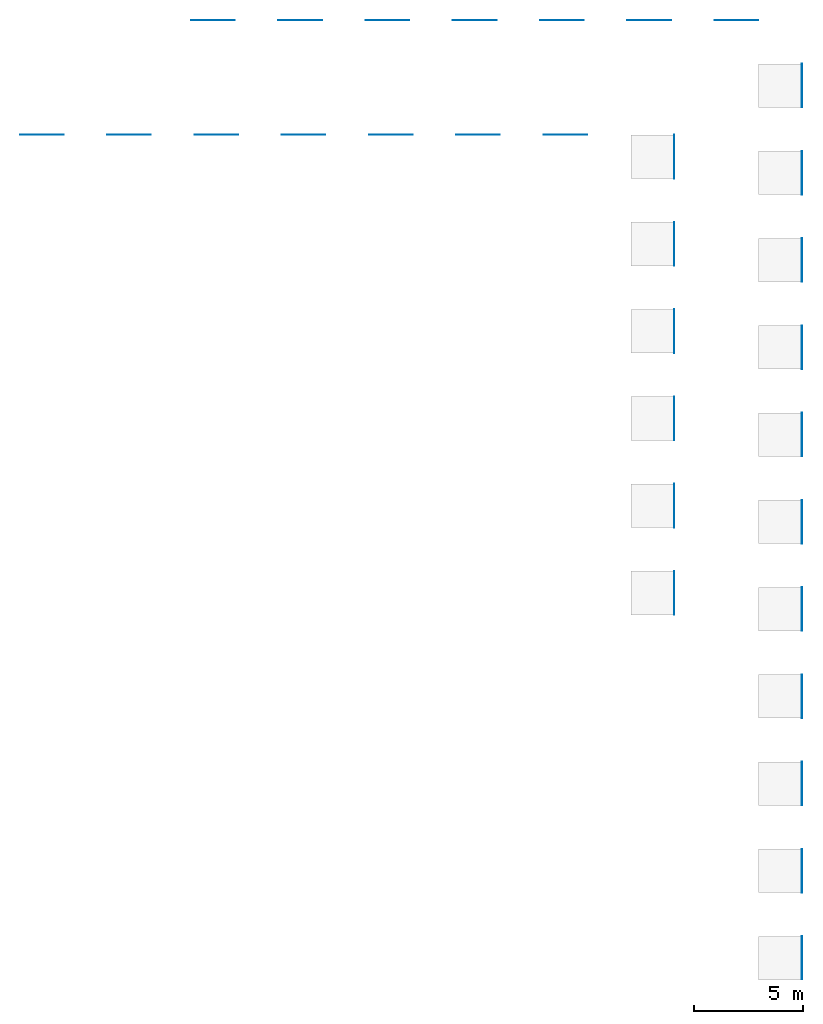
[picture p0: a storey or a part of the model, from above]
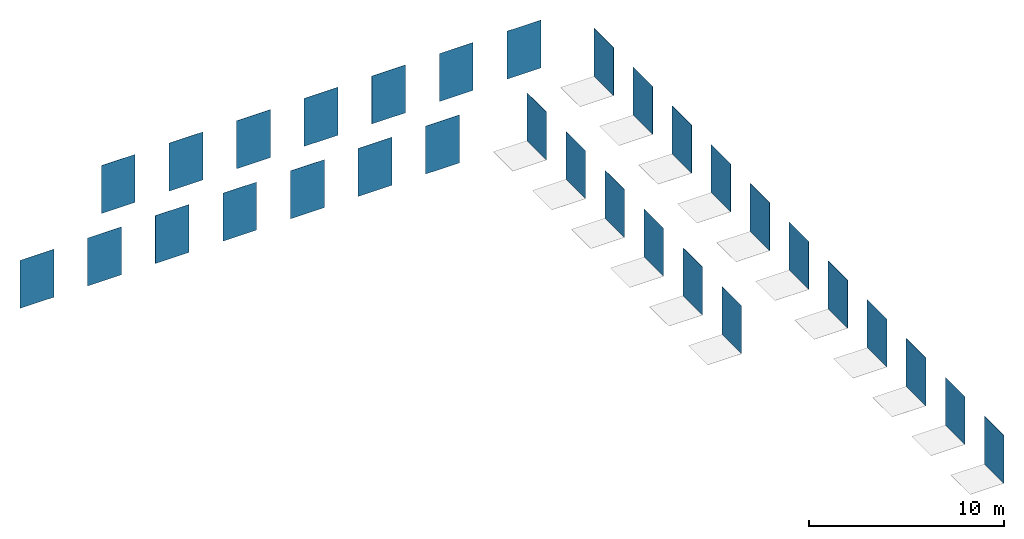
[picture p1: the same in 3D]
Properties of the parts of a building model (IFC2X3), part 1 of 3

# File
Description: ViewDefinition [CoordinationView_V2.0]
File name: Project Number
Time: 2018-07-16T11:43:54
Written by: The EXPRESS Data Manager Version 5.02.0100.07 : 28 Aug 2013
Made in: 20171027_0315(x64) - Exporter 17.2.0.0 - Alternate UI 17.2.0.0
Comment: STEP Physical File produced by: The EXPRESS Data Manager Version 5.02.0100.07 : 28 Aug 2013 * Module: EDMstepFileFactory/EDMstandAlone * Creation date: Mon Jul 16 11:43:54 2018 * Host: aieadsegarra * Database: C:\Users\ES0050~3\AppData\Local\Temp\{0624A31F-D076-47B5-B2E2-24FCC1FBA4B9}\ifc * Database version: 5507 * Database creation date: Mon Jul 16 11:43:53 2018 * Schema: IFC2X3 * Model: DataRepository.ifc * Model creation date: Mon Jul 16 11:43:54 2018 * Header model: DataRepository.ifc_HeaderModel * Header model creation date: Mon Jul 16 11:43:54 2018 * EDMuser: sdai-user * EDMgroup: sdai-group * License ID and type: 5605 : Permanent license. Expiry date: * EDMstepFileFactory options: 020000

# IfcProject, Project Number
LongName: Project Name; Phase: Project Status

# IfcSite, Default
RefLatitude: 42, 21, 31, 181945; RefLongitude: -71, -3, -24, -263305; RefElevation: 0 mm

# IfcBuildingStorey, Level 1
LongName: Level 1; Elevation: 0 mm

# IfcCovering: Floor:PGR_Porcelanosa_CeramicTiles_Bottega_Acero-1200x1200mm-100227107, Floor:PGR_Porcelanosa_CeramicTiles_Bottega_Acero-1200x1200mm-100227107:202324
In: Level 1
PredefinedType: FLOORING; Material: PGR_Porcelanosa_CeramicTiles_Bottega_Acero-1200x1200mm-100227107 12 mm
NBS_General - Author: Porcelanosa Group; BIMObjectName: PGR_Porcelanosa_CeramicTiles_Bottega_Acero-1200x1200mm-100227107; ManufacturerURL: www.porcelanosa.com; NBSDescription: Ceramic Tiles; NBSReference: 45-80-95/310; ProductInformation: http://calidad.info-grupo.com:8081/GeneraFicha3/PDF?articulo=100227107&lang=EN&un=0; Revision: n/a; Uniclass2015Code: Pr_35_93_96_19; Uniclass2015Title: Ceramic Tiles; Uniclass2015Version: Products v1.5; Version: 1
COBie - AccessibilityPerformance: See ProductInformation (Technical PDF); AssetType: Fixed; Category: Floors; CodePerformance: ISO-13006:2012; UNE-EN 14411:2012; Color: Gris; Constituents: Clays, feldespat and glaze; Description: Rectified Porcelain tiles, BOTEGA series from PORCELANOSA, GRIS color and MATTE finish, 120x120 cm (11.5 mm thickness), group BIa, according to UNE-EN 14411, water absortion capacity E<=0.5%, flexural strength >40 N/mm², breaking strength with an average value of 3310 N (Min. 1300 N) and slip resistance R-10; DurationUnit: year; ExpectedLife: 50; Features: See ProductInformation (Technical PDF); Grade: First quality; Manufacturer: bim.gp@porcelanosagrupo.com; ModelNumber: 100227107; ModelReference: Bottega Acero 120x120 cm; Name: CeramicTiles_Bottega_Acero-1200x1200mm-100227107; NominalHeight: 11.5 mm; NominalLength: 1200 mm; NominalWidth: 1200 mm; ReplacementCost: n/a; Shape: Squared; Size: 1200x1200x11.5 mm; Sustainability Performance: See ProductInformation (Technical PDF); WarrantyDescription: Manufacturer warranty, applicable worldwide, with the pertinent national legislation prevailing in all cases and covering at least a 3-year period; all products must have been manufactured and fitted in accordance with the Fabricator's Manual, and have been used and cared for in accordance with the Guide to Use, Cleaning and Care available on the web page www.porcelanosa.com; WarrantyDurationLabor: n/a; WarrantyDurationParts: 3; WarrantyDurationUnit: year; WarrantyGuarantorLabor: n/a; WarrantyGuarantorParts: bim.gp@porcelanosagrupo.com; AssetIdentifier: n/a; BarCode: n/a; InstallationDate: 1900-12-31T23:59:59; TagNumber: n/a; WarrantyStartDate: 1900-12-31T23:59:59
Pset_CoveringCommon - AcousticRating: n/a; Finish: Concrete, Tone Variations, Matte, Rectified; FireRating: A1; FlammabilityRating: Class 0; FragilityRating: n/a; IsExternal: yes; Material: Ceramic; SurfaceSpreadOfFlame: Class 0; ThermalTransmittance: 200 kg/K/s3; TotalThickness: 11.5 mm; Reference: n/a
Pset_CoveringFlooring - HasAntiStaticSurface: no; HasNonSkidSurface: no
IFC - IfcExportType: FLOORING; IfcExportAS: IfcCovering
NBS_Data - AbrasionResistance: 6: Intense-External Access; BreakingStrength: Average Value: 3310 N (Min. 1300 N); ChemicalResistance: Class 'A' for swimming pools and cleaning products (resists attack); minimum Class 'B' for acids and bases; Collection: Porcelanico Tecnico; CreationDate: 2018/07; Dcof: n/a; FlexuralStrength: http://www.porcelanosa.com/product_finder/resources/pdf/inscol/files/GENCER-Fixing-Instructions.pdf; FrostResistance: >40 N/mm²; Group: Conforms to ISO 10545-9; HasSurfaceRoughness: no; MoistureExpansion: <(6.5x10e-6)/°K; RampTest: <0.1 mm/m; RecycledContent: R-10; Series: >6.5%; SlipResistanceValuePendulumTestValue: Botega; StainResistance: CL1; SurfaceQuality: Class 5: Easy cleaning with water; ThermalShockResistance: Without surface defects; UpecC: n/a; UpecE: n/a; UpecP: n/a; UpecU: Conforms to ISO 10545–12; WaterAbsorption: n/a

# IfcCovering: Floor:PGR_Porcelanosa_CeramicTiles_Bottega_Acero-443x443mm-100225055, Floor:PGR_Porcelanosa_CeramicTiles_Bottega_Acero-443x443mm-100225055:213377
In: Level 1
PredefinedType: FLOORING; Material: PGR_Porcelanosa_CeramicTiles_Bottega_Acero-443x443mm-100225055 10.3 mm
NBS_General - Author: Porcelanosa Group; BIMObjectName: PGR_Porcelanosa_CeramicTiles_Bottega_Acero-443x443mm-100225055; ManufacturerURL: www.porcelanosa.com; NBSDescription: Ceramic Tiles; NBSReference: 45-80-95/310; ProductInformation: http://calidad.info-grupo.com:8081/GeneraFicha3/PDF?articulo=100225055&lang=EN&un=0; Revision: n/a; Uniclass2015Code: Pr_35_93_96_19; Uniclass2015Title: Ceramic Tiles; Uniclass2015Version: Products v1.5; Version: 1
COBie - AccessibilityPerformance: See ProductInformation (Technical PDF); AssetType: Fixed; Category: Floors; CodePerformance: ISO-13006:2012; UNE-EN 14411:2012; Color: Gris; Constituents: Clays, feldespat and glaze; Description: Porcelain tiles, BOTEGA series from PORCELANOSA, GRIS color and MATTE finish, 44.3x44.3 cm (10 mm thickness), group BIa, according to UNE-EN 14411, water absortion capacity E<=0.5%, flexural strength >40 N/mm², breaking strength with an average value of 3310 N (Min. 1300 N) and slip resistance R-10; DurationUnit: year; ExpectedLife: 50; Features: See ProductInformation (Technical PDF); Grade: First quality; Manufacturer: bim.gp@porcelanosagrupo.com; ModelNumber: 100225055; ModelReference: Bottega Acero 44.3x44.3 cm; Name: CeramicTiles_Bottega_Acero-443x443mm-100225055; NominalHeight: 10 mm; NominalLength: 443 mm; NominalWidth: 443 mm; ReplacementCost: n/a; Shape: Squared; Size: 443x443x10 mm; Sustainability Performance: See ProductInformation (Technical PDF); WarrantyDescription: Manufacturer warranty, applicable worldwide, with the pertinent national legislation prevailing in all cases and covering at least a 3-year period; all products must have been manufactured and fitted in accordance with the Fabricator's Manual, and have been used and cared for in accordance with the Guide to Use, Cleaning and Care available on the web page www.porcelanosa.com; WarrantyDurationLabor: n/a; WarrantyDurationParts: 3; WarrantyDurationUnit: year; WarrantyGuarantorLabor: n/a; WarrantyGuarantorParts: bim.gp@porcelanosagrupo.com; AssetIdentifier: n/a; BarCode: n/a; InstallationDate: 1900-12-31T23:59:59; TagNumber: n/a; WarrantyStartDate: 1900-12-31T23:59:59
Pset_CoveringCommon - IsExternal: yes; Reference: n/a; AcousticRating: n/a; Finish: Concrete, Tone Variations, Matte; FireRating: A1; FlammabilityRating: Class 0; FragilityRating: n/a; Material: Ceramic; SurfaceSpreadOfFlame: Class 0; ThermalTransmittance: 230 kg/K/s3; TotalThickness: 10 mm
Pset_CoveringFlooring - HasAntiStaticSurface: no; HasNonSkidSurface: no
IFC - IfcExportType: FLOORING; IfcExportAS: IfcCovering
NBS_Data - HasSurfaceRoughness: no; AbrasionResistance: 6: Intense-External Access; BreakingStrength: Average Value: 3310 N (Min. 1300 N); ChemicalResistance: Class 'A' for swimming pools and cleaning products (resists attack); minimum Class 'B' for acids and bases; Collection: Porcelanico; CreationDate: 2018/07; Dcof: n/a; FlexuralStrength: http://www.porcelanosa.com/product_finder/resources/pdf/inscol/files/GENCER-Fixing-Instructions.pdf; FrostResistance: >40 N/mm²; Group: Conforms to ISO 10545-9; MoistureExpansion: <(6.5x10e-6)/°K; RampTest: <0.1 mm/m; RecycledContent: R-10; Series: >6.5%; SlipResistanceValuePendulumTestValue: Botega; StainResistance: CL1; SurfaceQuality: Class 5: Easy cleaning with water; ThermalShockResistance: Without surface defects; UpecC: n/a; UpecE: n/a; UpecP: n/a; UpecU: Conforms to ISO 10545–12; WaterAbsorption: n/a

# IfcCovering: Floor:PGR_Porcelanosa_CeramicTiles_Bottega_Acero-596x596mm-100214641, Floor:PGR_Porcelanosa_CeramicTiles_Bottega_Acero-596x596mm-100214641:213277
In: Level 1
PredefinedType: FLOORING; Material: PGR_Porcelanosa_CeramicTiles_Bottega_Acero-596x596mm-100214641 10.3 mm
NBS_General - Author: Porcelanosa Group; BIMObjectName: PGR_Porcelanosa_CeramicTiles_Bottega_Acero-596x596mm-100214641; ManufacturerURL: www.porcelanosa.com; NBSDescription: Ceramic Tiles; NBSReference: 45-80-95/310; ProductInformation: http://calidad.info-grupo.com:8081/GeneraFicha3/PDF?articulo=100214641&lang=EN&un=0; Revision: n/a; Uniclass2015Code: Pr_35_93_96_19; Uniclass2015Title: Ceramic Tiles; Uniclass2015Version: Products v1.5; Version: 1
COBie - AccessibilityPerformance: See ProductInformation (Technical PDF); AssetType: Fixed; Category: Floors; CodePerformance: ISO-13006:2012; UNE-EN 14411:2012; Color: Gris; Constituents: Clays, feldespat and glaze; Description: Rectified Porcelain tiles, BOTEGA series from PORCELANOSA, GRIS color and MATTE finish, 59.6x59.6 cm (10.3 mm thickness), group BIa, according to UNE-EN 14411, water absortion capacity E<=0.5%, flexural strength >40 N/mm², breaking strength with an average value of 3310 N (Min. 1300 N) and slip resistance R-10; DurationUnit: year; ExpectedLife: 50; Features: See ProductInformation (Technical PDF); Grade: First quality; Manufacturer: bim.gp@porcelanosagrupo.com; ModelNumber: 100214641; ModelReference: Bottega Acero 59.6x59.6 cm; Name: CeramicTiles_Bottega_Acero-596x596mm-100214641; NominalHeight: 10.3 mm; NominalLength: 596 mm; NominalWidth: 596 mm; ReplacementCost: n/a; Shape: Squared; Size: 596x596x10.3 mm; Sustainability Performance: See ProductInformation (Technical PDF); WarrantyDescription: Manufacturer warranty, applicable worldwide, with the pertinent national legislation prevailing in all cases and covering at least a 3-year period; all products must have been manufactured and fitted in accordance with the Fabricator's Manual, and have been used and cared for in accordance with the Guide to Use, Cleaning and Care available on the web page www.porcelanosa.com; WarrantyDurationLabor: n/a; WarrantyDurationParts: 3; WarrantyDurationUnit: year; WarrantyGuarantorLabor: n/a; WarrantyGuarantorParts: bim.gp@porcelanosagrupo.com; AssetIdentifier: n/a; BarCode: n/a; InstallationDate: 1900-12-31T23:59:59; TagNumber: n/a; WarrantyStartDate: 1900-12-31T23:59:59
Pset_CoveringCommon - IsExternal: yes; Reference: n/a; AcousticRating: n/a; Finish: Concrete, Tone Variations, Matte, Rectified; FireRating: A1; FlammabilityRating: Class 0; FragilityRating: n/a; Material: Ceramic; SurfaceSpreadOfFlame: Class 0; ThermalTransmittance: 223.301 kg/K/s3; TotalThickness: 10.3 mm
Pset_CoveringFlooring - HasAntiStaticSurface: no; HasNonSkidSurface: no
IFC - IfcExportType: FLOORING; IfcExportAS: IfcCovering
NBS_Data - HasSurfaceRoughness: no; AbrasionResistance: 6: Intense-External Access; BreakingStrength: Average Value: 3310 N (Min. 1300 N); ChemicalResistance: Class 'A' for swimming pools and cleaning products (resists attack); minimum Class 'B' for acids and bases; Collection: STON-KER; CreationDate: 2018/07; Dcof: n/a; FlexuralStrength: http://www.porcelanosa.com/product_finder/resources/pdf/inscol/files/GENCER-Fixing-Instructions.pdf; FrostResistance: >40 N/mm²; Group: Conforms to ISO 10545-9; MoistureExpansion: <(6.5x10e-6)/°K; RampTest: <0.1 mm/m; RecycledContent: R-10; Series: >6.5%; SlipResistanceValuePendulumTestValue: Botega; StainResistance: CL1; SurfaceQuality: Class 5: Easy cleaning with water; ThermalShockResistance: Without surface defects; UpecC: n/a; UpecE: n/a; UpecP: n/a; UpecU: Conforms to ISO 10545–12; WaterAbsorption: n/a

# IfcCovering: Floor:PGR_Porcelanosa_CeramicTiles_Bottega_Acero-800x800mm-100214633, Floor:PGR_Porcelanosa_CeramicTiles_Bottega_Acero-800x800mm-100214633:213287
In: Level 1
PredefinedType: FLOORING; Material: PGR_Porcelanosa_CeramicTiles_Bottega_Acero-800x800mm-100214633 11.2 mm
NBS_General - Author: Porcelanosa Group; BIMObjectName: PGR_Porcelanosa_CeramicTiles_Bottega_Acero-800x800mm-100214633; ManufacturerURL: www.porcelanosa.com; NBSDescription: Ceramic Tiles; NBSReference: 45-80-95/310; ProductInformation: http://calidad.info-grupo.com:8081/GeneraFicha3/PDF?articulo=100214633&lang=EN&un=0; Revision: n/a; Uniclass2015Code: Pr_35_93_96_19; Uniclass2015Title: Ceramic Tiles; Uniclass2015Version: Products v1.5; Version: 1
COBie - AccessibilityPerformance: See ProductInformation (Technical PDF); AssetType: Fixed; Category: Floors; CodePerformance: ISO-13006:2012; UNE-EN 14411:2012; Color: Gris; Constituents: Clays, feldespat and glaze; Description: Rectified Porcelain tiles, BOTEGA series from PORCELANOSA, GRIS color and MATTE finish, 80x80 cm (11.2 mm thickness), group BIa, according to UNE-EN 14411, water absortion capacity E<=0.5%, flexural strength >40 N/mm², breaking strength with an average value of 3310 N (Min. 1300 N) and slip resistance R-10; DurationUnit: year; ExpectedLife: 50; Features: See ProductInformation (Technical PDF); Grade: First quality; Manufacturer: bim.gp@porcelanosagrupo.com; ModelNumber: 100214633; ModelReference: Bottega Acero 80x80 cm; Name: CeramicTiles_Bottega_Acero-800x800mm-100214633; NominalHeight: 11.2 mm; NominalLength: 800 mm; NominalWidth: 800 mm; ReplacementCost: n/a; Shape: Squared; Size: 800x800x11.2 mm; Sustainability Performance: See ProductInformation (Technical PDF); WarrantyDescription: Manufacturer warranty, applicable worldwide, with the pertinent national legislation prevailing in all cases and covering at least a 3-year period; all products must have been manufactured and fitted in accordance with the Fabricator's Manual, and have been used and cared for in accordance with the Guide to Use, Cleaning and Care available on the web page www.porcelanosa.com; WarrantyDurationLabor: n/a; WarrantyDurationParts: 3; WarrantyDurationUnit: year; WarrantyGuarantorLabor: n/a; WarrantyGuarantorParts: bim.gp@porcelanosagrupo.com; AssetIdentifier: n/a; BarCode: n/a; InstallationDate: 1900-12-31T23:59:59; TagNumber: n/a; WarrantyStartDate: 1900-12-31T23:59:59
Pset_CoveringCommon - IsExternal: yes; Reference: n/a; AcousticRating: n/a; Finish: Concrete, Tone Variations, Matte, Rectified; FireRating: A1; FlammabilityRating: Class 0; FragilityRating: n/a; Material: Ceramic; SurfaceSpreadOfFlame: Class 0; ThermalTransmittance: 205.357 kg/K/s3; TotalThickness: 11.2 mm
Pset_CoveringFlooring - HasAntiStaticSurface: no; HasNonSkidSurface: no
IFC - IfcExportType: FLOORING; IfcExportAS: IfcCovering
NBS_Data - HasSurfaceRoughness: no; AbrasionResistance: 6: Intense-External Access; BreakingStrength: Average Value: 3310 N (Min. 1300 N); ChemicalResistance: Class 'A' for swimming pools and cleaning products (resists attack); minimum Class 'B' for acids and bases; Collection: STON-KER; CreationDate: 2018/07; Dcof: n/a; FlexuralStrength: http://www.porcelanosa.com/product_finder/resources/pdf/inscol/files/GENCER-Fixing-Instructions.pdf; FrostResistance: >40 N/mm²; Group: Conforms to ISO 10545-9; MoistureExpansion: <(6.5x10e-6)/°K; RampTest: <0.1 mm/m; RecycledContent: R-10; Series: >6.5%; SlipResistanceValuePendulumTestValue: Botega; StainResistance: CL1; SurfaceQuality: Class 5: Easy cleaning with water; ThermalShockResistance: Without surface defects; UpecC: n/a; UpecE: n/a; UpecP: n/a; UpecU: Conforms to ISO 10545–12; WaterAbsorption: n/a

# IfcCovering: Floor:PGR_Porcelanosa_CeramicTiles_Bottega_Acero_Ant.-596x596mm-100221464, Floor:PGR_Porcelanosa_CeramicTiles_Bottega_Acero_Ant.-596x596mm-100221464:213297
In: Level 1
PredefinedType: FLOORING; Material: PGR_Porcelanosa_CeramicTiles_Bottega_Acero_Ant.-596x596mm-100221464 10.3 mm
NBS_General - Author: Porcelanosa Group; BIMObjectName: PGR_Porcelanosa_CeramicTiles_Bottega_Acero_Ant.-596x596mm-100221464; ManufacturerURL: www.porcelanosa.com; NBSDescription: Ceramic Tiles; NBSReference: 45-80-95/310; ProductInformation: http://calidad.info-grupo.com:8081/GeneraFicha3/PDF?articulo=100221464&lang=EN&un=0; Revision: n/a; Uniclass2015Code: Pr_35_93_96_19; Uniclass2015Title: Ceramic Tiles; Uniclass2015Version: Products v1.5; Version: 1
COBie - AccessibilityPerformance: See ProductInformation (Technical PDF); AssetType: Fixed; Category: Floors; CodePerformance: ISO-13006:2012; UNE-EN 14411:2012; Color: Gris; Constituents: Clays, feldespat and glaze; Description: Rectified Porcelain tiles, BOTEGA series from PORCELANOSA, GRIS color and MATTE finish, 59.6x59.6 cm (10.3 mm thickness), group BIa, according to UNE-EN 14411, water absortion capacity E<=0.5%, flexural strength >40 N/mm², breaking strength with an average value of 3310 N (Min. 1300 N) and slip resistance R-13; DurationUnit: year; ExpectedLife: 50; Features: See ProductInformation (Technical PDF); Grade: First quality; Manufacturer: bim.gp@porcelanosagrupo.com; ModelNumber: 100221464; ModelReference: Bottega Acero Ant. 59.6x59.6 cm; Name: CeramicTiles_Bottega_Acero_Ant.-596x596mm-100221464; NominalHeight: 10.3 mm; NominalLength: 596 mm; NominalWidth: 596 mm; ReplacementCost: n/a; Shape: Squared; Size: 596x596x10.3 mm; Sustainability Performance: See ProductInformation (Technical PDF); WarrantyDescription: Manufacturer warranty, applicable worldwide, with the pertinent national legislation prevailing in all cases and covering at least a 3-year period; all products must have been manufactured and fitted in accordance with the Fabricator's Manual, and have been used and cared for in accordance with the Guide to Use, Cleaning and Care available on the web page www.porcelanosa.com; WarrantyDurationLabor: n/a; WarrantyDurationParts: 3; WarrantyDurationUnit: year; WarrantyGuarantorLabor: n/a; WarrantyGuarantorParts: bim.gp@porcelanosagrupo.com; AssetIdentifier: n/a; BarCode: n/a; InstallationDate: 1900-12-31T23:59:59; TagNumber: n/a; WarrantyStartDate: 1900-12-31T23:59:59
Pset_CoveringCommon - IsExternal: yes; Reference: n/a; AcousticRating: n/a; Finish: Concrete, Tone Variations, Matte, Non-Slip, Rectified; FireRating: A1; FlammabilityRating: Class 0; FragilityRating: n/a; Material: Ceramic; SurfaceSpreadOfFlame: Class 0; ThermalTransmittance: 223.301 kg/K/s3; TotalThickness: 10.3 mm
Pset_CoveringFlooring - HasAntiStaticSurface: no; HasNonSkidSurface: yes
IFC - IfcExportType: FLOORING; IfcExportAS: IfcCovering
NBS_Data - HasSurfaceRoughness: no; AbrasionResistance: 6: Intense-External Access; BreakingStrength: Average Value: 3310 N (Min. 1300 N); ChemicalResistance: Class 'A' for swimming pools and cleaning products (resists attack); minimum Class 'B' for acids and bases; Collection: STON-KER; CreationDate: 2018/07; Dcof: >0.42; FlexuralStrength: http://www.porcelanosa.com/product_finder/resources/pdf/inscol/files/GENCER-Fixing-Instructions.pdf; FrostResistance: >40 N/mm²; Group: Conforms to ISO 10545-9; MoistureExpansion: <(6.5x10e-6)/°K; RampTest: <0.1 mm/m; RecycledContent: R-13; Series: >6.5%; SlipResistanceValuePendulumTestValue: Botega; StainResistance: CL3; SurfaceQuality: Class 5: Easy cleaning with water; ThermalShockResistance: Without surface defects; UpecC: n/a; UpecE: n/a; UpecP: n/a; UpecU: Conforms to ISO 10545–12; WaterAbsorption: n/a

# IfcCovering: Floor:PGR_Porcelanosa_CeramicTiles_Bottega_Acero_Ant.-800x800mm-100221486, Floor:PGR_Porcelanosa_CeramicTiles_Bottega_Acero_Ant.-800x800mm-100221486:213307
In: Level 1
PredefinedType: FLOORING; Material: PGR_Porcelanosa_CeramicTiles_Bottega_Acero_Ant.-800x800mm-100221486 11.2 mm
NBS_General - Author: Porcelanosa Group; BIMObjectName: PGR_Porcelanosa_CeramicTiles_Bottega_Acero_Ant.-800x800mm-100221486; ManufacturerURL: www.porcelanosa.com; NBSDescription: Ceramic Tiles; NBSReference: 45-80-95/310; ProductInformation: http://calidad.info-grupo.com:8081/GeneraFicha3/PDF?articulo=100221486&lang=EN&un=0; Revision: n/a; Uniclass2015Code: Pr_35_93_96_19; Uniclass2015Title: Ceramic Tiles; Uniclass2015Version: Products v1.5; Version: 1
COBie - AccessibilityPerformance: See ProductInformation (Technical PDF); AssetType: Fixed; Category: Floors; CodePerformance: ISO-13006:2012; UNE-EN 14411:2012; Color: Gris; Constituents: Clays, feldespat and glaze; Description: Rectified Porcelain tiles, BOTEGA series from PORCELANOSA, GRIS color and MATTE finish, 80x80 cm (11.2 mm thickness), group BIa, according to UNE-EN 14411, water absortion capacity E<=0.5%, flexural strength >40 N/mm², breaking strength with an average value of 3310 N (Min. 1300 N) and slip resistance R-13; DurationUnit: year; ExpectedLife: 50; Features: See ProductInformation (Technical PDF); Grade: First quality; Manufacturer: bim.gp@porcelanosagrupo.com; ModelNumber: 100221486; ModelReference: Bottega Acero Ant. 80x80 cm; Name: CeramicTiles_Bottega_Acero_Ant.-800x800mm-100221486; NominalHeight: 11.2 mm; NominalLength: 800 mm; NominalWidth: 800 mm; ReplacementCost: n/a; Shape: Squared; Size: 800x800x11.2 mm; Sustainability Performance: See ProductInformation (Technical PDF); WarrantyDescription: Manufacturer warranty, applicable worldwide, with the pertinent national legislation prevailing in all cases and covering at least a 3-year period; all products must have been manufactured and fitted in accordance with the Fabricator's Manual, and have been used and cared for in accordance with the Guide to Use, Cleaning and Care available on the web page www.porcelanosa.com; WarrantyDurationLabor: n/a; WarrantyDurationParts: 3; WarrantyDurationUnit: year; WarrantyGuarantorLabor: n/a; WarrantyGuarantorParts: bim.gp@porcelanosagrupo.com; AssetIdentifier: n/a; BarCode: n/a; InstallationDate: 1900-12-31T23:59:59; TagNumber: n/a; WarrantyStartDate: 1900-12-31T23:59:59
Pset_CoveringCommon - IsExternal: yes; Reference: n/a; AcousticRating: n/a; Finish: Concrete, Tone Variations, Matte, Non-Slip, Rectified; FireRating: A1; FlammabilityRating: Class 0; FragilityRating: n/a; Material: Ceramic; SurfaceSpreadOfFlame: Class 0; ThermalTransmittance: 205.357 kg/K/s3; TotalThickness: 11.2 mm
Pset_CoveringFlooring - HasAntiStaticSurface: no; HasNonSkidSurface: yes
IFC - IfcExportType: FLOORING; IfcExportAS: IfcCovering
NBS_Data - HasSurfaceRoughness: no; AbrasionResistance: 6: Intense-External Access; BreakingStrength: Average Value: 3310 N (Min. 1300 N); ChemicalResistance: Class 'A' for swimming pools and cleaning products (resists attack); minimum Class 'B' for acids and bases; Collection: STON-KER; CreationDate: 2018/07; Dcof: >0.42; FlexuralStrength: http://www.porcelanosa.com/product_finder/resources/pdf/inscol/files/GENCER-Fixing-Instructions.pdf; FrostResistance: >40 N/mm²; Group: Conforms to ISO 10545-9; MoistureExpansion: <(6.5x10e-6)/°K; RampTest: <0.1 mm/m; RecycledContent: R-13; Series: >6.5%; SlipResistanceValuePendulumTestValue: Botega; StainResistance: CL3; SurfaceQuality: Class 5: Easy cleaning with water; ThermalShockResistance: Without surface defects; UpecC: n/a; UpecE: n/a; UpecP: n/a; UpecU: Conforms to ISO 10545–12; WaterAbsorption: n/a

# IfcCovering: Floor:PGR_Porcelanosa_CeramicTiles_Bottega_Caliza-1200x1200mm-100214898, Floor:PGR_Porcelanosa_CeramicTiles_Bottega_Caliza-1200x1200mm-100214898:213317
In: Level 1
PredefinedType: FLOORING; Material: PGR_Porcelanosa_CeramicTiles_Bottega_Caliza-1200x1200mm-100214898 12 mm
NBS_General - Author: Porcelanosa Group; BIMObjectName: PGR_Porcelanosa_CeramicTiles_Bottega_Caliza-1200x1200mm-100214898; ManufacturerURL: www.porcelanosa.com; NBSDescription: Ceramic Tiles; NBSReference: 45-80-95/310; ProductInformation: http://calidad.info-grupo.com:8081/GeneraFicha3/PDF?articulo=100214898&lang=EN&un=0; Revision: n/a; Uniclass2015Code: Pr_35_93_96_19; Uniclass2015Title: Ceramic Tiles; Uniclass2015Version: Products v1.5; Version: 1
COBie - AccessibilityPerformance: See ProductInformation (Technical PDF); AssetType: Fixed; Category: Floors; CodePerformance: ISO-13006:2012; UNE-EN 14411:2012; Color: Beige; Constituents: Clays, feldespat and glaze; Description: Rectified Porcelain tiles, BOTEGA series from PORCELANOSA, BEIGE color and MATTE finish, 120x120 cm (11.5 mm thickness), group BIa, according to UNE-EN 14411, water absortion capacity E<=0.5%, flexural strength >40 N/mm², breaking strength with an average value of 3310 N (Min. 1300 N) and slip resistance R-10; DurationUnit: year; ExpectedLife: 50; Features: See ProductInformation (Technical PDF); Grade: First quality; Manufacturer: bim.gp@porcelanosagrupo.com; ModelNumber: 100214898; ModelReference: Bottega Caliza 120x120 cm; Name: CeramicTiles_Bottega_Caliza-1200x1200mm-100214898; NominalHeight: 11.5 mm; NominalLength: 1200 mm; NominalWidth: 1200 mm; ReplacementCost: n/a; Shape: Squared; Size: 1200x1200x11.5 mm; Sustainability Performance: See ProductInformation (Technical PDF); WarrantyDescription: Manufacturer warranty, applicable worldwide, with the pertinent national legislation prevailing in all cases and covering at least a 3-year period; all products must have been manufactured and fitted in accordance with the Fabricator's Manual, and have been used and cared for in accordance with the Guide to Use, Cleaning and Care available on the web page www.porcelanosa.com; WarrantyDurationLabor: n/a; WarrantyDurationParts: 3; WarrantyDurationUnit: year; WarrantyGuarantorLabor: n/a; WarrantyGuarantorParts: bim.gp@porcelanosagrupo.com; AssetIdentifier: n/a; BarCode: n/a; InstallationDate: 1900-12-31T23:59:59; TagNumber: n/a; WarrantyStartDate: 1900-12-31T23:59:59
Pset_CoveringCommon - IsExternal: yes; Reference: n/a; AcousticRating: n/a; Finish: Concrete, Tone Variations, Matte, Rectified; FireRating: A1; FlammabilityRating: Class 0; FragilityRating: n/a; Material: Ceramic; SurfaceSpreadOfFlame: Class 0; ThermalTransmittance: 200 kg/K/s3; TotalThickness: 11.5 mm
Pset_CoveringFlooring - HasAntiStaticSurface: no; HasNonSkidSurface: no
IFC - IfcExportType: FLOORING; IfcExportAS: IfcCovering
NBS_Data - HasSurfaceRoughness: no; AbrasionResistance: 6: Intense-External Access; BreakingStrength: Average Value: 3310 N (Min. 1300 N); ChemicalResistance: Class 'A' for swimming pools and cleaning products (resists attack); minimum Class 'B' for acids and bases; Collection: Porcelanico Tecnico; CreationDate: 2018/07; Dcof: n/a; FlexuralStrength: http://www.porcelanosa.com/product_finder/resources/pdf/inscol/files/GENCER-Fixing-Instructions.pdf; FrostResistance: >40 N/mm²; Group: Conforms to ISO 10545-9; MoistureExpansion: <(6.5x10e-6)/°K; RampTest: <0.1 mm/m; RecycledContent: R-10; Series: >6.5%; SlipResistanceValuePendulumTestValue: Botega; StainResistance: CL1; SurfaceQuality: Class 5: Easy cleaning with water; ThermalShockResistance: Without surface defects; UpecC: n/a; UpecE: n/a; UpecP: n/a; UpecU: Conforms to ISO 10545–12; WaterAbsorption: n/a

# IfcCovering: Floor:PGR_Porcelanosa_CeramicTiles_Bottega_Caliza-443x443mm-100225065, Floor:PGR_Porcelanosa_CeramicTiles_Bottega_Caliza-443x443mm-100225065:213387
In: Level 1
PredefinedType: FLOORING; Material: PGR_Porcelanosa_CeramicTiles_Bottega_Caliza-443x443mm-100225065 11.2 mm
NBS_General - Author: Porcelanosa Group; BIMObjectName: PGR_Porcelanosa_CeramicTiles_Bottega_Caliza-443x443mm-100225065; ManufacturerURL: www.porcelanosa.com; NBSDescription: Ceramic Tiles; NBSReference: 45-80-95/310; ProductInformation: http://calidad.info-grupo.com:8081/GeneraFicha3/PDF?articulo=100225065&lang=EN&un=0; Revision: n/a; Uniclass2015Code: Pr_35_93_96_19; Uniclass2015Title: Ceramic Tiles; Uniclass2015Version: Products v1.5; Version: 1
COBie - AccessibilityPerformance: See ProductInformation (Technical PDF); AssetType: Fixed; Category: Floors; CodePerformance: ISO-13006:2012; UNE-EN 14411:2012; Color: Beige; Constituents: Clays, feldespat and glaze; Description: Porcelain tiles, BOTEGA series from PORCELANOSA, BEIGE color and MATTE finish, 44.3x44.3 cm (10 mm thickness), group BIa, according to UNE-EN 14411, water absortion capacity E<=0.5%, flexural strength >40 N/mm², breaking strength with an average value of 3310 N (Min. 1300 N) and slip resistance R-10; DurationUnit: year; ExpectedLife: 50; Features: See ProductInformation (Technical PDF); Grade: First quality; Manufacturer: bim.gp@porcelanosagrupo.com; ModelNumber: 100225065; ModelReference: Bottega Caliza 44.3x44.3 cm; Name: CeramicTiles_Bottega_Caliza-443x443mm-100225065; NominalHeight: 10 mm; NominalLength: 443 mm; NominalWidth: 443 mm; ReplacementCost: n/a; Shape: Squared; Size: 443x443x10 mm; Sustainability Performance: See ProductInformation (Technical PDF); WarrantyDescription: Manufacturer warranty, applicable worldwide, with the pertinent national legislation prevailing in all cases and covering at least a 3-year period; all products must have been manufactured and fitted in accordance with the Fabricator's Manual, and have been used and cared for in accordance with the Guide to Use, Cleaning and Care available on the web page www.porcelanosa.com; WarrantyDurationLabor: n/a; WarrantyDurationParts: 3; WarrantyDurationUnit: year; WarrantyGuarantorLabor: n/a; WarrantyGuarantorParts: bim.gp@porcelanosagrupo.com; AssetIdentifier: n/a; BarCode: n/a; InstallationDate: 1900-12-31T23:59:59; TagNumber: n/a; WarrantyStartDate: 1900-12-31T23:59:59
Pset_CoveringCommon - IsExternal: yes; Reference: n/a; AcousticRating: n/a; Finish: Concrete, Tone Variations, Matte; FireRating: A1; FlammabilityRating: Class 0; FragilityRating: n/a; Material: Ceramic; SurfaceSpreadOfFlame: Class 0; ThermalTransmittance: 230 kg/K/s3; TotalThickness: 10 mm
Pset_CoveringFlooring - HasAntiStaticSurface: no; HasNonSkidSurface: no
IFC - IfcExportType: FLOORING; IfcExportAS: IfcCovering
NBS_Data - HasSurfaceRoughness: no; AbrasionResistance: 6: Intense-External Access; BreakingStrength: Average Value: 3310 N (Min. 1300 N); ChemicalResistance: Class 'A' for swimming pools and cleaning products (resists attack); minimum Class 'B' for acids and bases; Collection: Porcelanico; CreationDate: 2018/07; Dcof: n/a; FlexuralStrength: http://www.porcelanosa.com/product_finder/resources/pdf/inscol/files/GENCER-Fixing-Instructions.pdf; FrostResistance: >40 N/mm²; Group: Conforms to ISO 10545-9; MoistureExpansion: <(6.5x10e-6)/°K; RampTest: <0.1 mm/m; RecycledContent: R-10; Series: >6.5%; SlipResistanceValuePendulumTestValue: Botega; StainResistance: CL1; SurfaceQuality: Class 5: Easy cleaning with water; ThermalShockResistance: Without surface defects; UpecC: n/a; UpecE: n/a; UpecP: n/a; UpecU: Conforms to ISO 10545–12; WaterAbsorption: n/a

# IfcCovering: Floor:PGR_Porcelanosa_CeramicTiles_Bottega_Caliza-596x596mm-100214648, Floor:PGR_Porcelanosa_CeramicTiles_Bottega_Caliza-596x596mm-100214648:213327
In: Level 1
PredefinedType: FLOORING; Material: PGR_Porcelanosa_CeramicTiles_Bottega_Caliza-596x596mm-100214648 10.3 mm
NBS_General - Author: Porcelanosa Group; BIMObjectName: PGR_Porcelanosa_CeramicTiles_Bottega_Caliza-596x596mm-100214648; ManufacturerURL: www.porcelanosa.com; NBSDescription: Ceramic Tiles; NBSReference: 45-80-95/310; ProductInformation: http://calidad.info-grupo.com:8081/GeneraFicha3/PDF?articulo=100214648&lang=EN&un=0; Revision: n/a; Uniclass2015Code: Pr_35_93_96_19; Uniclass2015Title: Ceramic Tiles; Uniclass2015Version: Products v1.5; Version: 1
COBie - AccessibilityPerformance: See ProductInformation (Technical PDF); AssetType: Fixed; Category: Floors; CodePerformance: ISO-13006:2012; UNE-EN 14411:2012; Color: Caliza; Constituents: Clays, feldespat and glaze; Description: Rectified Porcelain tiles, BOTEGA series from PORCELANOSA, CALIZA color and MATTE finish, 59.6x59.6 cm (10.3 mm thickness), group BIa, according to UNE-EN 14411, water absortion capacity E<=0.5%, flexural strength >40 N/mm², breaking strength with an average value of 3310 N (Min. 1300 N) and slip resistance R-10; DurationUnit: year; ExpectedLife: 50; Features: See ProductInformation (Technical PDF); Grade: First quality; Manufacturer: bim.gp@porcelanosagrupo.com; ModelNumber: 100214648; ModelReference: Bottega Caliza 59.6x59.6 cm; Name: CeramicTiles_Bottega_Caliza-596x596mm-100214648; NominalHeight: 10.3 mm; NominalLength: 596 mm; NominalWidth: 596 mm; ReplacementCost: n/a; Shape: Squared; Size: 596x596x10.3 mm; Sustainability Performance: See ProductInformation (Technical PDF); WarrantyDescription: Manufacturer warranty, applicable worldwide, with the pertinent national legislation prevailing in all cases and covering at least a 3-year period; all products must have been manufactured and fitted in accordance with the Fabricator's Manual, and have been used and cared for in accordance with the Guide to Use, Cleaning and Care available on the web page www.porcelanosa.com; WarrantyDurationLabor: n/a; WarrantyDurationParts: 3; WarrantyDurationUnit: year; WarrantyGuarantorLabor: n/a; WarrantyGuarantorParts: bim.gp@porcelanosagrupo.com; AssetIdentifier: n/a; BarCode: n/a; InstallationDate: 1900-12-31T23:59:59; TagNumber: n/a; WarrantyStartDate: 1900-12-31T23:59:59
Pset_CoveringCommon - IsExternal: yes; Reference: n/a; AcousticRating: n/a; Finish: Concrete, Tone Variations, Matte, Rectified; FireRating: A1; FlammabilityRating: Class 0; FragilityRating: n/a; Material: Ceramic; SurfaceSpreadOfFlame: Class 0; ThermalTransmittance: 223.301 kg/K/s3; TotalThickness: 10.3 mm
Pset_CoveringFlooring - HasAntiStaticSurface: no; HasNonSkidSurface: no
IFC - IfcExportType: FLOORING; IfcExportAS: IfcCovering
NBS_Data - HasSurfaceRoughness: no; AbrasionResistance: 6: Intense-External Access; BreakingStrength: Average Value: 3310 N (Min. 1300 N); ChemicalResistance: Class 'A' for swimming pools and cleaning products (resists attack); minimum Class 'B' for acids and bases; Collection: STON-KER; CreationDate: 2018/07; Dcof: n/a; FlexuralStrength: http://www.porcelanosa.com/product_finder/resources/pdf/inscol/files/GENCER-Fixing-Instructions.pdf; FrostResistance: >40 N/mm²; Group: Conforms to ISO 10545-9; MoistureExpansion: <(6.5x10e-6)/°K; RampTest: <0.1 mm/m; RecycledContent: R-10; Series: >6.5%; SlipResistanceValuePendulumTestValue: Botega; StainResistance: CL1; SurfaceQuality: Class 5: Easy cleaning with water; ThermalShockResistance: Without surface defects; UpecC: n/a; UpecE: n/a; UpecP: n/a; UpecU: Conforms to ISO 10545–12; WaterAbsorption: n/a

# IfcCovering: Floor:PGR_Porcelanosa_CeramicTiles_Bottega_Caliza-800x800mm-100214608, Floor:PGR_Porcelanosa_CeramicTiles_Bottega_Caliza-800x800mm-100214608:213337
In: Level 1
PredefinedType: FLOORING; Material: PGR_Porcelanosa_CeramicTiles_Bottega_Caliza-800x800mm-100214608 11.2 mm
NBS_General - Author: Porcelanosa Group; BIMObjectName: PGR_Porcelanosa_CeramicTiles_Bottega_Caliza-800x800mm-100214608; ManufacturerURL: www.porcelanosa.com; NBSDescription: Ceramic Tiles; NBSReference: 45-80-95/310; ProductInformation: http://calidad.info-grupo.com:8081/GeneraFicha3/PDF?articulo=100214608&lang=EN&un=0; Revision: n/a; Uniclass2015Code: Pr_35_93_96_19; Uniclass2015Title: Ceramic Tiles; Uniclass2015Version: Products v1.5; Version: 1
COBie - AccessibilityPerformance: See ProductInformation (Technical PDF); AssetType: Fixed; Category: Floors; CodePerformance: ISO-13006:2012; UNE-EN 14411:2012; Color: Beige; Constituents: Clays, feldespat and glaze; Description: Rectified Porcelain tiles, BOTEGA series from PORCELANOSA, BEIGE color and MATTE finish, 80x80 cm (11.2 mm thickness), group BIa, according to UNE-EN 14411, water absortion capacity E<=0.5%, flexural strength >40 N/mm², breaking strength with an average value of 3310 N (Min. 1300 N) and slip resistance R-10; DurationUnit: year; ExpectedLife: 50; Features: See ProductInformation (Technical PDF); Grade: First quality; Manufacturer: bim.gp@porcelanosagrupo.com; ModelNumber: 100214608; ModelReference: Bottega Caliza 80x80 cm; Name: CeramicTiles_Bottega_Caliza-800x800mm-100214608; NominalHeight: 11.2 mm; NominalLength: 800 mm; NominalWidth: 800 mm; ReplacementCost: n/a; Shape: Squared; Size: 800x800x11.2 mm; Sustainability Performance: See ProductInformation (Technical PDF); WarrantyDescription: Manufacturer warranty, applicable worldwide, with the pertinent national legislation prevailing in all cases and covering at least a 3-year period; all products must have been manufactured and fitted in accordance with the Fabricator's Manual, and have been used and cared for in accordance with the Guide to Use, Cleaning and Care available on the web page www.porcelanosa.com; WarrantyDurationLabor: n/a; WarrantyDurationParts: 3; WarrantyDurationUnit: year; WarrantyGuarantorLabor: n/a; WarrantyGuarantorParts: bim.gp@porcelanosagrupo.com; AssetIdentifier: n/a; BarCode: n/a; InstallationDate: 1900-12-31T23:59:59; TagNumber: n/a; WarrantyStartDate: 1900-12-31T23:59:59
Pset_CoveringCommon - IsExternal: yes; Reference: n/a; AcousticRating: n/a; Finish: Concrete, Tone Variations, Matte, Rectified; FireRating: A1; FlammabilityRating: Class 0; FragilityRating: n/a; Material: Ceramic; SurfaceSpreadOfFlame: Class 0; ThermalTransmittance: 205.357 kg/K/s3; TotalThickness: 11.2 mm
Pset_CoveringFlooring - HasAntiStaticSurface: no; HasNonSkidSurface: no
IFC - IfcExportType: FLOORING; IfcExportAS: IfcCovering
NBS_Data - HasSurfaceRoughness: no; AbrasionResistance: 6: Intense-External Access; BreakingStrength: Average Value: 3310 N (Min. 1300 N); ChemicalResistance: Class 'A' for swimming pools and cleaning products (resists attack); minimum Class 'B' for acids and bases; Collection: STON-KER; CreationDate: 2018/07; Dcof: n/a; FlexuralStrength: http://www.porcelanosa.com/product_finder/resources/pdf/inscol/files/GENCER-Fixing-Instructions.pdf; FrostResistance: >40 N/mm²; Group: Conforms to ISO 10545-9; MoistureExpansion: <(6.5x10e-6)/°K; RampTest: <0.1 mm/m; RecycledContent: R-10; Series: >6.5%; SlipResistanceValuePendulumTestValue: Botega; StainResistance: CL1; SurfaceQuality: Class 5: Easy cleaning with water; ThermalShockResistance: Without surface defects; UpecC: n/a; UpecE: n/a; UpecP: n/a; UpecU: Conforms to ISO 10545–12; WaterAbsorption: n/a

# IfcCovering: Floor:PGR_Porcelanosa_CeramicTiles_Bottega_Caliza_Ant.-596x596mm-100221473, Floor:PGR_Porcelanosa_CeramicTiles_Bottega_Caliza_Ant.-596x596mm-100221473:213347
In: Level 1
PredefinedType: FLOORING; Material: PGR_Porcelanosa_CeramicTiles_Bottega_Caliza_Ant.-596x596mm-100221473 10.3 mm
NBS_General - Author: Porcelanosa Group; BIMObjectName: PGR_Porcelanosa_CeramicTiles_Bottega_Caliza_Ant.-596x596mm-100221473; ManufacturerURL: www.porcelanosa.com; NBSDescription: Ceramic Tiles; NBSReference: 45-80-95/310; ProductInformation: http://calidad.info-grupo.com:8081/GeneraFicha3/PDF?articulo=100221473&lang=EN&un=0; Revision: n/a; Uniclass2015Code: Pr_35_93_96_19; Uniclass2015Title: Ceramic Tiles; Uniclass2015Version: Products v1.5; Version: 1
COBie - AccessibilityPerformance: See ProductInformation (Technical PDF); AssetType: Fixed; Category: Floors; CodePerformance: ISO-13006:2012; UNE-EN 14411:2012; Color: Beige; Constituents: Clays, feldespat and glaze; Description: Rectified Porcelain tiles, BOTEGA series from PORCELANOSA, BEIGE color and MATTE finish, 59.6x59.6 cm (10.3 mm thickness), group BIa, according to UNE-EN 14411, water absortion capacity E<=0.5%, flexural strength >40 N/mm², breaking strength with an average value of 3310 N (Min. 1300 N) and slip resistance R-13; DurationUnit: year; ExpectedLife: 50; Features: See ProductInformation (Technical PDF); Grade: First quality; Manufacturer: bim.gp@porcelanosagrupo.com; ModelNumber: 100221473; ModelReference: Bottega Caliza Ant. 59.6x59.6 cm; Name: CeramicTiles_Bottega_Caliza_Ant.-596x596mm-100221473; NominalHeight: 10.3 mm; NominalLength: 596 mm; NominalWidth: 596 mm; ReplacementCost: n/a; Shape: Squared; Size: 596x596x10.3 mm; Sustainability Performance: See ProductInformation (Technical PDF); WarrantyDescription: Manufacturer warranty, applicable worldwide, with the pertinent national legislation prevailing in all cases and covering at least a 3-year period; all products must have been manufactured and fitted in accordance with the Fabricator's Manual, and have been used and cared for in accordance with the Guide to Use, Cleaning and Care available on the web page www.porcelanosa.com; WarrantyDurationLabor: n/a; WarrantyDurationParts: 3; WarrantyDurationUnit: year; WarrantyGuarantorLabor: n/a; WarrantyGuarantorParts: bim.gp@porcelanosagrupo.com; AssetIdentifier: n/a; BarCode: n/a; InstallationDate: 1900-12-31T23:59:59; TagNumber: n/a; WarrantyStartDate: 1900-12-31T23:59:59
Pset_CoveringCommon - IsExternal: yes; Reference: n/a; AcousticRating: n/a; Finish: Concrete, Tone Variations, Matte, Non-Slip, Rectified; FireRating: A1; FlammabilityRating: Class 0; FragilityRating: n/a; Material: Ceramic; SurfaceSpreadOfFlame: Class 0; ThermalTransmittance: 223.301 kg/K/s3; TotalThickness: 10.3 mm
Pset_CoveringFlooring - HasAntiStaticSurface: no; HasNonSkidSurface: yes
IFC - IfcExportType: FLOORING; IfcExportAS: IfcCovering
NBS_Data - HasSurfaceRoughness: no; AbrasionResistance: 6: Intense-External Access; BreakingStrength: Average Value: 3310 N (Min. 1300 N); ChemicalResistance: Class 'A' for swimming pools and cleaning products (resists attack); minimum Class 'B' for acids and bases; Collection: STON-KER; CreationDate: 2018/07; Dcof: >0.42; FlexuralStrength: http://www.porcelanosa.com/product_finder/resources/pdf/inscol/files/GENCER-Fixing-Instructions.pdf; FrostResistance: >40 N/mm²; Group: Conforms to ISO 10545-9; MoistureExpansion: <(6.5x10e-6)/°K; RampTest: <0.1 mm/m; RecycledContent: R-13; Series: >6.5%; SlipResistanceValuePendulumTestValue: Botega; StainResistance: CL3; SurfaceQuality: Class 5: Easy cleaning with water; ThermalShockResistance: Without surface defects; UpecC: n/a; UpecE: n/a; UpecP: n/a; UpecU: Conforms to ISO 10545–12; WaterAbsorption: n/a

# IfcCovering: Floor:PGR_Porcelanosa_CeramicTiles_Bottega_Caliza_Ant.-800x800mm-100221502, Floor:PGR_Porcelanosa_CeramicTiles_Bottega_Caliza_Ant.-800x800mm-100221502:213357
In: Level 1
PredefinedType: FLOORING; Material: PGR_Porcelanosa_CeramicTiles_Bottega_Caliza_Ant.-800x800mm-100221502 11.2 mm
NBS_General - Author: Porcelanosa Group; BIMObjectName: PGR_Porcelanosa_CeramicTiles_Bottega_Caliza_Ant.-800x800mm-100221502; ManufacturerURL: www.porcelanosa.com; NBSDescription: Ceramic Tiles; NBSReference: 45-80-95/310; ProductInformation: http://calidad.info-grupo.com:8081/GeneraFicha3/PDF?articulo=100221502&lang=EN&un=0; Revision: n/a; Uniclass2015Code: Pr_35_93_96_19; Uniclass2015Title: Ceramic Tiles; Uniclass2015Version: Products v1.5; Version: 1
COBie - AccessibilityPerformance: See ProductInformation (Technical PDF); AssetType: Fixed; Category: Floors; CodePerformance: ISO-13006:2012; UNE-EN 14411:2012; Color: Beige; Constituents: Clays, feldespat and glaze; Description: Rectified Porcelain tiles, BOTEGA series from PORCELANOSA, BEIGE color and MATTE finish, 80x80 cm (11.2 mm thickness), group BIa, according to UNE-EN 14411, water absortion capacity E<=0.5%, flexural strength >40 N/mm², breaking strength with an average value of 3310 N (Min. 1300 N) and slip resistance R-13; DurationUnit: year; ExpectedLife: 50; Features: See ProductInformation (Technical PDF); Grade: First quality; Manufacturer: bim.gp@porcelanosagrupo.com; ModelNumber: 100221502; ModelReference: Bottega Caliza Ant. 80x80 cm; Name: CeramicTiles_Bottega_Caliza_Ant.-800x800mm-100221502; NominalHeight: 11.2 mm; NominalLength: 800 mm; NominalWidth: 800 mm; ReplacementCost: n/a; Shape: Squared; Size: 800x800x11.2 mm; Sustainability Performance: See ProductInformation (Technical PDF); WarrantyDescription: Manufacturer warranty, applicable worldwide, with the pertinent national legislation prevailing in all cases and covering at least a 3-year period; all products must have been manufactured and fitted in accordance with the Fabricator's Manual, and have been used and cared for in accordance with the Guide to Use, Cleaning and Care available on the web page www.porcelanosa.com; WarrantyDurationLabor: n/a; WarrantyDurationParts: 3; WarrantyDurationUnit: year; WarrantyGuarantorLabor: n/a; WarrantyGuarantorParts: bim.gp@porcelanosagrupo.com; AssetIdentifier: n/a; BarCode: n/a; InstallationDate: 1900-12-31T23:59:59; TagNumber: n/a; WarrantyStartDate: 1900-12-31T23:59:59
Pset_CoveringCommon - IsExternal: yes; Reference: n/a; AcousticRating: n/a; Finish: Concrete, Tone Variations, Matte, Non-Slip, Rectified; FireRating: A1; FlammabilityRating: Class 0; FragilityRating: n/a; Material: Ceramic; SurfaceSpreadOfFlame: Class 0; ThermalTransmittance: 205.357 kg/K/s3; TotalThickness: 11.2 mm
Pset_CoveringFlooring - HasAntiStaticSurface: no; HasNonSkidSurface: yes
IFC - IfcExportType: FLOORING; IfcExportAS: IfcCovering
NBS_Data - HasSurfaceRoughness: no; AbrasionResistance: 6: Intense-External Access; BreakingStrength: Average Value: 3310 N (Min. 1300 N); ChemicalResistance: Class 'A' for swimming pools and cleaning products (resists attack); minimum Class 'B' for acids and bases; Collection: STON-KER; CreationDate: 2018/07; Dcof: >0.42; FlexuralStrength: http://www.porcelanosa.com/product_finder/resources/pdf/inscol/files/GENCER-Fixing-Instructions.pdf; FrostResistance: >40 N/mm²; Group: Conforms to ISO 10545-9; MoistureExpansion: <(6.5x10e-6)/°K; RampTest: <0.1 mm/m; RecycledContent: R-13; Series: >6.5%; SlipResistanceValuePendulumTestValue: Botega; StainResistance: CL3; SurfaceQuality: Class 5: Easy cleaning with water; ThermalShockResistance: Without surface defects; UpecC: n/a; UpecE: n/a; UpecP: n/a; UpecU: Conforms to ISO 10545–12; WaterAbsorption: n/a

# IfcCovering: Floor:PGR_Porcelanosa_CeramicTiles_Bottega_Topo-1200x1200mm-100227119, Floor:PGR_Porcelanosa_CeramicTiles_Bottega_Topo-1200x1200mm-100227119:213417
In: Level 1
PredefinedType: FLOORING; Material: PGR_Porcelanosa_CeramicTiles_Bottega_Topo-1200x1200mm-100227119 12 mm
NBS_General - Author: Porcelanosa Group; BIMObjectName: PGR_Porcelanosa_CeramicTiles_Bottega_Topo-1200x1200mm-100227119; ManufacturerURL: www.porcelanosa.com; NBSDescription: Ceramic Tiles; NBSReference: 45-80-95/310; ProductInformation: http://calidad.info-grupo.com:8081/GeneraFicha3/PDF?articulo=100227119&lang=EN&un=0; Revision: n/a; Uniclass2015Code: Pr_35_93_96_19; Uniclass2015Title: Ceramic Tiles; Uniclass2015Version: Products v1.5; Version: 1
COBie - AccessibilityPerformance: See ProductInformation (Technical PDF); AssetType: Fixed; Category: Floors; CodePerformance: ISO-13006:2012; UNE-EN 14411:2012; Color: Marron; Constituents: Clays, feldespat and glaze; Description: Rectified Porcelain tiles, BOTEGA series from PORCELANOSA, MARRON color and MATTE finish, 120x120 cm (11.5 mm thickness), group BIa, according to UNE-EN 14411, water absortion capacity E<=0.5%, flexural strength >40 N/mm², breaking strength with an average value of 3310 N (Min. 1300 N) and slip resistance R-10; DurationUnit: year; ExpectedLife: 50; Features: See ProductInformation (Technical PDF); Grade: First quality; Manufacturer: bim.gp@porcelanosagrupo.com; ModelNumber: 100227119; ModelReference: Bottega Topo 120x120 cm; Name: CeramicTiles_Bottega_Topo-1200x1200mm-100227119; NominalHeight: 11.5 mm; NominalLength: 1200 mm; NominalWidth: 1200 mm; ReplacementCost: n/a; Shape: Squared; Size: 1200x1200x11.5 mm; Sustainability Performance: See ProductInformation (Technical PDF); WarrantyDescription: Manufacturer warranty, applicable worldwide, with the pertinent national legislation prevailing in all cases and covering at least a 3-year period; all products must have been manufactured and fitted in accordance with the Fabricator's Manual, and have been used and cared for in accordance with the Guide to Use, Cleaning and Care available on the web page www.porcelanosa.com; WarrantyDurationLabor: n/a; WarrantyDurationParts: 3; WarrantyDurationUnit: year; WarrantyGuarantorLabor: n/a; WarrantyGuarantorParts: bim.gp@porcelanosagrupo.com; AssetIdentifier: n/a; BarCode: n/a; InstallationDate: 1900-12-31T23:59:59; TagNumber: n/a; WarrantyStartDate: 1900-12-31T23:59:59
Pset_CoveringCommon - IsExternal: yes; Reference: n/a; AcousticRating: n/a; Finish: Concrete, Tone Variations, Matte, Rectified; FireRating: A1; FlammabilityRating: Class 0; FragilityRating: n/a; Material: Ceramic; SurfaceSpreadOfFlame: Class 0; ThermalTransmittance: 200 kg/K/s3; TotalThickness: 11.5 mm
Pset_CoveringFlooring - HasAntiStaticSurface: no; HasNonSkidSurface: no
IFC - IfcExportType: FLOORING; IfcExportAS: IfcCovering
NBS_Data - HasSurfaceRoughness: no; AbrasionResistance: 6: Intense-External Access; BreakingStrength: Average Value: 3310 N (Min. 1300 N); ChemicalResistance: Class 'A' for swimming pools and cleaning products (resists attack); minimum Class 'B' for acids and bases; Collection: Porcelanico Tecnico; CreationDate: 2018/07; Dcof: n/a; FlexuralStrength: http://www.porcelanosa.com/product_finder/resources/pdf/inscol/files/GENCER-Fixing-Instructions.pdf; FrostResistance: >40 N/mm²; Group: Conforms to ISO 10545-9; MoistureExpansion: <(6.5x10e-6)/°K; RampTest: <0.1 mm/m; RecycledContent: R-10; Series: >6.5%; SlipResistanceValuePendulumTestValue: Botega; StainResistance: CL1; SurfaceQuality: Class 5: Easy cleaning with water; ThermalShockResistance: Without surface defects; UpecC: n/a; UpecE: n/a; UpecP: n/a; UpecU: Conforms to ISO 10545–12; WaterAbsorption: n/a

# IfcCovering: Floor:PGR_Porcelanosa_CeramicTiles_Bottega_Topo-596x596mm-100214662, Floor:PGR_Porcelanosa_CeramicTiles_Bottega_Topo-596x596mm-100214662:213427
In: Level 1
PredefinedType: FLOORING; Material: PGR_Porcelanosa_CeramicTiles_Bottega_Topo-596x596mm-100214662 10.3 mm
NBS_General - Author: Porcelanosa Group; BIMObjectName: PGR_Porcelanosa_CeramicTiles_Bottega_Topo-596x596mm-100214662; ManufacturerURL: www.porcelanosa.com; NBSDescription: Ceramic Tiles; NBSReference: 45-80-95/310; ProductInformation: http://calidad.info-grupo.com:8081/GeneraFicha3/PDF?articulo=100214662&lang=EN&un=0; Revision: n/a; Uniclass2015Code: Pr_35_93_96_19; Uniclass2015Title: Ceramic Tiles; Uniclass2015Version: Products v1.5; Version: 1
COBie - AccessibilityPerformance: See ProductInformation (Technical PDF); AssetType: Fixed; Category: Floors; CodePerformance: ISO-13006:2012; UNE-EN 14411:2012; Color: MarrÓn; Constituents: Clays, feldespat and glaze; Description: Rectified Porcelain tiles, BOTEGA series from PORCELANOSA, MARRÓN color and MATTE finish, 59.6x59.6 cm (10.3 mm thickness), group BIa, according to UNE-EN 14411, water absortion capacity E<=0.5%, flexural strength >40 N/mm², breaking strength with an average value of 3310 N (Min. 1300 N) and slip resistance R-10; DurationUnit: year; ExpectedLife: 50; Features: See ProductInformation (Technical PDF); Grade: First quality; Manufacturer: bim.gp@porcelanosagrupo.com; ModelNumber: 100214662; ModelReference: Bottega Topo 59.6x59.6 cm; Name: CeramicTiles_Bottega_Topo-596x596mm-100214662; NominalHeight: 10.3 mm; NominalLength: 596 mm; NominalWidth: 596 mm; ReplacementCost: n/a; Shape: Squared; Size: 596x596x10.3 mm; Sustainability Performance: See ProductInformation (Technical PDF); WarrantyDescription: Manufacturer warranty, applicable worldwide, with the pertinent national legislation prevailing in all cases and covering at least a 3-year period; all products must have been manufactured and fitted in accordance with the Fabricator's Manual, and have been used and cared for in accordance with the Guide to Use, Cleaning and Care available on the web page www.porcelanosa.com; WarrantyDurationLabor: n/a; WarrantyDurationParts: 3; WarrantyDurationUnit: year; WarrantyGuarantorLabor: n/a; WarrantyGuarantorParts: bim.gp@porcelanosagrupo.com; AssetIdentifier: n/a; BarCode: n/a; InstallationDate: 1900-12-31T23:59:59; TagNumber: n/a; WarrantyStartDate: 1900-12-31T23:59:59
Pset_CoveringCommon - IsExternal: yes; Reference: n/a; AcousticRating: n/a; Finish: Concrete, Tone Variations, Matte, Rectified; FireRating: A1; FlammabilityRating: Class 0; FragilityRating: n/a; Material: Ceramic; SurfaceSpreadOfFlame: Class 0; ThermalTransmittance: 223.301 kg/K/s3; TotalThickness: 10.3 mm
Pset_CoveringFlooring - HasAntiStaticSurface: no; HasNonSkidSurface: no
IFC - IfcExportType: FLOORING; IfcExportAS: IfcCovering
NBS_Data - HasSurfaceRoughness: no; AbrasionResistance: 6: Intense-External Access; BreakingStrength: Average Value: 3310 N (Min. 1300 N); ChemicalResistance: Class 'A' for swimming pools and cleaning products (resists attack); minimum Class 'B' for acids and bases; Collection: STON-KER; CreationDate: 2018/07; Dcof: n/a; FlexuralStrength: http://www.porcelanosa.com/product_finder/resources/pdf/inscol/files/GENCER-Fixing-Instructions.pdf; FrostResistance: >40 N/mm²; Group: Conforms to ISO 10545-9; MoistureExpansion: <(6.5x10e-6)/°K; RampTest: <0.1 mm/m; RecycledContent: R-10; Series: >6.5%; SlipResistanceValuePendulumTestValue: Botega; StainResistance: CL1; SurfaceQuality: Class 5: Easy cleaning with water; ThermalShockResistance: Without surface defects; UpecC: n/a; UpecE: n/a; UpecP: n/a; UpecU: Conforms to ISO 10545–12; WaterAbsorption: n/a

# IfcCovering: Floor:PGR_Porcelanosa_CeramicTiles_Bottega_Topo-800x800mm-100214622, Floor:PGR_Porcelanosa_CeramicTiles_Bottega_Topo-800x800mm-100214622:213437
In: Level 1
PredefinedType: FLOORING; Material: PGR_Porcelanosa_CeramicTiles_Bottega_Topo-800x800mm-100214622 11.2 mm
NBS_General - Author: Porcelanosa Group; BIMObjectName: PGR_Porcelanosa_CeramicTiles_Bottega_Topo-800x800mm-100214622; ManufacturerURL: www.porcelanosa.com; NBSDescription: Ceramic Tiles; NBSReference: 45-80-95/310; ProductInformation: http://calidad.info-grupo.com:8081/GeneraFicha3/PDF?articulo=100214622&lang=EN&un=0; Revision: n/a; Uniclass2015Code: Pr_35_93_96_19; Uniclass2015Title: Ceramic Tiles; Uniclass2015Version: Products v1.5; Version: 1
COBie - AccessibilityPerformance: See ProductInformation (Technical PDF); AssetType: Fixed; Category: Floors; CodePerformance: ISO-13006:2012; UNE-EN 14411:2012; Color: MarrÓn; Constituents: Clays, feldespat and glaze; Description: Rectified Porcelain tiles, BOTEGA series from PORCELANOSA, MARRÓN color and MATTE finish, 80x80 cm (11.2 mm thickness), group BIa, according to UNE-EN 14411, water absortion capacity E<=0.5%, flexural strength >40 N/mm², breaking strength with an average value of 3310 N (Min. 1300 N) and slip resistance R-10; DurationUnit: year; ExpectedLife: 50; Features: See ProductInformation (Technical PDF); Grade: First quality; Manufacturer: bim.gp@porcelanosagrupo.com; ModelNumber: 100214622; ModelReference: Bottega Topo 80x80 cm; Name: CeramicTiles_Bottega_Topo-800x800mm-100214622; NominalHeight: 11.2 mm; NominalLength: 800 mm; NominalWidth: 800 mm; ReplacementCost: n/a; Shape: Squared; Size: 800x800x11.2 mm; Sustainability Performance: See ProductInformation (Technical PDF); WarrantyDescription: Manufacturer warranty, applicable worldwide, with the pertinent national legislation prevailing in all cases and covering at least a 3-year period; all products must have been manufactured and fitted in accordance with the Fabricator's Manual, and have been used and cared for in accordance with the Guide to Use, Cleaning and Care available on the web page www.porcelanosa.com; WarrantyDurationLabor: n/a; WarrantyDurationParts: 3; WarrantyDurationUnit: year; WarrantyGuarantorLabor: n/a; WarrantyGuarantorParts: bim.gp@porcelanosagrupo.com; AssetIdentifier: n/a; BarCode: n/a; InstallationDate: 1900-12-31T23:59:59; TagNumber: n/a; WarrantyStartDate: 1900-12-31T23:59:59
Pset_CoveringCommon - IsExternal: yes; Reference: n/a; AcousticRating: n/a; Finish: Concrete, Tone Variations, Matte, Rectified; FireRating: A1; FlammabilityRating: Class 0; FragilityRating: n/a; Material: Ceramic; SurfaceSpreadOfFlame: Class 0; ThermalTransmittance: 205.357 kg/K/s3; TotalThickness: 11.2 mm
Pset_CoveringFlooring - HasAntiStaticSurface: no; HasNonSkidSurface: no
IFC - IfcExportType: FLOORING; IfcExportAS: IfcCovering
NBS_Data - HasSurfaceRoughness: no; AbrasionResistance: 6: Intense-External Access; BreakingStrength: Average Value: 3310 N (Min. 1300 N); ChemicalResistance: Class 'A' for swimming pools and cleaning products (resists attack); minimum Class 'B' for acids and bases; Collection: STON-KER; CreationDate: 2018/07; Dcof: n/a; FlexuralStrength: http://www.porcelanosa.com/product_finder/resources/pdf/inscol/files/GENCER-Fixing-Instructions.pdf; FrostResistance: >40 N/mm²; Group: Conforms to ISO 10545-9; MoistureExpansion: <(6.5x10e-6)/°K; RampTest: <0.1 mm/m; RecycledContent: R-10; Series: >6.5%; SlipResistanceValuePendulumTestValue: Botega; StainResistance: CL1; SurfaceQuality: Class 5: Easy cleaning with water; ThermalShockResistance: Without surface defects; UpecC: n/a; UpecE: n/a; UpecP: n/a; UpecU: Conforms to ISO 10545–12; WaterAbsorption: n/a

# IfcCovering: Floor:PGR_Porcelanosa_CeramicTiles_Bottega_Topo_Ant.-596x596mm-100221449, Floor:PGR_Porcelanosa_CeramicTiles_Bottega_Topo_Ant.-596x596mm-100221449:213447
In: Level 1
PredefinedType: FLOORING; Material: PGR_Porcelanosa_CeramicTiles_Bottega_Topo_Ant.-596x596mm-100221449 10.3 mm
NBS_General - Author: Porcelanosa Group; BIMObjectName: PGR_Porcelanosa_CeramicTiles_Bottega_Topo_Ant.-596x596mm-100221449; ManufacturerURL: www.porcelanosa.com; NBSDescription: Ceramic Tiles; NBSReference: 45-80-95/310; ProductInformation: http://calidad.info-grupo.com:8081/GeneraFicha3/PDF?articulo=100221449&lang=EN&un=0; Revision: n/a; Uniclass2015Code: Pr_35_93_96_19; Uniclass2015Title: Ceramic Tiles; Uniclass2015Version: Products v1.5; Version: 1
COBie - AccessibilityPerformance: See ProductInformation (Technical PDF); AssetType: Fixed; Category: Floors; CodePerformance: ISO-13006:2012; UNE-EN 14411:2012; Color: MarrÓn; Constituents: Clays, feldespat and glaze; Description: Rectified Porcelain tiles, BOTEGA series from PORCELANOSA, MARRÓN color and MATTE finish, 59.6x59.6 cm (10.3 mm thickness), group BIa, according to UNE-EN 14411, water absortion capacity E<=0.5%, flexural strength >40 N/mm², breaking strength with an average value of 3310 N (Min. 1300 N) and slip resistance R-13; DurationUnit: year; ExpectedLife: 50; Features: See ProductInformation (Technical PDF); Grade: First quality; Manufacturer: bim.gp@porcelanosagrupo.com; ModelNumber: 100221449; ModelReference: Bottega Topo Ant. 59.6x59.6 cm; Name: CeramicTiles_Bottega_Topo_Ant.-596x596mm-100221449; NominalHeight: 10.3 mm; NominalLength: 596 mm; NominalWidth: 596 mm; ReplacementCost: n/a; Shape: Squared; Size: 596x596x10.3 mm; Sustainability Performance: See ProductInformation (Technical PDF); WarrantyDescription: Manufacturer warranty, applicable worldwide, with the pertinent national legislation prevailing in all cases and covering at least a 3-year period; all products must have been manufactured and fitted in accordance with the Fabricator's Manual, and have been used and cared for in accordance with the Guide to Use, Cleaning and Care available on the web page www.porcelanosa.com; WarrantyDurationLabor: n/a; WarrantyDurationParts: 3; WarrantyDurationUnit: year; WarrantyGuarantorLabor: n/a; WarrantyGuarantorParts: bim.gp@porcelanosagrupo.com; AssetIdentifier: n/a; BarCode: n/a; InstallationDate: 1900-12-31T23:59:59; TagNumber: n/a; WarrantyStartDate: 1900-12-31T23:59:59
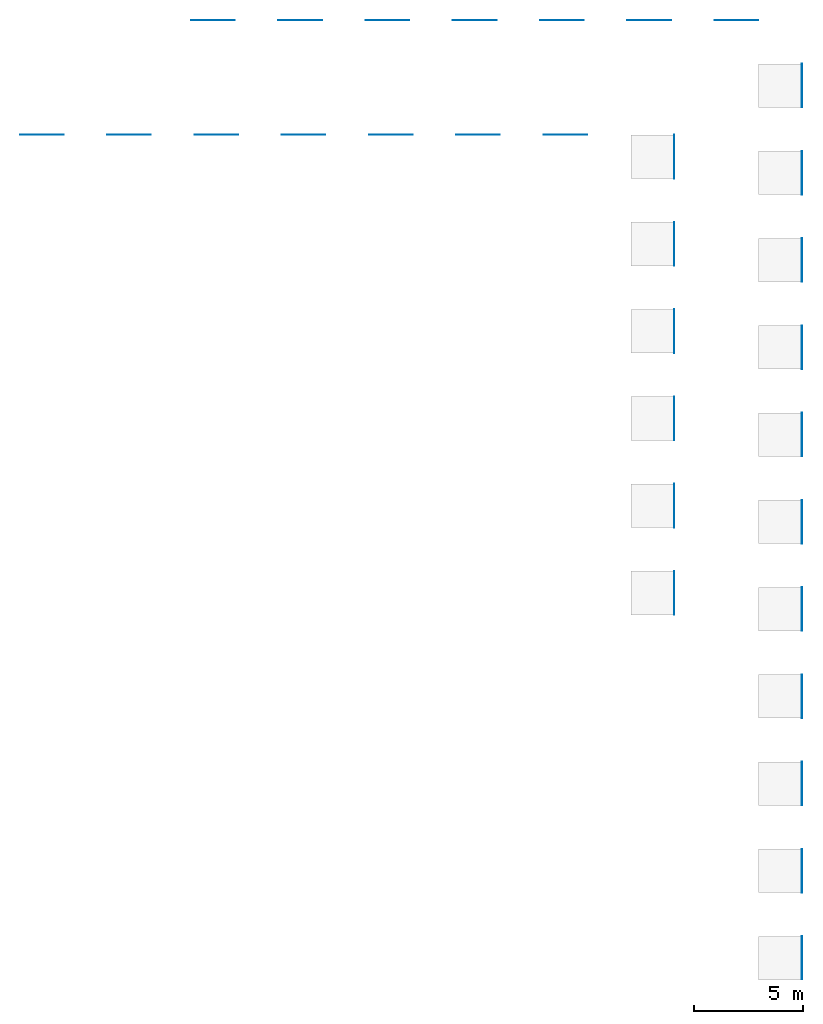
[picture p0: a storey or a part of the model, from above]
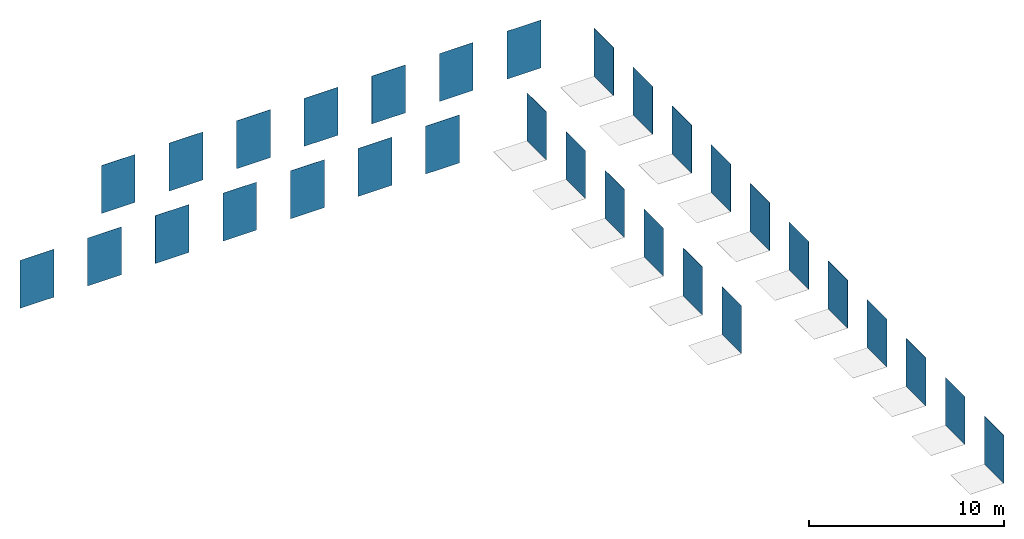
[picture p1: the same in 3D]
Properties of the parts of a building model (IFC2X3), part 2 of 3

# IfcCovering: Floor:PGR_Porcelanosa_CeramicTiles_Bottega_Topo_Ant.-596x596mm-100221449, Floor:PGR_Porcelanosa_CeramicTiles_Bottega_Topo_Ant.-596x596mm-100221449:213447
Pset_CoveringCommon - IsExternal: yes; Reference: n/a; AcousticRating: n/a; Finish: Concrete, Tone Variations, Matte, Non-Slip, Rectified; FireRating: A1; FlammabilityRating: Class 0; FragilityRating: n/a; Material: Ceramic; SurfaceSpreadOfFlame: Class 0; ThermalTransmittance: 223.301 kg/K/s3; TotalThickness: 10.3 mm
Pset_CoveringFlooring - HasAntiStaticSurface: no; HasNonSkidSurface: yes
IFC - IfcExportType: FLOORING; IfcExportAS: IfcCovering
NBS_Data - HasSurfaceRoughness: no; AbrasionResistance: 6: Intense-External Access; BreakingStrength: Average Value: 3310 N (Min. 1300 N); ChemicalResistance: Class 'A' for swimming pools and cleaning products (resists attack); minimum Class 'B' for acids and bases; Collection: STON-KER; CreationDate: 2018/07; Dcof: >0.42; FlexuralStrength: http://www.porcelanosa.com/product_finder/resources/pdf/inscol/files/GENCER-Fixing-Instructions.pdf; FrostResistance: >40 N/mm²; Group: Conforms to ISO 10545-9; MoistureExpansion: <(6.5x10e-6)/°K; RampTest: <0.1 mm/m; RecycledContent: R-13; Series: >6.5%; SlipResistanceValuePendulumTestValue: Botega; StainResistance: CL3; SurfaceQuality: Class 5: Easy cleaning with water; ThermalShockResistance: Without surface defects; UpecC: n/a; UpecE: n/a; UpecP: n/a; UpecU: Conforms to ISO 10545–12; WaterAbsorption: n/a

# IfcCovering: Floor:PGR_Porcelanosa_CeramicTiles_Bottega_Topo_Ant.-800x800mm-100221465, Floor:PGR_Porcelanosa_CeramicTiles_Bottega_Topo_Ant.-800x800mm-100221465:213457
In: Level 1
PredefinedType: FLOORING; Material: PGR_Porcelanosa_CeramicTiles_Bottega_Topo_Ant.-800x800mm-100221465 11.2 mm
NBS_General - Author: Porcelanosa Group; BIMObjectName: PGR_Porcelanosa_CeramicTiles_Bottega_Topo_Ant.-800x800mm-100221465; ManufacturerURL: www.porcelanosa.com; NBSDescription: Ceramic Tiles; NBSReference: 45-80-95/310; ProductInformation: http://calidad.info-grupo.com:8081/GeneraFicha3/PDF?articulo=100221465&lang=EN&un=0; Revision: n/a; Uniclass2015Code: Pr_35_93_96_19; Uniclass2015Title: Ceramic Tiles; Uniclass2015Version: Products v1.5; Version: 1
COBie - AccessibilityPerformance: See ProductInformation (Technical PDF); AssetType: Fixed; Category: Floors; CodePerformance: ISO-13006:2012; UNE-EN 14411:2012; Color: MarrÓn; Constituents: Clays, feldespat and glaze; Description: Rectified Porcelain tiles, BOTEGA series from PORCELANOSA, MARRÓN color and MATTE finish, 80x80 cm (11.2 mm thickness), group BIa, according to UNE-EN 14411, water absortion capacity E<=0.5%, flexural strength >40 N/mm², breaking strength with an average value of 3310 N (Min. 1300 N) and slip resistance R-13; DurationUnit: year; ExpectedLife: 50; Features: See ProductInformation (Technical PDF); Grade: First quality; Manufacturer: bim.gp@porcelanosagrupo.com; ModelNumber: 100221465; ModelReference: Bottega Topo Ant. 80x80 cm; Name: CeramicTiles_Bottega_Topo_Ant.-800x800mm-100221465; NominalHeight: 11.2 mm; NominalLength: 800 mm; NominalWidth: 800 mm; ReplacementCost: n/a; Shape: Squared; Size: 800x800x11.2 mm; Sustainability Performance: See ProductInformation (Technical PDF); WarrantyDescription: Manufacturer warranty, applicable worldwide, with the pertinent national legislation prevailing in all cases and covering at least a 3-year period; all products must have been manufactured and fitted in accordance with the Fabricator's Manual, and have been used and cared for in accordance with the Guide to Use, Cleaning and Care available on the web page www.porcelanosa.com; WarrantyDurationLabor: n/a; WarrantyDurationParts: 3; WarrantyDurationUnit: year; WarrantyGuarantorLabor: n/a; WarrantyGuarantorParts: bim.gp@porcelanosagrupo.com; AssetIdentifier: n/a; BarCode: n/a; InstallationDate: 1900-12-31T23:59:59; TagNumber: n/a; WarrantyStartDate: 1900-12-31T23:59:59
Pset_CoveringCommon - IsExternal: yes; Reference: n/a; AcousticRating: n/a; Finish: Concrete, Tone Variations, Matte, Non-Slip, Rectified; FireRating: A1; FlammabilityRating: Class 0; FragilityRating: n/a; Material: Ceramic; SurfaceSpreadOfFlame: Class 0; ThermalTransmittance: 205.357 kg/K/s3; TotalThickness: 11.2 mm
Pset_CoveringFlooring - HasAntiStaticSurface: no; HasNonSkidSurface: yes
IFC - IfcExportType: FLOORING; IfcExportAS: IfcCovering
NBS_Data - HasSurfaceRoughness: no; AbrasionResistance: 6: Intense-External Access; BreakingStrength: Average Value: 3310 N (Min. 1300 N); ChemicalResistance: Class 'A' for swimming pools and cleaning products (resists attack); minimum Class 'B' for acids and bases; Collection: STON-KER; CreationDate: 2018/07; Dcof: >0.42; FlexuralStrength: http://www.porcelanosa.com/product_finder/resources/pdf/inscol/files/GENCER-Fixing-Instructions.pdf; FrostResistance: >40 N/mm²; Group: Conforms to ISO 10545-9; MoistureExpansion: <(6.5x10e-6)/°K; RampTest: <0.1 mm/m; RecycledContent: R-13; Series: >6.5%; SlipResistanceValuePendulumTestValue: Botega; StainResistance: CL3; SurfaceQuality: Class 5: Easy cleaning with water; ThermalShockResistance: Without surface defects; UpecC: n/a; UpecE: n/a; UpecP: n/a; UpecU: Conforms to ISO 10545–12; WaterAbsorption: n/a

# IfcWallStandardCase: Basic Wall:PGR_Porcelanosa_CeramicTiles_Bottega_Acero-1200x1200mm-100227107, Basic Wall:PGR_Porcelanosa_CeramicTiles_Bottega_Acero-1200x1200mm-100227107:202329
In: Level 1
Type - PredefinedType: STANDARD; Material: PGR_Porcelanosa_CeramicTiles_Bottega_Acero-1200x1200mm-100227107 12 mm
Type - NBS_General - Author: Porcelanosa Group; BIMObjectName: PGR_Porcelanosa_CeramicTiles_Bottega_Acero-1200x1200mm-100227107; ManufacturerURL: www.porcelanosa.com; NBSDescription: Ceramic Tiles; NBSReference: 45-80-95/310; ProductInformation: http://calidad.info-grupo.com:8081/GeneraFicha3/PDF?articulo=100227107&lang=EN&un=0; Revision: n/a; Uniclass2015Code: Pr_35_93_96_19; Uniclass2015Title: Ceramic Tiles; Uniclass2015Version: Products v1.5; Version: 1
Type - COBie - AccessibilityPerformance: See ProductInformation (Technical PDF); AssetType: Fixed; Category: Pr_35_93_96_19:Ceramic Tiles; CodePerformance: ISO-13006:2012; UNE-EN 14411:2012; Color: Gris; Constituents: Clays, feldespat and glaze; Description: Rectified Porcelain tiles, BOTEGA series from PORCELANOSA, GRIS color and MATTE finish, 120x120 cm (11.5 mm thickness), group BIa, according to UNE-EN 14411, water absortion capacity E<=0.5%, flexural strength >40 N/mm², breaking strength with an average value of 3310 N (Min. 1300 N) and slip resistance R-10; DurationUnit: year; ExpectedLife: 50; Features: See ProductInformation (Technical PDF); Grade: First quality; Manufacturer: bim.gp@porcelanosagrupo.com; ModelNumber: 100227107; ModelReference: Bottega Acero 120x120 cm; Name: CeramicTiles_Bottega_Acero-1200x1200mm-100227107; NominalHeight: 11.5 mm; NominalLength: 1200 mm; NominalWidth: 1200 mm; ReplacementCost: n/a; Shape: Squared; Size: 1200x1200x11.5 mm; Sustainability Performance: See ProductInformation (Technical PDF); WarrantyDescription: Manufacturer warranty, applicable worldwide, with the pertinent national legislation prevailing in all cases and covering at least a 3-year period; all products must have been manufactured and fitted in accordance with the Fabricator's Manual, and have been used and cared for in accordance with the Guide to Use, Cleaning and Care available on the web page www.porcelanosa.com; WarrantyDurationLabor: n/a; WarrantyDurationParts: 3; WarrantyDurationUnit: year; WarrantyGuarantorLabor: n/a; WarrantyGuarantorParts: bim.gp@porcelanosagrupo.com
Type - Pset_CoveringCommon - IsExternal: yes; Reference: n/a; AcousticRating: n/a; Finish: Concrete, Tone Variations, Matte, Rectified; FireRating: A1; FlammabilityRating: Class 0; FragilityRating: n/a; Material: Ceramic; SurfaceSpreadOfFlame: Class 0; ThermalTransmittance: 200 kg/K/s3; TotalThickness: 11.5 mm
Type - IFC - IfcExportType: FLOORING; IfcExportAS: IfcCovering
Type - NBS_Data - HasSurfaceRoughness: no; AbrasionResistance: 6: Intense-External Access; BreakingStrength: Average Value: 3310 N (Min. 1300 N); ChemicalResistance: Class 'A' for swimming pools and cleaning products (resists attack); minimum Class 'B' for acids and bases; Collection: Porcelanico Tecnico; CreationDate: 2018/07; Dcof: n/a; FlexuralStrength: >40 N/mm²; FrostResistance: Conforms to ISO 10545-9; Group: BIa; MoistureExpansion: <0.1 mm/m; RampTest: R-10; RecycledContent: >6.5%; Series: Botega; SlipResistanceValuePendulumTestValue: CL1; StainResistance: Class 5: Easy cleaning with water; SurfaceQuality: Without surface defects; ThermalShockResistance: Conforms to ISO 10545–12; UpecC: n/a; UpecE: n/a; UpecP: n/a; UpecU: n/a; WaterAbsorption: E<=0.5%
COBie - AssetIdentifier: n/a; BarCode: n/a; InstallationDate: 1900-12-31T23:59:59; TagNumber: n/a; WarrantyStartDate: 1900-12-31T23:59:59

# IfcWallStandardCase: Basic Wall:PGR_Porcelanosa_CeramicTiles_Bottega_Acero-316x592mm-100225102, Basic Wall:PGR_Porcelanosa_CeramicTiles_Bottega_Acero-316x592mm-100225102:218952
In: Level 1
Type - PredefinedType: STANDARD; Material: PGR_Porcelanosa_CeramicTiles_Bottega_Acero-316x592mm-100225102 11.3 mm
Type - NBS_General - Author: Porcelanosa Group; BIMObjectName: PGR_Porcelanosa_CeramicTiles_Bottega_Acero-316x592mm-100225102; ManufacturerURL: www.porcelanosa.com; NBSDescription: Ceramic Tiles; NBSReference: 45-80-95/310; ProductInformation: http://calidad.info-grupo.com:8081/GeneraFicha3/PDF?articulo=100225102&lang=EN&un=0; Revision: n/a; Uniclass2015Code: Pr_35_93_96_19; Uniclass2015Title: Ceramic Tiles; Uniclass2015Version: Products v1.5; Version: 1
Type - COBie - AccessibilityPerformance: See ProductInformation (Technical PDF); AssetType: Fixed; Category: Walls; CodePerformance: ISO-13006:2012; UNE-EN 14411:2012; Color: Gris; Constituents: Clays, feldespat and glaze; Description: Monoporous, BOTEGA series from PORCELANOSA, GRIS color and MATTE finish, 31.6x59.2 cm (8.7 mm thickness), group BIII, according to UNE-EN 14411, water absortion capacity 10%<=E<=20%, flexural strength >23 N/mm² and breaking strength with an average value of 1337 N (Min. 600 N); DurationUnit: year; ExpectedLife: 50; Features: See ProductInformation (Technical PDF); Grade: First quality; Manufacturer: bim.gp@porcelanosagrupo.com; ModelNumber: 100225102; ModelReference: Bottega Acero 31.6x59.2 cm; Name: CeramicTiles_Bottega_Acero-316x592mm-100225102; NominalHeight: 8.7 mm; NominalLength: 592 mm; NominalWidth: 316 mm; ReplacementCost: n/a; Shape: Rectangular; Size: 316x592x8.7 mm; Sustainability Performance: See ProductInformation (Technical PDF); WarrantyDescription: Manufacturer warranty, applicable worldwide, with the pertinent national legislation prevailing in all cases and covering at least a 3-year period; all products must have been manufactured and fitted in accordance with the Fabricator's Manual, and have been used and cared for in accordance with the Guide to Use, Cleaning and Care available on the web page www.porcelanosa.com; WarrantyDurationLabor: n/a; WarrantyDurationParts: 3; WarrantyDurationUnit: year; WarrantyGuarantorLabor: n/a; WarrantyGuarantorParts: bim.gp@porcelanosagrupo.com
Type - Pset_CoveringCommon - Reference: n/a; IsExternal: no; AcousticRating: n/a; Finish: Concrete, Tone Variations, Matte; FireRating: A1; FlammabilityRating: Class 0; FragilityRating: n/a; Material: Ceramic; SurfaceSpreadOfFlame: Class 0; ThermalTransmittance: 264.368 kg/K/s3; TotalThickness: 8.7 mm
Type - IFC - IfcExportType: CLADDING; IfcExportAS: IfcCovering
Type - NBS_Data - HasSurfaceRoughness: no; AbrasionResistance: 1: Wall Tiles; BreakingStrength: Average Value: 1337 N (Min. 600 N); ChemicalResistance: Class 'A' for swimming pools and cleaning products (resists attack); minimum Class 'B' for acids and bases; Collection: Revestimiento Ceramico; CreationDate: 2018/07; Dcof: n/a; FlexuralStrength: >23 N/mm²; FrostResistance: n/a; Group: BIII; MoistureExpansion: <0.1 mm/m; RampTest: n/a; RecycledContent: >18%; Series: Botega; SlipResistanceValuePendulumTestValue: n/a; StainResistance: Class 5: Easy cleaning with water; SurfaceQuality: Without surface defects; ThermalShockResistance: Conforms to ISO 10545–12; UpecC: n/a; UpecE: n/a; UpecP: n/a; UpecU: n/a; WaterAbsorption: 10%<=E<=20%
COBie - AssetIdentifier: n/a; BarCode: n/a; InstallationDate: 1900-12-31T23:59:59; TagNumber: n/a; WarrantyStartDate: 1900-12-31T23:59:59

# IfcWallStandardCase: Basic Wall:PGR_Porcelanosa_CeramicTiles_Bottega_Acero-316x900mm-100215162, Basic Wall:PGR_Porcelanosa_CeramicTiles_Bottega_Acero-316x900mm-100215162:213465
In: Level 1
Type - PredefinedType: STANDARD; Material: PGR_Porcelanosa_CeramicTiles_Bottega_Acero-316x900mm-100215162 9 mm
Type - NBS_General - Author: Porcelanosa Group; BIMObjectName: PGR_Porcelanosa_CeramicTiles_Bottega_Acero-316x900mm-100215162; ManufacturerURL: www.porcelanosa.com; NBSDescription: Ceramic Tiles; NBSReference: 45-80-95/310; ProductInformation: http://calidad.info-grupo.com:8081/GeneraFicha3/PDF?articulo=100215162&lang=EN&un=0; Revision: n/a; Uniclass2015Code: Pr_35_93_96_19; Uniclass2015Title: Ceramic Tiles; Uniclass2015Version: Products v1.5; Version: 1
Type - COBie - AccessibilityPerformance: See ProductInformation (Technical PDF); AssetType: Fixed; Category: Walls; CodePerformance: ISO-13006:2012; UNE-EN 14411:2012; Color: Gris; Constituents: Clays, feldespat and glaze; Description: Rectified Monoporous, VENETO series from PORCELANOSA, GRIS color and MATTE finish, 31.6x90 cm (9.2 mm thickness), group BIII, according to UNE-EN 14411, water absortion capacity 10%<=E<=20%, flexural strength >23 N/mm², breaking strength with an average value of 1337 N (Min. 600 N) and slip resistance -; DurationUnit: year; ExpectedLife: 50; Features: See ProductInformation (Technical PDF); Grade: First quality; Manufacturer: bim.gp@porcelanosagrupo.com; ModelNumber: 100215162; ModelReference: Bottega Acero 31.6x90 cm; Name: CeramicTiles_Bottega_Acero-316x900mm-100215162; NominalHeight: 9.2 mm; NominalLength: 900 mm; NominalWidth: 316 mm; ReplacementCost: n/a; Shape: Rectangular; Size: 316x900x9.2 mm; Sustainability Performance: See ProductInformation (Technical PDF); WarrantyDescription: Manufacturer warranty, applicable worldwide, with the pertinent national legislation prevailing in all cases and covering at least a 3-year period; all products must have been manufactured and fitted in accordance with the Fabricator's Manual, and have been used and cared for in accordance with the Guide to Use, Cleaning and Care available on the web page www.porcelanosa.com; WarrantyDurationLabor: n/a; WarrantyDurationParts: 3; WarrantyDurationUnit: year; WarrantyGuarantorLabor: n/a; WarrantyGuarantorParts: bim.gp@porcelanosagrupo.com
Type - Pset_CoveringCommon - Reference: n/a; AcousticRating: n/a; Finish: Concrete, Tone Variations, Matte, Rectified; FireRating: A1; FlammabilityRating: Class 0; FragilityRating: n/a; IsExternal: no; Material: Ceramic; SurfaceSpreadOfFlame: Class 0; ThermalTransmittance: 250 kg/K/s3; TotalThickness: 9.2 mm
Type - IFC - IfcExportType: CLADDING; IfcExportAS: IfcCovering
Type - NBS_Data - HasSurfaceRoughness: no; AbrasionResistance: 1: Wall Tiles; BreakingStrength: Average Value: 1337 N (Min. 600 N); ChemicalResistance: Class 'A' for swimming pools and cleaning products (resists attack); minimum Class 'B' for acids and bases; Collection: Revestimiento Ceramico Rectificado; CreationDate: 2018/07; Dcof: n/a; FlexuralStrength: >23 N/mm²; FrostResistance: n/a; Group: BIII; MoistureExpansion: <0.1 mm/m; RampTest: -; RecycledContent: >18%; Series: Veneto; SlipResistanceValuePendulumTestValue: n/a; StainResistance: Class 5: Easy cleaning with water; SurfaceQuality: Without surface defects; ThermalShockResistance: Conforms to ISO 10545–12; UpecC: n/a; UpecE: n/a; UpecP: n/a; UpecU: n/a; WaterAbsorption: 10%<=E<=20%
COBie - AssetIdentifier: n/a; BarCode: n/a; InstallationDate: 1900-12-31T23:59:59; TagNumber: n/a; WarrantyStartDate: 1900-12-31T23:59:59

# IfcWallStandardCase: Basic Wall:PGR_Porcelanosa_CeramicTiles_Bottega_Acero-443x443mm-100225055, Basic Wall:PGR_Porcelanosa_CeramicTiles_Bottega_Acero-443x443mm-100225055:213382
In: Level 1
Type - PredefinedType: STANDARD; Material: PGR_Porcelanosa_CeramicTiles_Bottega_Acero-443x443mm-100225055 10.3 mm
Type - NBS_General - Author: Porcelanosa Group; BIMObjectName: PGR_Porcelanosa_CeramicTiles_Bottega_Acero-443x443mm-100225055; ManufacturerURL: www.porcelanosa.com; NBSDescription: Ceramic Tiles; NBSReference: 45-80-95/310; ProductInformation: http://calidad.info-grupo.com:8081/GeneraFicha3/PDF?articulo=100225055&lang=EN&un=0; Revision: n/a; Uniclass2015Code: Pr_35_93_96_19; Uniclass2015Title: Ceramic Tiles; Uniclass2015Version: Products v1.5; Version: 1
Type - COBie - AccessibilityPerformance: See ProductInformation (Technical PDF); AssetType: Fixed; Category: Pr_35_93_96_19:Ceramic Tiles; CodePerformance: ISO-13006:2012; UNE-EN 14411:2012; Color: Gris; Constituents: Clays, feldespat and glaze; Description: Porcelain tiles, BOTEGA series from PORCELANOSA, GRIS color and MATTE finish, 44.3x44.3 cm (10 mm thickness), group BIa, according to UNE-EN 14411, water absortion capacity E<=0.5%, flexural strength >40 N/mm², breaking strength with an average value of 3310 N (Min. 1300 N) and slip resistance R-10; DurationUnit: year; ExpectedLife: 50; Features: See ProductInformation (Technical PDF); Grade: First quality; Manufacturer: bim.gp@porcelanosagrupo.com; ModelNumber: 100225055; ModelReference: Bottega Acero 44.3x44.3 cm; Name: CeramicTiles_Bottega_Acero-443x443mm-100225055; NominalHeight: 10 mm; NominalLength: 443 mm; NominalWidth: 443 mm; ReplacementCost: n/a; Shape: Squared; Size: 443x443x10 mm; Sustainability Performance: See ProductInformation (Technical PDF); WarrantyDescription: Manufacturer warranty, applicable worldwide, with the pertinent national legislation prevailing in all cases and covering at least a 3-year period; all products must have been manufactured and fitted in accordance with the Fabricator's Manual, and have been used and cared for in accordance with the Guide to Use, Cleaning and Care available on the web page www.porcelanosa.com; WarrantyDurationLabor: n/a; WarrantyDurationParts: 3; WarrantyDurationUnit: year; WarrantyGuarantorLabor: n/a; WarrantyGuarantorParts: bim.gp@porcelanosagrupo.com
Type - Pset_CoveringCommon - IsExternal: yes; Reference: n/a; AcousticRating: n/a; Finish: Concrete, Tone Variations, Matte; FireRating: A1; FlammabilityRating: Class 0; FragilityRating: n/a; Material: Ceramic; SurfaceSpreadOfFlame: Class 0; ThermalTransmittance: 230 kg/K/s3; TotalThickness: 10 mm
Type - IFC - IfcExportType: FLOORING; IfcExportAS: IfcCovering
Type - NBS_Data - HasSurfaceRoughness: no; AbrasionResistance: 6: Intense-External Access; BreakingStrength: Average Value: 3310 N (Min. 1300 N); ChemicalResistance: Class 'A' for swimming pools and cleaning products (resists attack); minimum Class 'B' for acids and bases; Collection: Porcelanico; CreationDate: 2018/07; Dcof: n/a; FlexuralStrength: >40 N/mm²; FrostResistance: Conforms to ISO 10545-9; Group: BIa; MoistureExpansion: <0.1 mm/m; RampTest: R-10; RecycledContent: >6.5%; Series: Botega; SlipResistanceValuePendulumTestValue: CL1; StainResistance: Class 5: Easy cleaning with water; SurfaceQuality: Without surface defects; ThermalShockResistance: Conforms to ISO 10545–12; UpecC: n/a; UpecE: n/a; UpecP: n/a; UpecU: n/a; WaterAbsorption: E<=0.5%
COBie - AssetIdentifier: n/a; BarCode: n/a; InstallationDate: 1900-12-31T23:59:59; TagNumber: n/a; WarrantyStartDate: 1900-12-31T23:59:59

# IfcWallStandardCase: Basic Wall:PGR_Porcelanosa_CeramicTiles_Bottega_Acero-450x1200mm-100214606, Basic Wall:PGR_Porcelanosa_CeramicTiles_Bottega_Acero-450x1200mm-100214606:213466
In: Level 1
Type - PredefinedType: STANDARD; Material: PGR_Porcelanosa_CeramicTiles_Bottega_Acero-450x1200mm-100214606 10.1 mm
Type - NBS_General - Author: Porcelanosa Group; BIMObjectName: PGR_Porcelanosa_CeramicTiles_Bottega_Acero-450x1200mm-100214606; ManufacturerURL: www.porcelanosa.com; NBSDescription: Ceramic Tiles; NBSReference: 45-80-95/310; ProductInformation: http://calidad.info-grupo.com:8081/GeneraFicha3/PDF?articulo=100214606&lang=EN&un=0; Revision: n/a; Uniclass2015Code: Pr_35_93_96_19; Uniclass2015Title: Ceramic Tiles; Uniclass2015Version: Products v1.5; Version: 1
Type - COBie - AccessibilityPerformance: See ProductInformation (Technical PDF); AssetType: Fixed; Category: Pr_35_93_96_19:Ceramic Tiles; CodePerformance: ISO-13006:2012; UNE-EN 14411:2012; Color: Gris; Constituents: Clays, feldespat and glaze; Description: Rectified Monoporous, BOTEGA series from PORCELANOSA, GRIS color and MATTE finish, 45x120 cm (10 mm thickness), group BIII, according to UNE-EN 14411, water absortion capacity 10%<=E<=20%, flexural strength >23 N/mm², breaking strength with an average value of 1337 N (Min. 600 N) and slip resistance R-10; DurationUnit: year; ExpectedLife: 50; Features: See ProductInformation (Technical PDF); Grade: First quality; Manufacturer: bim.gp@porcelanosagrupo.com; ModelNumber: 100214606; ModelReference: Bottega Acero 45x120 cm; Name: CeramicTiles_Bottega_Acero-450x1200mm-100214606; NominalHeight: 10 mm; NominalLength: 1200 mm; NominalWidth: 450 mm; ReplacementCost: n/a; Shape: Rectangular; Size: 450x1200x10 mm; Sustainability Performance: See ProductInformation (Technical PDF); WarrantyDescription: Manufacturer warranty, applicable worldwide, with the pertinent national legislation prevailing in all cases and covering at least a 3-year period; all products must have been manufactured and fitted in accordance with the Fabricator's Manual, and have been used and cared for in accordance with the Guide to Use, Cleaning and Care available on the web page www.porcelanosa.com; WarrantyDurationLabor: n/a; WarrantyDurationParts: 3; WarrantyDurationUnit: year; WarrantyGuarantorLabor: n/a; WarrantyGuarantorParts: bim.gp@porcelanosagrupo.com
Type - Pset_CoveringCommon - Reference: n/a; IsExternal: no; AcousticRating: n/a; Finish: Concrete, Tone Variations, Matte, Rectified; FireRating: A1; FlammabilityRating: Class 0; FragilityRating: n/a; Material: Ceramic; SurfaceSpreadOfFlame: Class 0; ThermalTransmittance: 230 kg/K/s3; TotalThickness: 10 mm
Type - IFC - IfcExportType: CLADDING; IfcExportAS: IfcCovering
Type - NBS_Data - HasSurfaceRoughness: no; AbrasionResistance: 1: Wall Tiles; BreakingStrength: Average Value: 1337 N (Min. 600 N); ChemicalResistance: Class 'A' for swimming pools and cleaning products (resists attack); minimum Class 'B' for acids and bases; Collection: Revestimiento Ceramico Rectificado; CreationDate: 2018/07; Dcof: n/a; FlexuralStrength: >23 N/mm²; FrostResistance: n/a; Group: BIII; MoistureExpansion: <0.1 mm/m; RampTest: R-10; RecycledContent: >18%; Series: Botega; SlipResistanceValuePendulumTestValue: CL1; StainResistance: Class 5: Easy cleaning with water; SurfaceQuality: Without surface defects; ThermalShockResistance: Conforms to ISO 10545–12; UpecC: n/a; UpecE: n/a; UpecP: n/a; UpecU: n/a; WaterAbsorption: 10%<=E<=20%
COBie - AssetIdentifier: n/a; BarCode: n/a; InstallationDate: 1900-12-31T23:59:59; TagNumber: n/a; WarrantyStartDate: 1900-12-31T23:59:59

# IfcWallStandardCase: Basic Wall:PGR_Porcelanosa_CeramicTiles_Bottega_Acero-596x596mm-100214641, Basic Wall:PGR_Porcelanosa_CeramicTiles_Bottega_Acero-596x596mm-100214641:213282
In: Level 1
Type - PredefinedType: STANDARD; Material: PGR_Porcelanosa_CeramicTiles_Bottega_Acero-596x596mm-100214641 10.3 mm
Type - NBS_General - Author: Porcelanosa Group; BIMObjectName: PGR_Porcelanosa_CeramicTiles_Bottega_Acero-596x596mm-100214641; ManufacturerURL: www.porcelanosa.com; NBSDescription: Ceramic Tiles; NBSReference: 45-80-95/310; ProductInformation: http://calidad.info-grupo.com:8081/GeneraFicha3/PDF?articulo=100214641&lang=EN&un=0; Revision: n/a; Uniclass2015Code: Pr_35_93_96_19; Uniclass2015Title: Ceramic Tiles; Uniclass2015Version: Products v1.5; Version: 1
Type - COBie - AccessibilityPerformance: See ProductInformation (Technical PDF); AssetType: Fixed; Category: Walls; CodePerformance: ISO-13006:2012; UNE-EN 14411:2012; Color: Gris; Constituents: Clays, feldespat and glaze; Description: Rectified Porcelain tiles, BOTEGA series from PORCELANOSA, GRIS color and MATTE finish, 59.6x59.6 cm (10.3 mm thickness), group BIa, according to UNE-EN 14411, water absortion capacity E<=0.5%, flexural strength >40 N/mm², breaking strength with an average value of 3310 N (Min. 1300 N) and slip resistance R-10; DurationUnit: year; ExpectedLife: 50; Features: See ProductInformation (Technical PDF); Grade: First quality; Manufacturer: bim.gp@porcelanosagrupo.com; ModelNumber: 100214641; ModelReference: Bottega Acero 59.6x59.6 cm; Name: CeramicTiles_Bottega_Acero-596x596mm-100214641; NominalHeight: 10.3 mm; NominalLength: 596 mm; NominalWidth: 596 mm; ReplacementCost: n/a; Shape: Squared; Size: 596x596x10.3 mm; Sustainability Performance: See ProductInformation (Technical PDF); WarrantyDescription: Manufacturer warranty, applicable worldwide, with the pertinent national legislation prevailing in all cases and covering at least a 3-year period; all products must have been manufactured and fitted in accordance with the Fabricator's Manual, and have been used and cared for in accordance with the Guide to Use, Cleaning and Care available on the web page www.porcelanosa.com; WarrantyDurationLabor: n/a; WarrantyDurationParts: 3; WarrantyDurationUnit: year; WarrantyGuarantorLabor: n/a; WarrantyGuarantorParts: bim.gp@porcelanosagrupo.com
Type - Pset_CoveringCommon - IsExternal: yes; Reference: n/a; AcousticRating: n/a; Finish: Concrete, Tone Variations, Matte, Rectified; FireRating: A1; FlammabilityRating: Class 0; FragilityRating: n/a; Material: Ceramic; SurfaceSpreadOfFlame: Class 0; ThermalTransmittance: 223.301 kg/K/s3; TotalThickness: 10.3 mm
Type - IFC - IfcExportType: FLOORING; IfcExportAS: IfcCovering
Type - NBS_Data - HasSurfaceRoughness: no; AbrasionResistance: 6: Intense-External Access; BreakingStrength: Average Value: 3310 N (Min. 1300 N); ChemicalResistance: Class 'A' for swimming pools and cleaning products (resists attack); minimum Class 'B' for acids and bases; Collection: STON-KER; CreationDate: 2018/07; Dcof: n/a; FlexuralStrength: >40 N/mm²; FrostResistance: Conforms to ISO 10545-9; Group: BIa; MoistureExpansion: <0.1 mm/m; RampTest: R-10; RecycledContent: >6.5%; Series: Botega; SlipResistanceValuePendulumTestValue: CL1; StainResistance: Class 5: Easy cleaning with water; SurfaceQuality: Without surface defects; ThermalShockResistance: Conforms to ISO 10545–12; UpecC: n/a; UpecE: n/a; UpecP: n/a; UpecU: n/a; WaterAbsorption: E<=0.5%
COBie - AssetIdentifier: n/a; BarCode: n/a; InstallationDate: 1900-12-31T23:59:59; TagNumber: n/a; WarrantyStartDate: 1900-12-31T23:59:59

# IfcWallStandardCase: Basic Wall:PGR_Porcelanosa_CeramicTiles_Bottega_Acero-800x800mm-100214633, Basic Wall:PGR_Porcelanosa_CeramicTiles_Bottega_Acero-800x800mm-100214633:213292
In: Level 1
Type - PredefinedType: STANDARD; Material: PGR_Porcelanosa_CeramicTiles_Bottega_Acero-800x800mm-100214633 11.2 mm
Type - NBS_General - Author: Porcelanosa Group; BIMObjectName: PGR_Porcelanosa_CeramicTiles_Bottega_Acero-800x800mm-100214633; ManufacturerURL: www.porcelanosa.com; NBSDescription: Ceramic Tiles; NBSReference: 45-80-95/310; ProductInformation: http://calidad.info-grupo.com:8081/GeneraFicha3/PDF?articulo=100214633&lang=EN&un=0; Revision: n/a; Uniclass2015Code: Pr_35_93_96_19; Uniclass2015Title: Ceramic Tiles; Uniclass2015Version: Products v1.5; Version: 1
Type - COBie - AccessibilityPerformance: See ProductInformation (Technical PDF); AssetType: Fixed; Category: Walls; CodePerformance: ISO-13006:2012; UNE-EN 14411:2012; Color: Gris; Constituents: Clays, feldespat and glaze; Description: Rectified Porcelain tiles, BOTEGA series from PORCELANOSA, GRIS color and MATTE finish, 80x80 cm (11.2 mm thickness), group BIa, according to UNE-EN 14411, water absortion capacity E<=0.5%, flexural strength >40 N/mm², breaking strength with an average value of 3310 N (Min. 1300 N) and slip resistance R-10; DurationUnit: year; ExpectedLife: 50; Features: See ProductInformation (Technical PDF); Grade: First quality; Manufacturer: bim.gp@porcelanosagrupo.com; ModelNumber: 100214633; ModelReference: Bottega Acero 80x80 cm; Name: CeramicTiles_Bottega_Acero-800x800mm-100214633; NominalHeight: 11.2 mm; NominalLength: 800 mm; NominalWidth: 800 mm; ReplacementCost: n/a; Shape: Squared; Size: 800x800x11.2 mm; Sustainability Performance: See ProductInformation (Technical PDF); WarrantyDescription: Manufacturer warranty, applicable worldwide, with the pertinent national legislation prevailing in all cases and covering at least a 3-year period; all products must have been manufactured and fitted in accordance with the Fabricator's Manual, and have been used and cared for in accordance with the Guide to Use, Cleaning and Care available on the web page www.porcelanosa.com; WarrantyDurationLabor: n/a; WarrantyDurationParts: 3; WarrantyDurationUnit: year; WarrantyGuarantorLabor: n/a; WarrantyGuarantorParts: bim.gp@porcelanosagrupo.com
Type - Pset_CoveringCommon - IsExternal: yes; Reference: n/a; AcousticRating: n/a; Finish: Concrete, Tone Variations, Matte, Rectified; FireRating: A1; FlammabilityRating: Class 0; FragilityRating: n/a; Material: Ceramic; SurfaceSpreadOfFlame: Class 0; ThermalTransmittance: 205.357 kg/K/s3; TotalThickness: 11.2 mm
Type - IFC - IfcExportType: FLOORING; IfcExportAS: IfcCovering
Type - NBS_Data - HasSurfaceRoughness: no; AbrasionResistance: 6: Intense-External Access; BreakingStrength: Average Value: 3310 N (Min. 1300 N); ChemicalResistance: Class 'A' for swimming pools and cleaning products (resists attack); minimum Class 'B' for acids and bases; Collection: STON-KER; CreationDate: 2018/07; Dcof: n/a; FlexuralStrength: >40 N/mm²; FrostResistance: Conforms to ISO 10545-9; Group: BIa; MoistureExpansion: <0.1 mm/m; RampTest: R-10; RecycledContent: >6.5%; Series: Botega; SlipResistanceValuePendulumTestValue: CL1; StainResistance: Class 5: Easy cleaning with water; SurfaceQuality: Without surface defects; ThermalShockResistance: Conforms to ISO 10545–12; UpecC: n/a; UpecE: n/a; UpecP: n/a; UpecU: n/a; WaterAbsorption: E<=0.5%
COBie - AssetIdentifier: n/a; BarCode: n/a; InstallationDate: 1900-12-31T23:59:59; TagNumber: n/a; WarrantyStartDate: 1900-12-31T23:59:59

# IfcWallStandardCase: Basic Wall:PGR_Porcelanosa_CeramicTiles_Bottega_Acero_Ant.-596x596mm-100221464, Basic Wall:PGR_Porcelanosa_CeramicTiles_Bottega_Acero_Ant.-596x596mm-100221464:213302
In: Level 1
Type - PredefinedType: STANDARD; Material: PGR_Porcelanosa_CeramicTiles_Bottega_Acero_Ant.-596x596mm-100221464 10.3 mm
Type - NBS_General - Author: Porcelanosa Group; BIMObjectName: PGR_Porcelanosa_CeramicTiles_Bottega_Acero_Ant.-596x596mm-100221464; ManufacturerURL: www.porcelanosa.com; NBSDescription: Ceramic Tiles; NBSReference: 45-80-95/310; ProductInformation: http://calidad.info-grupo.com:8081/GeneraFicha3/PDF?articulo=100221464&lang=EN&un=0; Revision: n/a; Uniclass2015Code: Pr_35_93_96_19; Uniclass2015Title: Ceramic Tiles; Uniclass2015Version: Products v1.5; Version: 1
Type - COBie - AccessibilityPerformance: See ProductInformation (Technical PDF); AssetType: Fixed; Category: Walls; CodePerformance: ISO-13006:2012; UNE-EN 14411:2012; Color: Gris; Constituents: Clays, feldespat and glaze; Description: Rectified Porcelain tiles, BOTEGA series from PORCELANOSA, GRIS color and MATTE finish, 59.6x59.6 cm (10.3 mm thickness), group BIa, according to UNE-EN 14411, water absortion capacity E<=0.5%, flexural strength >40 N/mm², breaking strength with an average value of 3310 N (Min. 1300 N) and slip resistance R-13; DurationUnit: year; ExpectedLife: 50; Features: See ProductInformation (Technical PDF); Grade: First quality; Manufacturer: bim.gp@porcelanosagrupo.com; ModelNumber: 100221464; ModelReference: Bottega Acero Ant. 59.6x59.6 cm; Name: CeramicTiles_Bottega_Acero_Ant.-596x596mm-100221464; NominalHeight: 10.3 mm; NominalLength: 596 mm; NominalWidth: 596 mm; ReplacementCost: n/a; Shape: Squared; Size: 596x596x10.3 mm; Sustainability Performance: See ProductInformation (Technical PDF); WarrantyDescription: Manufacturer warranty, applicable worldwide, with the pertinent national legislation prevailing in all cases and covering at least a 3-year period; all products must have been manufactured and fitted in accordance with the Fabricator's Manual, and have been used and cared for in accordance with the Guide to Use, Cleaning and Care available on the web page www.porcelanosa.com; WarrantyDurationLabor: n/a; WarrantyDurationParts: 3; WarrantyDurationUnit: year; WarrantyGuarantorLabor: n/a; WarrantyGuarantorParts: bim.gp@porcelanosagrupo.com
Type - Pset_CoveringCommon - IsExternal: yes; Reference: n/a; AcousticRating: n/a; Finish: Concrete, Tone Variations, Matte, Non-Slip, Rectified; FireRating: A1; FlammabilityRating: Class 0; FragilityRating: n/a; Material: Ceramic; SurfaceSpreadOfFlame: Class 0; ThermalTransmittance: 223.301 kg/K/s3; TotalThickness: 10.3 mm
Type - IFC - IfcExportType: FLOORING; IfcExportAS: IfcCovering
Type - NBS_Data - HasSurfaceRoughness: no; AbrasionResistance: 6: Intense-External Access; BreakingStrength: Average Value: 3310 N (Min. 1300 N); ChemicalResistance: Class 'A' for swimming pools and cleaning products (resists attack); minimum Class 'B' for acids and bases; Collection: STON-KER; CreationDate: 2018/07; Dcof: >0.42; FlexuralStrength: >40 N/mm²; FrostResistance: Conforms to ISO 10545-9; Group: BIa; MoistureExpansion: <0.1 mm/m; RampTest: R-13; RecycledContent: >6.5%; Series: Botega; SlipResistanceValuePendulumTestValue: CL3; StainResistance: Class 5: Easy cleaning with water; SurfaceQuality: Without surface defects; ThermalShockResistance: Conforms to ISO 10545–12; UpecC: n/a; UpecE: n/a; UpecP: n/a; UpecU: n/a; WaterAbsorption: E<=0.5%
COBie - AssetIdentifier: n/a; BarCode: n/a; InstallationDate: 1900-12-31T23:59:59; TagNumber: n/a; WarrantyStartDate: 1900-12-31T23:59:59

# IfcWallStandardCase: Basic Wall:PGR_Porcelanosa_CeramicTiles_Bottega_Acero_Ant.-800x800mm-100221486, Basic Wall:PGR_Porcelanosa_CeramicTiles_Bottega_Acero_Ant.-800x800mm-100221486:213312
In: Level 1
Type - PredefinedType: STANDARD; Material: PGR_Porcelanosa_CeramicTiles_Bottega_Acero_Ant.-800x800mm-100221486 11.2 mm
Type - NBS_General - Author: Porcelanosa Group; BIMObjectName: PGR_Porcelanosa_CeramicTiles_Bottega_Acero_Ant.-800x800mm-100221486; ManufacturerURL: www.porcelanosa.com; NBSDescription: Ceramic Tiles; NBSReference: 45-80-95/310; ProductInformation: http://calidad.info-grupo.com:8081/GeneraFicha3/PDF?articulo=100221486&lang=EN&un=0; Revision: n/a; Uniclass2015Code: Pr_35_93_96_19; Uniclass2015Title: Ceramic Tiles; Uniclass2015Version: Products v1.5; Version: 1
Type - COBie - AccessibilityPerformance: See ProductInformation (Technical PDF); AssetType: Fixed; Category: Pr_35_93_96_19:Ceramic Tiles; CodePerformance: ISO-13006:2012; UNE-EN 14411:2012; Color: Gris; Constituents: Clays, feldespat and glaze; Description: Rectified Porcelain tiles, BOTEGA series from PORCELANOSA, GRIS color and MATTE finish, 80x80 cm (11.2 mm thickness), group BIa, according to UNE-EN 14411, water absortion capacity E<=0.5%, flexural strength >40 N/mm², breaking strength with an average value of 3310 N (Min. 1300 N) and slip resistance R-13; DurationUnit: year; ExpectedLife: 50; Features: See ProductInformation (Technical PDF); Grade: First quality; Manufacturer: bim.gp@porcelanosagrupo.com; ModelNumber: 100221486; ModelReference: Bottega Acero Ant. 80x80 cm; Name: CeramicTiles_Bottega_Acero_Ant.-800x800mm-100221486; NominalHeight: 11.2 mm; NominalLength: 800 mm; NominalWidth: 800 mm; ReplacementCost: n/a; Shape: Squared; Size: 800x800x11.2 mm; Sustainability Performance: See ProductInformation (Technical PDF); WarrantyDescription: Manufacturer warranty, applicable worldwide, with the pertinent national legislation prevailing in all cases and covering at least a 3-year period; all products must have been manufactured and fitted in accordance with the Fabricator's Manual, and have been used and cared for in accordance with the Guide to Use, Cleaning and Care available on the web page www.porcelanosa.com; WarrantyDurationLabor: n/a; WarrantyDurationParts: 3; WarrantyDurationUnit: year; WarrantyGuarantorLabor: n/a; WarrantyGuarantorParts: bim.gp@porcelanosagrupo.com
Type - Pset_CoveringCommon - IsExternal: yes; Reference: n/a; AcousticRating: n/a; Finish: Concrete, Tone Variations, Matte, Non-Slip, Rectified; FireRating: A1; FlammabilityRating: Class 0; FragilityRating: n/a; Material: Ceramic; SurfaceSpreadOfFlame: Class 0; ThermalTransmittance: 205.357 kg/K/s3; TotalThickness: 11.2 mm
Type - IFC - IfcExportType: FLOORING; IfcExportAS: IfcCovering
Type - NBS_Data - HasSurfaceRoughness: no; AbrasionResistance: 6: Intense-External Access; BreakingStrength: Average Value: 3310 N (Min. 1300 N); ChemicalResistance: Class 'A' for swimming pools and cleaning products (resists attack); minimum Class 'B' for acids and bases; Collection: STON-KER; CreationDate: 2018/07; Dcof: >0.42; FlexuralStrength: >40 N/mm²; FrostResistance: Conforms to ISO 10545-9; Group: BIa; MoistureExpansion: <0.1 mm/m; RampTest: R-13; RecycledContent: >6.5%; Series: Botega; SlipResistanceValuePendulumTestValue: CL3; StainResistance: Class 5: Easy cleaning with water; SurfaceQuality: Without surface defects; ThermalShockResistance: Conforms to ISO 10545–12; UpecC: n/a; UpecE: n/a; UpecP: n/a; UpecU: n/a; WaterAbsorption: E<=0.5%
COBie - AssetIdentifier: n/a; BarCode: n/a; InstallationDate: 1900-12-31T23:59:59; TagNumber: n/a; WarrantyStartDate: 1900-12-31T23:59:59

# IfcWallStandardCase: Basic Wall:PGR_Porcelanosa_CeramicTiles_Bottega_Caliza-1200x1200mm-100214898, Basic Wall:PGR_Porcelanosa_CeramicTiles_Bottega_Caliza-1200x1200mm-100214898:213322
In: Level 1
Type - PredefinedType: STANDARD; Material: PGR_Porcelanosa_CeramicTiles_Bottega_Caliza-1200x1200mm-100214898 12 mm
Type - NBS_General - Author: Porcelanosa Group; BIMObjectName: PGR_Porcelanosa_CeramicTiles_Bottega_Caliza-1200x1200mm-100214898; ManufacturerURL: www.porcelanosa.com; NBSDescription: Ceramic Tiles; NBSReference: 45-80-95/310; ProductInformation: http://calidad.info-grupo.com:8081/GeneraFicha3/PDF?articulo=100214898&lang=EN&un=0; Revision: n/a; Uniclass2015Code: Pr_35_93_96_19; Uniclass2015Title: Ceramic Tiles; Uniclass2015Version: Products v1.5; Version: 1
Type - COBie - AccessibilityPerformance: See ProductInformation (Technical PDF); AssetType: Fixed; Category: Pr_35_93_96_19:Ceramic Tiles; CodePerformance: ISO-13006:2012; UNE-EN 14411:2012; Color: Beige; Constituents: Clays, feldespat and glaze; Description: Rectified Porcelain tiles, BOTEGA series from PORCELANOSA, BEIGE color and MATTE finish, 120x120 cm (11.5 mm thickness), group BIa, according to UNE-EN 14411, water absortion capacity E<=0.5%, flexural strength >40 N/mm², breaking strength with an average value of 3310 N (Min. 1300 N) and slip resistance R-10; DurationUnit: year; ExpectedLife: 50; Features: See ProductInformation (Technical PDF); Grade: First quality; Manufacturer: bim.gp@porcelanosagrupo.com; ModelNumber: 100214898; ModelReference: Bottega Caliza 120x120 cm; Name: CeramicTiles_Bottega_Caliza-1200x1200mm-100214898; NominalHeight: 11.5 mm; NominalLength: 1200 mm; NominalWidth: 1200 mm; ReplacementCost: n/a; Shape: Squared; Size: 1200x1200x11.5 mm; Sustainability Performance: See ProductInformation (Technical PDF); WarrantyDescription: Manufacturer warranty, applicable worldwide, with the pertinent national legislation prevailing in all cases and covering at least a 3-year period; all products must have been manufactured and fitted in accordance with the Fabricator's Manual, and have been used and cared for in accordance with the Guide to Use, Cleaning and Care available on the web page www.porcelanosa.com; WarrantyDurationLabor: n/a; WarrantyDurationParts: 3; WarrantyDurationUnit: year; WarrantyGuarantorLabor: n/a; WarrantyGuarantorParts: bim.gp@porcelanosagrupo.com
Type - Pset_CoveringCommon - IsExternal: yes; Reference: n/a; AcousticRating: n/a; Finish: Concrete, Tone Variations, Matte, Rectified; FireRating: A1; FlammabilityRating: Class 0; FragilityRating: n/a; Material: Ceramic; SurfaceSpreadOfFlame: Class 0; ThermalTransmittance: 200 kg/K/s3; TotalThickness: 11.5 mm
Type - IFC - IfcExportType: FLOORING; IfcExportAS: IfcCovering
Type - NBS_Data - HasSurfaceRoughness: no; AbrasionResistance: 6: Intense-External Access; BreakingStrength: Average Value: 3310 N (Min. 1300 N); ChemicalResistance: Class 'A' for swimming pools and cleaning products (resists attack); minimum Class 'B' for acids and bases; Collection: Porcelanico Tecnico; CreationDate: 2018/07; Dcof: n/a; FlexuralStrength: >40 N/mm²; FrostResistance: Conforms to ISO 10545-9; Group: BIa; MoistureExpansion: <0.1 mm/m; RampTest: R-10; RecycledContent: >6.5%; Series: Botega; SlipResistanceValuePendulumTestValue: CL1; StainResistance: Class 5: Easy cleaning with water; SurfaceQuality: Without surface defects; ThermalShockResistance: Conforms to ISO 10545–12; UpecC: n/a; UpecE: n/a; UpecP: n/a; UpecU: n/a; WaterAbsorption: E<=0.5%
COBie - AssetIdentifier: n/a; BarCode: n/a; InstallationDate: 1900-12-31T23:59:59; TagNumber: n/a; WarrantyStartDate: 1900-12-31T23:59:59

# IfcWallStandardCase: Basic Wall:PGR_Porcelanosa_CeramicTiles_Bottega_Caliza-316x592mm-100225103, Basic Wall:PGR_Porcelanosa_CeramicTiles_Bottega_Caliza-316x592mm-100225103:218953
In: Level 1
Type - PredefinedType: STANDARD; Material: PGR_Porcelanosa_CeramicTiles_Bottega_Caliza-316x592mm-100225103 11.3 mm
Type - NBS_General - Author: Porcelanosa Group; BIMObjectName: PGR_Porcelanosa_CeramicTiles_Bottega_Caliza-316x592mm-100225103; ManufacturerURL: www.porcelanosa.com; NBSDescription: Ceramic Tiles; NBSReference: 45-80-95/310; ProductInformation: http://calidad.info-grupo.com:8081/GeneraFicha3/PDF?articulo=100225103&lang=EN&un=0; Revision: n/a; Uniclass2015Code: Pr_35_93_96_19; Uniclass2015Title: Ceramic Tiles; Uniclass2015Version: Products v1.5; Version: 1
Type - COBie - AccessibilityPerformance: See ProductInformation (Technical PDF); AssetType: Fixed; Category: Pr_35_93_96_19:Ceramic Tiles; CodePerformance: ISO-13006:2012; UNE-EN 14411:2012; Color: Beige; Constituents: Clays, feldespat and glaze; Description: Monoporous, BOTEGA series from PORCELANOSA, BEIGE color and MATTE finish, 31.6x59.2 cm (8.7 mm thickness), group BIII, according to UNE-EN 14411, water absortion capacity 10%<=E<=20%, flexural strength >23 N/mm² and breaking strength with an average value of 1337 N (Min. 600 N); DurationUnit: year; ExpectedLife: 50; Features: See ProductInformation (Technical PDF); Grade: First quality; Manufacturer: bim.gp@porcelanosagrupo.com; ModelNumber: 100225103; ModelReference: Bottega Caliza 31.6x59.2 cm; Name: CeramicTiles_Bottega_Caliza-316x592mm-100225103; NominalHeight: 8.7 mm; NominalLength: 592 mm; NominalWidth: 316 mm; ReplacementCost: n/a; Shape: Rectangular; Size: 316x592x8.7 mm; Sustainability Performance: See ProductInformation (Technical PDF); WarrantyDescription: Manufacturer warranty, applicable worldwide, with the pertinent national legislation prevailing in all cases and covering at least a 3-year period; all products must have been manufactured and fitted in accordance with the Fabricator's Manual, and have been used and cared for in accordance with the Guide to Use, Cleaning and Care available on the web page www.porcelanosa.com; WarrantyDurationLabor: n/a; WarrantyDurationParts: 3; WarrantyDurationUnit: year; WarrantyGuarantorLabor: n/a; WarrantyGuarantorParts: bim.gp@porcelanosagrupo.com
Type - Pset_CoveringCommon - Reference: n/a; IsExternal: no; AcousticRating: n/a; Finish: Concrete, Tone Variations, Matte; FireRating: A1; FlammabilityRating: Class 0; FragilityRating: n/a; Material: Ceramic; SurfaceSpreadOfFlame: Class 0; ThermalTransmittance: 264.368 kg/K/s3; TotalThickness: 8.7 mm
Type - IFC - IfcExportType: CLADDING; IfcExportAS: IfcCovering
Type - NBS_Data - HasSurfaceRoughness: no; AbrasionResistance: 1: Wall Tiles; BreakingStrength: Average Value: 1337 N (Min. 600 N); ChemicalResistance: Class 'A' for swimming pools and cleaning products (resists attack); minimum Class 'B' for acids and bases; Collection: Revestimiento Ceramico; CreationDate: 2018/07; Dcof: n/a; FlexuralStrength: >23 N/mm²; FrostResistance: n/a; Group: BIII; MoistureExpansion: <0.1 mm/m; RampTest: n/a; RecycledContent: >18%; Series: Botega; SlipResistanceValuePendulumTestValue: n/a; StainResistance: Class 5: Easy cleaning with water; SurfaceQuality: Without surface defects; ThermalShockResistance: Conforms to ISO 10545–12; UpecC: n/a; UpecE: n/a; UpecP: n/a; UpecU: n/a; WaterAbsorption: 10%<=E<=20%
COBie - AssetIdentifier: n/a; BarCode: n/a; InstallationDate: 1900-12-31T23:59:59; TagNumber: n/a; WarrantyStartDate: 1900-12-31T23:59:59

# IfcWallStandardCase: Basic Wall:PGR_Porcelanosa_CeramicTiles_Bottega_Caliza-316x900mm-100215126, Basic Wall:PGR_Porcelanosa_CeramicTiles_Bottega_Caliza-316x900mm-100215126:213467
In: Level 1
Type - PredefinedType: STANDARD; Material: PGR_Porcelanosa_CeramicTiles_Bottega_Caliza-316x900mm-100215126 9 mm
Type - NBS_General - Author: Porcelanosa Group; BIMObjectName: PGR_Porcelanosa_CeramicTiles_Bottega_Caliza-316x900mm-100215126; ManufacturerURL: www.porcelanosa.com; NBSDescription: Ceramic Tiles; NBSReference: 45-80-95/310; ProductInformation: http://calidad.info-grupo.com:8081/GeneraFicha3/PDF?articulo=100215126&lang=EN&un=0; Revision: n/a; Uniclass2015Code: Pr_35_93_96_19; Uniclass2015Title: Ceramic Tiles; Uniclass2015Version: Products v1.5; Version: 1
Type - COBie - AccessibilityPerformance: See ProductInformation (Technical PDF); AssetType: Fixed; Category: Pr_35_93_96_19:Ceramic Tiles; CodePerformance: ISO-13006:2012; UNE-EN 14411:2012; Color: Beige; Constituents: Clays, feldespat and glaze; Description: Rectified Monoporous, VENETO series from PORCELANOSA, BEIGE color and MATTE finish, 31.6x90 cm (9.2 mm thickness), group BIII, according to UNE-EN 14411, water absortion capacity 10%<=E<=20%, flexural strength >23 N/mm², breaking strength with an average value of 1337 N (Min. 600 N) and slip resistance -; DurationUnit: year; ExpectedLife: 50; Features: See ProductInformation (Technical PDF); Grade: First quality; Manufacturer: bim.gp@porcelanosagrupo.com; ModelNumber: 100215126; ModelReference: Bottega Caliza 31.6x90 cm; Name: CeramicTiles_Bottega_Caliza-316x900mm-100215126; NominalHeight: 9.2 mm; NominalLength: 900 mm; NominalWidth: 316 mm; ReplacementCost: n/a; Shape: Rectangular; Size: 316x900x9.2 mm; Sustainability Performance: See ProductInformation (Technical PDF); WarrantyDescription: Manufacturer warranty, applicable worldwide, with the pertinent national legislation prevailing in all cases and covering at least a 3-year period; all products must have been manufactured and fitted in accordance with the Fabricator's Manual, and have been used and cared for in accordance with the Guide to Use, Cleaning and Care available on the web page www.porcelanosa.com; WarrantyDurationLabor: n/a; WarrantyDurationParts: 3; WarrantyDurationUnit: year; WarrantyGuarantorLabor: n/a; WarrantyGuarantorParts: bim.gp@porcelanosagrupo.com
Type - Pset_CoveringCommon - Reference: n/a; IsExternal: no; AcousticRating: n/a; Finish: Concrete, Tone Variations, Matte, Rectified; FireRating: A1; FlammabilityRating: Class 0; FragilityRating: n/a; Material: Ceramic; SurfaceSpreadOfFlame: Class 0; ThermalTransmittance: 250 kg/K/s3; TotalThickness: 9.2 mm
Type - IFC - IfcExportType: CLADDING; IfcExportAS: IfcCovering
Type - NBS_Data - HasSurfaceRoughness: no; AbrasionResistance: 1: Wall Tiles; BreakingStrength: Average Value: 1337 N (Min. 600 N); ChemicalResistance: Class 'A' for swimming pools and cleaning products (resists attack); minimum Class 'B' for acids and bases; Collection: Revestimiento Ceramico Rectificado; CreationDate: 2018/07; Dcof: n/a; FlexuralStrength: >23 N/mm²; FrostResistance: n/a; Group: BIII; MoistureExpansion: <0.1 mm/m; RampTest: -; RecycledContent: >18%; Series: Veneto; SlipResistanceValuePendulumTestValue: n/a; StainResistance: Class 5: Easy cleaning with water; SurfaceQuality: Without surface defects; ThermalShockResistance: Conforms to ISO 10545–12; UpecC: n/a; UpecE: n/a; UpecP: n/a; UpecU: n/a; WaterAbsorption: 10%<=E<=20%
COBie - AssetIdentifier: n/a; BarCode: n/a; InstallationDate: 1900-12-31T23:59:59; TagNumber: n/a; WarrantyStartDate: 1900-12-31T23:59:59

# IfcWallStandardCase: Basic Wall:PGR_Porcelanosa_CeramicTiles_Bottega_Caliza-443x443mm-100225065, Basic Wall:PGR_Porcelanosa_CeramicTiles_Bottega_Caliza-443x443mm-100225065:213392
In: Level 1
Type - PredefinedType: STANDARD; Material: PGR_Porcelanosa_CeramicTiles_Bottega_Caliza-443x443mm-100225065 11.2 mm
Type - NBS_General - Author: Porcelanosa Group; BIMObjectName: PGR_Porcelanosa_CeramicTiles_Bottega_Caliza-443x443mm-100225065; ManufacturerURL: www.porcelanosa.com; NBSDescription: Ceramic Tiles; NBSReference: 45-80-95/310; ProductInformation: http://calidad.info-grupo.com:8081/GeneraFicha3/PDF?articulo=100225065&lang=EN&un=0; Revision: n/a; Uniclass2015Code: Pr_35_93_96_19; Uniclass2015Title: Ceramic Tiles; Uniclass2015Version: Products v1.5; Version: 1
Type - COBie - AccessibilityPerformance: See ProductInformation (Technical PDF); AssetType: Fixed; Category: Pr_35_93_96_19:Ceramic Tiles; CodePerformance: ISO-13006:2012; UNE-EN 14411:2012; Color: Beige; Constituents: Clays, feldespat and glaze; Description: Porcelain tiles, BOTEGA series from PORCELANOSA, BEIGE color and MATTE finish, 44.3x44.3 cm (10 mm thickness), group BIa, according to UNE-EN 14411, water absortion capacity E<=0.5%, flexural strength >40 N/mm², breaking strength with an average value of 3310 N (Min. 1300 N) and slip resistance R-10; DurationUnit: year; ExpectedLife: 50; Features: See ProductInformation (Technical PDF); Grade: First quality; Manufacturer: bim.gp@porcelanosagrupo.com; ModelNumber: 100225065; ModelReference: Bottega Caliza 44.3x44.3 cm; Name: CeramicTiles_Bottega_Caliza-443x443mm-100225065; NominalHeight: 10 mm; NominalLength: 443 mm; NominalWidth: 443 mm; ReplacementCost: n/a; Shape: Squared; Size: 443x443x10 mm; Sustainability Performance: See ProductInformation (Technical PDF); WarrantyDescription: Manufacturer warranty, applicable worldwide, with the pertinent national legislation prevailing in all cases and covering at least a 3-year period; all products must have been manufactured and fitted in accordance with the Fabricator's Manual, and have been used and cared for in accordance with the Guide to Use, Cleaning and Care available on the web page www.porcelanosa.com; WarrantyDurationLabor: n/a; WarrantyDurationParts: 3; WarrantyDurationUnit: year; WarrantyGuarantorLabor: n/a; WarrantyGuarantorParts: bim.gp@porcelanosagrupo.com
Type - Pset_CoveringCommon - IsExternal: yes; Reference: n/a; AcousticRating: n/a; Finish: Concrete, Tone Variations, Matte; FireRating: A1; FlammabilityRating: Class 0; FragilityRating: n/a; Material: Ceramic; SurfaceSpreadOfFlame: Class 0; ThermalTransmittance: 230 kg/K/s3; TotalThickness: 10 mm
Type - IFC - IfcExportType: FLOORING; IfcExportAS: IfcCovering
Type - NBS_Data - HasSurfaceRoughness: no; AbrasionResistance: 6: Intense-External Access; BreakingStrength: Average Value: 3310 N (Min. 1300 N); ChemicalResistance: Class 'A' for swimming pools and cleaning products (resists attack); minimum Class 'B' for acids and bases; Collection: Porcelanico; CreationDate: 2018/07; Dcof: n/a; FlexuralStrength: >40 N/mm²; FrostResistance: Conforms to ISO 10545-9; Group: BIa; MoistureExpansion: <0.1 mm/m; RampTest: R-10; RecycledContent: >6.5%; Series: Botega; SlipResistanceValuePendulumTestValue: CL1; StainResistance: Class 5: Easy cleaning with water; SurfaceQuality: Without surface defects; ThermalShockResistance: Conforms to ISO 10545–12; UpecC: n/a; UpecE: n/a; UpecP: n/a; UpecU: n/a; WaterAbsorption: E<=0.5%
COBie - AssetIdentifier: n/a; BarCode: n/a; InstallationDate: 1900-12-31T23:59:59; TagNumber: n/a; WarrantyStartDate: 1900-12-31T23:59:59

# IfcWallStandardCase: Basic Wall:PGR_Porcelanosa_CeramicTiles_Bottega_Caliza-450x1200mm-100214661, Basic Wall:PGR_Porcelanosa_CeramicTiles_Bottega_Caliza-450x1200mm-100214661:213468
In: Level 1
Type - PredefinedType: STANDARD; Material: PGR_Porcelanosa_CeramicTiles_Bottega_Caliza-450x1200mm-100214661 10.1 mm
Type - NBS_General - Author: Porcelanosa Group; BIMObjectName: PGR_Porcelanosa_CeramicTiles_Bottega_Caliza-450x1200mm-100214661; ManufacturerURL: www.porcelanosa.com; NBSDescription: Ceramic Tiles; NBSReference: 45-80-95/310; ProductInformation: http://calidad.info-grupo.com:8081/GeneraFicha3/PDF?articulo=100214661&lang=EN&un=0; Revision: n/a; Uniclass2015Code: Pr_35_93_96_19; Uniclass2015Title: Ceramic Tiles; Uniclass2015Version: Products v1.5; Version: 1
Type - COBie - AccessibilityPerformance: See ProductInformation (Technical PDF); AssetType: Fixed; Category: Pr_35_93_96_19:Ceramic Tiles; CodePerformance: ISO-13006:2012; UNE-EN 14411:2012; Color: Caliza; Constituents: Clays, feldespat and glaze; Description: Rectified Monoporous, BOTEGA series from PORCELANOSA, CALIZA color and MATTE finish, 45x120 cm (10.3 mm thickness), group BIII, according to UNE-EN 14411, water absortion capacity 10%<=E<=20%, flexural strength >23 N/mm², breaking strength with an average value of 1337 N (Min. 600 N) and slip resistance -; DurationUnit: year; ExpectedLife: 50; Features: See ProductInformation (Technical PDF); Grade: First quality; Manufacturer: bim.gp@porcelanosagrupo.com; ModelNumber: 100214661; ModelReference: Bottega Caliza 45x120 cm; Name: CeramicTiles_Bottega_Caliza-450x1200mm-100214661; NominalHeight: 10.3 mm; NominalLength: 1200 mm; NominalWidth: 450 mm; ReplacementCost: n/a; Shape: Rectangular; Size: 450x1200x10.3 mm; Sustainability Performance: See ProductInformation (Technical PDF); WarrantyDescription: Manufacturer warranty, applicable worldwide, with the pertinent national legislation prevailing in all cases and covering at least a 3-year period; all products must have been manufactured and fitted in accordance with the Fabricator's Manual, and have been used and cared for in accordance with the Guide to Use, Cleaning and Care available on the web page www.porcelanosa.com; WarrantyDurationLabor: n/a; WarrantyDurationParts: 3; WarrantyDurationUnit: year; WarrantyGuarantorLabor: n/a; WarrantyGuarantorParts: bim.gp@porcelanosagrupo.com
Type - Pset_CoveringCommon - Reference: n/a; IsExternal: no; AcousticRating: n/a; Finish: Concrete, Tone Variations, Matte, Rectified; FireRating: A1; FlammabilityRating: Class 0; FragilityRating: n/a; Material: Ceramic; SurfaceSpreadOfFlame: Class 0; ThermalTransmittance: 223.301 kg/K/s3; TotalThickness: 10.3 mm
Type - IFC - IfcExportType: CLADDING; IfcExportAS: IfcCovering
Type - NBS_Data - HasSurfaceRoughness: no; AbrasionResistance: 1: Wall Tiles; BreakingStrength: Average Value: 1337 N (Min. 600 N); ChemicalResistance: Class 'A' for swimming pools and cleaning products (resists attack); minimum Class 'B' for acids and bases; Collection: Revestimiento Ceramico Rectificado; CreationDate: 2018/07; Dcof: n/a; FlexuralStrength: >23 N/mm²; FrostResistance: n/a; Group: BIII; MoistureExpansion: <0.1 mm/m; RampTest: -; RecycledContent: >18%; Series: Botega; SlipResistanceValuePendulumTestValue: n/a; StainResistance: Class 5: Easy cleaning with water; SurfaceQuality: Without surface defects; ThermalShockResistance: Conforms to ISO 10545–12; UpecC: n/a; UpecE: n/a; UpecP: n/a; UpecU: n/a; WaterAbsorption: 10%<=E<=20%
COBie - AssetIdentifier: n/a; BarCode: n/a; InstallationDate: 1900-12-31T23:59:59; TagNumber: n/a; WarrantyStartDate: 1900-12-31T23:59:59

# IfcWallStandardCase: Basic Wall:PGR_Porcelanosa_CeramicTiles_Bottega_Caliza-596x596mm-100214648, Basic Wall:PGR_Porcelanosa_CeramicTiles_Bottega_Caliza-596x596mm-100214648:213332
In: Level 1
Type - PredefinedType: STANDARD; Material: PGR_Porcelanosa_CeramicTiles_Bottega_Caliza-596x596mm-100214648 10.3 mm
Type - NBS_General - Author: Porcelanosa Group; BIMObjectName: PGR_Porcelanosa_CeramicTiles_Bottega_Caliza-596x596mm-100214648; ManufacturerURL: www.porcelanosa.com; NBSDescription: Ceramic Tiles; NBSReference: 45-80-95/310; ProductInformation: http://calidad.info-grupo.com:8081/GeneraFicha3/PDF?articulo=100214648&lang=EN&un=0; Revision: n/a; Uniclass2015Code: Pr_35_93_96_19; Uniclass2015Title: Ceramic Tiles; Uniclass2015Version: Products v1.5; Version: 1
Type - COBie - AccessibilityPerformance: See ProductInformation (Technical PDF); AssetType: Fixed; Category: Walls; CodePerformance: ISO-13006:2012; UNE-EN 14411:2012; Color: Caliza; Constituents: Clays, feldespat and glaze; Description: Rectified Porcelain tiles, BOTEGA series from PORCELANOSA, CALIZA color and MATTE finish, 59.6x59.6 cm (10.3 mm thickness), group BIa, according to UNE-EN 14411, water absortion capacity E<=0.5%, flexural strength >40 N/mm², breaking strength with an average value of 3310 N (Min. 1300 N) and slip resistance R-10; DurationUnit: year; ExpectedLife: 50; Features: See ProductInformation (Technical PDF); Grade: First quality; Manufacturer: bim.gp@porcelanosagrupo.com; ModelNumber: 100214648; ModelReference: Bottega Caliza 59.6x59.6 cm; Name: CeramicTiles_Bottega_Caliza-596x596mm-100214648; NominalHeight: 10.3 mm; NominalLength: 596 mm; NominalWidth: 596 mm; ReplacementCost: n/a; Shape: Squared; Size: 596x596x10.3 mm; Sustainability Performance: See ProductInformation (Technical PDF); WarrantyDescription: Manufacturer warranty, applicable worldwide, with the pertinent national legislation prevailing in all cases and covering at least a 3-year period; all products must have been manufactured and fitted in accordance with the Fabricator's Manual, and have been used and cared for in accordance with the Guide to Use, Cleaning and Care available on the web page www.porcelanosa.com; WarrantyDurationLabor: n/a; WarrantyDurationParts: 3; WarrantyDurationUnit: year; WarrantyGuarantorLabor: n/a; WarrantyGuarantorParts: bim.gp@porcelanosagrupo.com
Type - Pset_CoveringCommon - IsExternal: yes; Reference: n/a; AcousticRating: n/a; Finish: Concrete, Tone Variations, Matte, Rectified; FireRating: A1; FlammabilityRating: Class 0; FragilityRating: n/a; Material: Ceramic; SurfaceSpreadOfFlame: Class 0; ThermalTransmittance: 223.301 kg/K/s3; TotalThickness: 10.3 mm
Type - IFC - IfcExportType: FLOORING; IfcExportAS: IfcCovering
Type - NBS_Data - HasSurfaceRoughness: no; AbrasionResistance: 6: Intense-External Access; BreakingStrength: Average Value: 3310 N (Min. 1300 N); ChemicalResistance: Class 'A' for swimming pools and cleaning products (resists attack); minimum Class 'B' for acids and bases; Collection: STON-KER; CreationDate: 2018/07; Dcof: n/a; FlexuralStrength: >40 N/mm²; FrostResistance: Conforms to ISO 10545-9; Group: BIa; MoistureExpansion: <0.1 mm/m; RampTest: R-10; RecycledContent: >6.5%; Series: Botega; SlipResistanceValuePendulumTestValue: CL1; StainResistance: Class 5: Easy cleaning with water; SurfaceQuality: Without surface defects; ThermalShockResistance: Conforms to ISO 10545–12; UpecC: n/a; UpecE: n/a; UpecP: n/a; UpecU: n/a; WaterAbsorption: E<=0.5%
COBie - AssetIdentifier: n/a; BarCode: n/a; InstallationDate: 1900-12-31T23:59:59; TagNumber: n/a; WarrantyStartDate: 1900-12-31T23:59:59

# IfcWallStandardCase: Basic Wall:PGR_Porcelanosa_CeramicTiles_Bottega_Caliza-800x800mm-100214608, Basic Wall:PGR_Porcelanosa_CeramicTiles_Bottega_Caliza-800x800mm-100214608:213342
In: Level 1
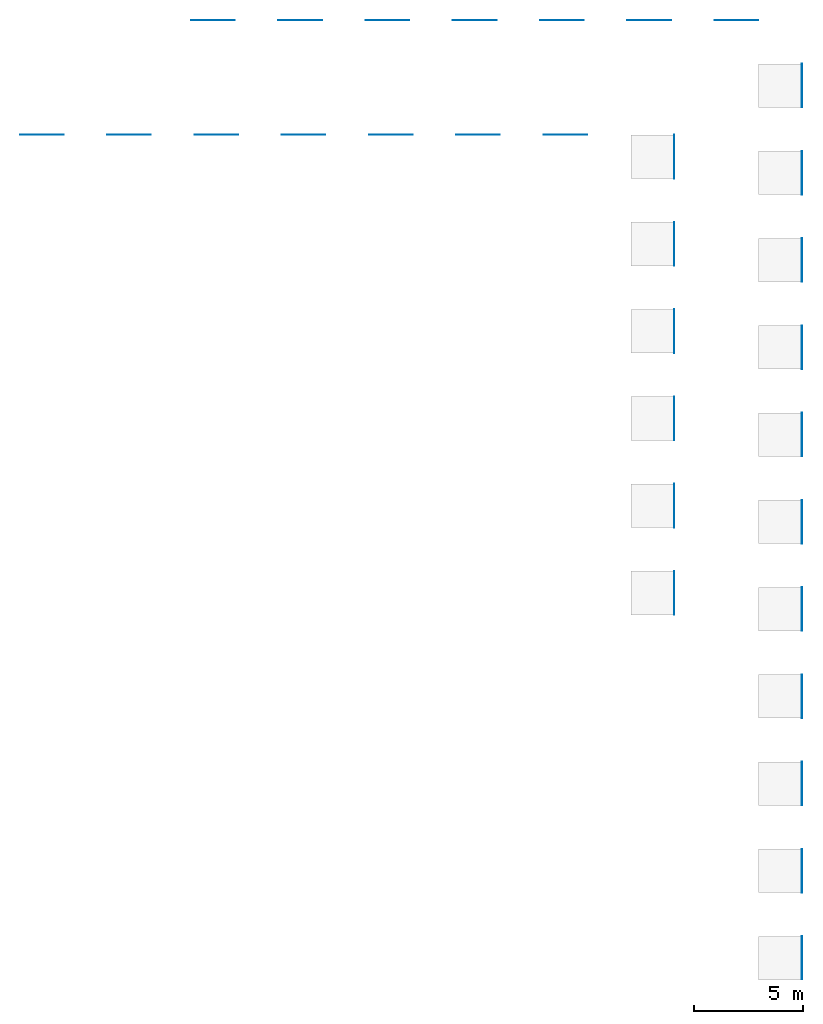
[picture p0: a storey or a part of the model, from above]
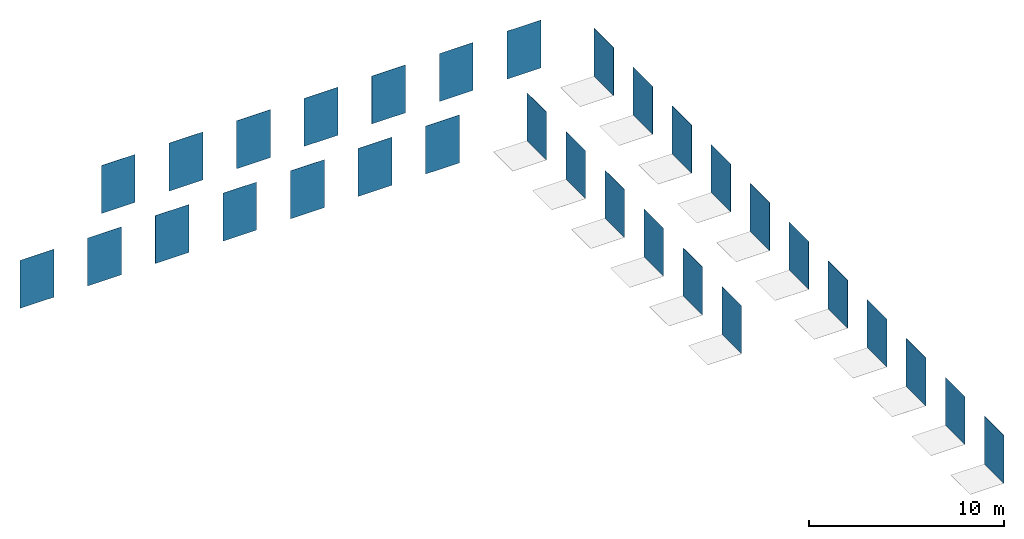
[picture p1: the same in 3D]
Properties of the parts of a building model (IFC2X3), part 3 of 3

# IfcWallStandardCase: Basic Wall:PGR_Porcelanosa_CeramicTiles_Bottega_Caliza-800x800mm-100214608, Basic Wall:PGR_Porcelanosa_CeramicTiles_Bottega_Caliza-800x800mm-100214608:213342
Type - PredefinedType: STANDARD; Material: PGR_Porcelanosa_CeramicTiles_Bottega_Caliza-800x800mm-100214608 11.2 mm
Type - NBS_General - Author: Porcelanosa Group; BIMObjectName: PGR_Porcelanosa_CeramicTiles_Bottega_Caliza-800x800mm-100214608; ManufacturerURL: www.porcelanosa.com; NBSDescription: Ceramic Tiles; NBSReference: 45-80-95/310; ProductInformation: http://calidad.info-grupo.com:8081/GeneraFicha3/PDF?articulo=100214608&lang=EN&un=0; Revision: n/a; Uniclass2015Code: Pr_35_93_96_19; Uniclass2015Title: Ceramic Tiles; Uniclass2015Version: Products v1.5; Version: 1
Type - COBie - AccessibilityPerformance: See ProductInformation (Technical PDF); AssetType: Fixed; Category: Pr_35_93_96_19:Ceramic Tiles; CodePerformance: ISO-13006:2012; UNE-EN 14411:2012; Color: Beige; Constituents: Clays, feldespat and glaze; Description: Rectified Porcelain tiles, BOTEGA series from PORCELANOSA, BEIGE color and MATTE finish, 80x80 cm (11.2 mm thickness), group BIa, according to UNE-EN 14411, water absortion capacity E<=0.5%, flexural strength >40 N/mm², breaking strength with an average value of 3310 N (Min. 1300 N) and slip resistance R-10; DurationUnit: year; ExpectedLife: 50; Features: See ProductInformation (Technical PDF); Grade: First quality; Manufacturer: bim.gp@porcelanosagrupo.com; ModelNumber: 100214608; ModelReference: Bottega Caliza 80x80 cm; Name: CeramicTiles_Bottega_Caliza-800x800mm-100214608; NominalHeight: 11.2 mm; NominalLength: 800 mm; NominalWidth: 800 mm; ReplacementCost: n/a; Shape: Squared; Size: 800x800x11.2 mm; Sustainability Performance: See ProductInformation (Technical PDF); WarrantyDescription: Manufacturer warranty, applicable worldwide, with the pertinent national legislation prevailing in all cases and covering at least a 3-year period; all products must have been manufactured and fitted in accordance with the Fabricator's Manual, and have been used and cared for in accordance with the Guide to Use, Cleaning and Care available on the web page www.porcelanosa.com; WarrantyDurationLabor: n/a; WarrantyDurationParts: 3; WarrantyDurationUnit: year; WarrantyGuarantorLabor: n/a; WarrantyGuarantorParts: bim.gp@porcelanosagrupo.com
Type - Pset_CoveringCommon - IsExternal: yes; Reference: n/a; AcousticRating: n/a; Finish: Concrete, Tone Variations, Matte, Rectified; FireRating: A1; FlammabilityRating: Class 0; FragilityRating: n/a; Material: Ceramic; SurfaceSpreadOfFlame: Class 0; ThermalTransmittance: 205.357 kg/K/s3; TotalThickness: 11.2 mm
Type - IFC - IfcExportType: FLOORING; IfcExportAS: IfcCovering
Type - NBS_Data - HasSurfaceRoughness: no; AbrasionResistance: 6: Intense-External Access; BreakingStrength: Average Value: 3310 N (Min. 1300 N); ChemicalResistance: Class 'A' for swimming pools and cleaning products (resists attack); minimum Class 'B' for acids and bases; Collection: STON-KER; CreationDate: 2018/07; Dcof: n/a; FlexuralStrength: >40 N/mm²; FrostResistance: Conforms to ISO 10545-9; Group: BIa; MoistureExpansion: <0.1 mm/m; RampTest: R-10; RecycledContent: >6.5%; Series: Botega; SlipResistanceValuePendulumTestValue: CL1; StainResistance: Class 5: Easy cleaning with water; SurfaceQuality: Without surface defects; ThermalShockResistance: Conforms to ISO 10545–12; UpecC: n/a; UpecE: n/a; UpecP: n/a; UpecU: n/a; WaterAbsorption: E<=0.5%
COBie - AssetIdentifier: n/a; BarCode: n/a; InstallationDate: 1900-12-31T23:59:59; TagNumber: n/a; WarrantyStartDate: 1900-12-31T23:59:59

# IfcWallStandardCase: Basic Wall:PGR_Porcelanosa_CeramicTiles_Bottega_Caliza_Ant.-596x596mm-100221473, Basic Wall:PGR_Porcelanosa_CeramicTiles_Bottega_Caliza_Ant.-596x596mm-100221473:213352
In: Level 1
Type - PredefinedType: STANDARD; Material: PGR_Porcelanosa_CeramicTiles_Bottega_Caliza_Ant.-596x596mm-100221473 10.3 mm
Type - NBS_General - Author: Porcelanosa Group; BIMObjectName: PGR_Porcelanosa_CeramicTiles_Bottega_Caliza_Ant.-596x596mm-100221473; ManufacturerURL: www.porcelanosa.com; NBSDescription: Ceramic Tiles; NBSReference: 45-80-95/310; ProductInformation: http://calidad.info-grupo.com:8081/GeneraFicha3/PDF?articulo=100221473&lang=EN&un=0; Revision: n/a; Uniclass2015Code: Pr_35_93_96_19; Uniclass2015Title: Ceramic Tiles; Uniclass2015Version: Products v1.5; Version: 1
Type - COBie - AccessibilityPerformance: See ProductInformation (Technical PDF); AssetType: Fixed; Category: Pr_35_93_96_19:Ceramic Tiles; CodePerformance: ISO-13006:2012; UNE-EN 14411:2012; Color: Beige; Constituents: Clays, feldespat and glaze; Description: Rectified Porcelain tiles, BOTEGA series from PORCELANOSA, BEIGE color and MATTE finish, 59.6x59.6 cm (10.3 mm thickness), group BIa, according to UNE-EN 14411, water absortion capacity E<=0.5%, flexural strength >40 N/mm², breaking strength with an average value of 3310 N (Min. 1300 N) and slip resistance R-13; DurationUnit: year; ExpectedLife: 50; Features: See ProductInformation (Technical PDF); Grade: First quality; Manufacturer: bim.gp@porcelanosagrupo.com; ModelNumber: 100221473; ModelReference: Bottega Caliza Ant. 59.6x59.6 cm; Name: CeramicTiles_Bottega_Caliza_Ant.-596x596mm-100221473; NominalHeight: 10.3 mm; NominalLength: 596 mm; NominalWidth: 596 mm; ReplacementCost: n/a; Shape: Squared; Size: 596x596x10.3 mm; Sustainability Performance: See ProductInformation (Technical PDF); WarrantyDescription: Manufacturer warranty, applicable worldwide, with the pertinent national legislation prevailing in all cases and covering at least a 3-year period; all products must have been manufactured and fitted in accordance with the Fabricator's Manual, and have been used and cared for in accordance with the Guide to Use, Cleaning and Care available on the web page www.porcelanosa.com; WarrantyDurationLabor: n/a; WarrantyDurationParts: 3; WarrantyDurationUnit: year; WarrantyGuarantorLabor: n/a; WarrantyGuarantorParts: bim.gp@porcelanosagrupo.com
Type - Pset_CoveringCommon - IsExternal: yes; Reference: n/a; AcousticRating: n/a; Finish: Concrete, Tone Variations, Matte, Non-Slip, Rectified; FireRating: A1; FlammabilityRating: Class 0; FragilityRating: n/a; Material: Ceramic; SurfaceSpreadOfFlame: Class 0; ThermalTransmittance: 223.301 kg/K/s3; TotalThickness: 10.3 mm
Type - IFC - IfcExportType: FLOORING; IfcExportAS: IfcCovering
Type - NBS_Data - HasSurfaceRoughness: no; AbrasionResistance: 6: Intense-External Access; BreakingStrength: Average Value: 3310 N (Min. 1300 N); ChemicalResistance: Class 'A' for swimming pools and cleaning products (resists attack); minimum Class 'B' for acids and bases; Collection: STON-KER; CreationDate: 2018/07; Dcof: >0.42; FlexuralStrength: >40 N/mm²; FrostResistance: Conforms to ISO 10545-9; Group: BIa; MoistureExpansion: <0.1 mm/m; RampTest: R-13; RecycledContent: >6.5%; Series: Botega; SlipResistanceValuePendulumTestValue: CL3; StainResistance: Class 5: Easy cleaning with water; SurfaceQuality: Without surface defects; ThermalShockResistance: Conforms to ISO 10545–12; UpecC: n/a; UpecE: n/a; UpecP: n/a; UpecU: n/a; WaterAbsorption: E<=0.5%
COBie - AssetIdentifier: n/a; BarCode: n/a; InstallationDate: 1900-12-31T23:59:59; TagNumber: n/a; WarrantyStartDate: 1900-12-31T23:59:59

# IfcWallStandardCase: Basic Wall:PGR_Porcelanosa_CeramicTiles_Bottega_Caliza_Ant.-800x800mm-100221502, Basic Wall:PGR_Porcelanosa_CeramicTiles_Bottega_Caliza_Ant.-800x800mm-100221502:213362
In: Level 1
Type - PredefinedType: STANDARD; Material: PGR_Porcelanosa_CeramicTiles_Bottega_Caliza_Ant.-800x800mm-100221502 11.2 mm
Type - NBS_General - Author: Porcelanosa Group; BIMObjectName: PGR_Porcelanosa_CeramicTiles_Bottega_Caliza_Ant.-800x800mm-100221502; ManufacturerURL: www.porcelanosa.com; NBSDescription: Ceramic Tiles; NBSReference: 45-80-95/310; ProductInformation: http://calidad.info-grupo.com:8081/GeneraFicha3/PDF?articulo=100221502&lang=EN&un=0; Revision: n/a; Uniclass2015Code: Pr_35_93_96_19; Uniclass2015Title: Ceramic Tiles; Uniclass2015Version: Products v1.5; Version: 1
Type - COBie - AccessibilityPerformance: See ProductInformation (Technical PDF); AssetType: Fixed; Category: Walls; CodePerformance: ISO-13006:2012; UNE-EN 14411:2012; Color: Beige; Constituents: Clays, feldespat and glaze; Description: Rectified Porcelain tiles, BOTEGA series from PORCELANOSA, BEIGE color and MATTE finish, 80x80 cm (11.2 mm thickness), group BIa, according to UNE-EN 14411, water absortion capacity E<=0.5%, flexural strength >40 N/mm², breaking strength with an average value of 3310 N (Min. 1300 N) and slip resistance R-13; DurationUnit: year; ExpectedLife: 50; Features: See ProductInformation (Technical PDF); Grade: First quality; Manufacturer: bim.gp@porcelanosagrupo.com; ModelNumber: 100221502; ModelReference: Bottega Caliza Ant. 80x80 cm; Name: CeramicTiles_Bottega_Caliza_Ant.-800x800mm-100221502; NominalHeight: 11.2 mm; NominalLength: 800 mm; NominalWidth: 800 mm; ReplacementCost: n/a; Shape: Squared; Size: 800x800x11.2 mm; Sustainability Performance: See ProductInformation (Technical PDF); WarrantyDescription: Manufacturer warranty, applicable worldwide, with the pertinent national legislation prevailing in all cases and covering at least a 3-year period; all products must have been manufactured and fitted in accordance with the Fabricator's Manual, and have been used and cared for in accordance with the Guide to Use, Cleaning and Care available on the web page www.porcelanosa.com; WarrantyDurationLabor: n/a; WarrantyDurationParts: 3; WarrantyDurationUnit: year; WarrantyGuarantorLabor: n/a; WarrantyGuarantorParts: bim.gp@porcelanosagrupo.com
Type - Pset_CoveringCommon - IsExternal: yes; Reference: n/a; AcousticRating: n/a; Finish: Concrete, Tone Variations, Matte, Non-Slip, Rectified; FireRating: A1; FlammabilityRating: Class 0; FragilityRating: n/a; Material: Ceramic; SurfaceSpreadOfFlame: Class 0; ThermalTransmittance: 205.357 kg/K/s3; TotalThickness: 11.2 mm
Type - IFC - IfcExportType: FLOORING; IfcExportAS: IfcCovering
Type - NBS_Data - HasSurfaceRoughness: no; AbrasionResistance: 6: Intense-External Access; BreakingStrength: Average Value: 3310 N (Min. 1300 N); ChemicalResistance: Class 'A' for swimming pools and cleaning products (resists attack); minimum Class 'B' for acids and bases; Collection: STON-KER; CreationDate: 2018/07; Dcof: >0.42; FlexuralStrength: >40 N/mm²; FrostResistance: Conforms to ISO 10545-9; Group: BIa; MoistureExpansion: <0.1 mm/m; RampTest: R-13; RecycledContent: >6.5%; Series: Botega; SlipResistanceValuePendulumTestValue: CL3; StainResistance: Class 5: Easy cleaning with water; SurfaceQuality: Without surface defects; ThermalShockResistance: Conforms to ISO 10545–12; UpecC: n/a; UpecE: n/a; UpecP: n/a; UpecU: n/a; WaterAbsorption: E<=0.5%
COBie - AssetIdentifier: n/a; BarCode: n/a; InstallationDate: 1900-12-31T23:59:59; TagNumber: n/a; WarrantyStartDate: 1900-12-31T23:59:59

# IfcWallStandardCase: Basic Wall:PGR_Porcelanosa_CeramicTiles_Bottega_Topo-1200x1200mm-100227119, Basic Wall:PGR_Porcelanosa_CeramicTiles_Bottega_Topo-1200x1200mm-100227119:213422
In: Level 1
Type - PredefinedType: STANDARD; Material: PGR_Porcelanosa_CeramicTiles_Bottega_Topo-1200x1200mm-100227119 12 mm
Type - NBS_General - Author: Porcelanosa Group; BIMObjectName: PGR_Porcelanosa_CeramicTiles_Bottega_Topo-1200x1200mm-100227119; ManufacturerURL: www.porcelanosa.com; NBSDescription: Ceramic Tiles; NBSReference: 45-80-95/310; ProductInformation: http://calidad.info-grupo.com:8081/GeneraFicha3/PDF?articulo=100227119&lang=EN&un=0; Revision: n/a; Uniclass2015Code: Pr_35_93_96_19; Uniclass2015Title: Ceramic Tiles; Uniclass2015Version: Products v1.5; Version: 1
Type - COBie - AccessibilityPerformance: See ProductInformation (Technical PDF); AssetType: Fixed; Category: Pr_35_93_96_19:Ceramic Tiles; CodePerformance: ISO-13006:2012; UNE-EN 14411:2012; Color: Marron; Constituents: Clays, feldespat and glaze; Description: Rectified Porcelain tiles, BOTEGA series from PORCELANOSA, MARRON color and MATTE finish, 120x120 cm (11.5 mm thickness), group BIa, according to UNE-EN 14411, water absortion capacity E<=0.5%, flexural strength >40 N/mm², breaking strength with an average value of 3310 N (Min. 1300 N) and slip resistance R-10; DurationUnit: year; ExpectedLife: 50; Features: See ProductInformation (Technical PDF); Grade: First quality; Manufacturer: bim.gp@porcelanosagrupo.com; ModelNumber: 100227119; ModelReference: Bottega Topo 120x120 cm; Name: CeramicTiles_Bottega_Topo-1200x1200mm-100227119; NominalHeight: 11.5 mm; NominalLength: 1200 mm; NominalWidth: 1200 mm; ReplacementCost: n/a; Shape: Squared; Size: 1200x1200x11.5 mm; Sustainability Performance: See ProductInformation (Technical PDF); WarrantyDescription: Manufacturer warranty, applicable worldwide, with the pertinent national legislation prevailing in all cases and covering at least a 3-year period; all products must have been manufactured and fitted in accordance with the Fabricator's Manual, and have been used and cared for in accordance with the Guide to Use, Cleaning and Care available on the web page www.porcelanosa.com; WarrantyDurationLabor: n/a; WarrantyDurationParts: 3; WarrantyDurationUnit: year; WarrantyGuarantorLabor: n/a; WarrantyGuarantorParts: bim.gp@porcelanosagrupo.com
Type - Pset_CoveringCommon - IsExternal: yes; Reference: n/a; AcousticRating: n/a; Finish: Concrete, Tone Variations, Matte, Rectified; FireRating: A1; FlammabilityRating: Class 0; FragilityRating: n/a; Material: Ceramic; SurfaceSpreadOfFlame: Class 0; ThermalTransmittance: 200 kg/K/s3; TotalThickness: 11.5 mm
Type - IFC - IfcExportType: FLOORING; IfcExportAS: IfcCovering
Type - NBS_Data - HasSurfaceRoughness: no; AbrasionResistance: 6: Intense-External Access; BreakingStrength: Average Value: 3310 N (Min. 1300 N); ChemicalResistance: Class 'A' for swimming pools and cleaning products (resists attack); minimum Class 'B' for acids and bases; Collection: Porcelanico Tecnico; CreationDate: 2018/07; Dcof: n/a; FlexuralStrength: >40 N/mm²; FrostResistance: Conforms to ISO 10545-9; Group: BIa; MoistureExpansion: <0.1 mm/m; RampTest: R-10; RecycledContent: >6.5%; Series: Botega; SlipResistanceValuePendulumTestValue: CL1; StainResistance: Class 5: Easy cleaning with water; SurfaceQuality: Without surface defects; ThermalShockResistance: Conforms to ISO 10545–12; UpecC: n/a; UpecE: n/a; UpecP: n/a; UpecU: n/a; WaterAbsorption: E<=0.5%
COBie - AssetIdentifier: n/a; BarCode: n/a; InstallationDate: 1900-12-31T23:59:59; TagNumber: n/a; WarrantyStartDate: 1900-12-31T23:59:59

# IfcWallStandardCase: Basic Wall:PGR_Porcelanosa_CeramicTiles_Bottega_Topo-596x596mm-100214662, Basic Wall:PGR_Porcelanosa_CeramicTiles_Bottega_Topo-596x596mm-100214662:213432
In: Level 1
Type - PredefinedType: STANDARD; Material: PGR_Porcelanosa_CeramicTiles_Bottega_Topo-596x596mm-100214662 10.3 mm
Type - NBS_General - Author: Porcelanosa Group; BIMObjectName: PGR_Porcelanosa_CeramicTiles_Bottega_Topo-596x596mm-100214662; ManufacturerURL: www.porcelanosa.com; NBSDescription: Ceramic Tiles; NBSReference: 45-80-95/310; ProductInformation: http://calidad.info-grupo.com:8081/GeneraFicha3/PDF?articulo=100214662&lang=EN&un=0; Revision: n/a; Uniclass2015Code: Pr_35_93_96_19; Uniclass2015Title: Ceramic Tiles; Uniclass2015Version: Products v1.5; Version: 1
Type - COBie - AccessibilityPerformance: See ProductInformation (Technical PDF); AssetType: Fixed; Category: Pr_35_93_96_19:Ceramic Tiles; CodePerformance: ISO-13006:2012; UNE-EN 14411:2012; Color: MarrÓn; Constituents: Clays, feldespat and glaze; Description: Rectified Porcelain tiles, BOTEGA series from PORCELANOSA, MARRÓN color and MATTE finish, 59.6x59.6 cm (10.3 mm thickness), group BIa, according to UNE-EN 14411, water absortion capacity E<=0.5%, flexural strength >40 N/mm², breaking strength with an average value of 3310 N (Min. 1300 N) and slip resistance R-10; DurationUnit: year; ExpectedLife: 50; Features: See ProductInformation (Technical PDF); Grade: First quality; Manufacturer: bim.gp@porcelanosagrupo.com; ModelNumber: 100214662; ModelReference: Bottega Topo 59.6x59.6 cm; Name: CeramicTiles_Bottega_Topo-596x596mm-100214662; NominalHeight: 10.3 mm; NominalLength: 596 mm; NominalWidth: 596 mm; ReplacementCost: n/a; Shape: Squared; Size: 596x596x10.3 mm; Sustainability Performance: See ProductInformation (Technical PDF); WarrantyDescription: Manufacturer warranty, applicable worldwide, with the pertinent national legislation prevailing in all cases and covering at least a 3-year period; all products must have been manufactured and fitted in accordance with the Fabricator's Manual, and have been used and cared for in accordance with the Guide to Use, Cleaning and Care available on the web page www.porcelanosa.com; WarrantyDurationLabor: n/a; WarrantyDurationParts: 3; WarrantyDurationUnit: year; WarrantyGuarantorLabor: n/a; WarrantyGuarantorParts: bim.gp@porcelanosagrupo.com
Type - Pset_CoveringCommon - IsExternal: yes; Reference: n/a; AcousticRating: n/a; Finish: Concrete, Tone Variations, Matte, Rectified; FireRating: A1; FlammabilityRating: Class 0; FragilityRating: n/a; Material: Ceramic; SurfaceSpreadOfFlame: Class 0; ThermalTransmittance: 223.301 kg/K/s3; TotalThickness: 10.3 mm
Type - IFC - IfcExportType: FLOORING; IfcExportAS: IfcCovering
Type - NBS_Data - HasSurfaceRoughness: no; AbrasionResistance: 6: Intense-External Access; BreakingStrength: Average Value: 3310 N (Min. 1300 N); ChemicalResistance: Class 'A' for swimming pools and cleaning products (resists attack); minimum Class 'B' for acids and bases; Collection: STON-KER; CreationDate: 2018/07; Dcof: n/a; FlexuralStrength: >40 N/mm²; FrostResistance: Conforms to ISO 10545-9; Group: BIa; MoistureExpansion: <0.1 mm/m; RampTest: R-10; RecycledContent: >6.5%; Series: Botega; SlipResistanceValuePendulumTestValue: CL1; StainResistance: Class 5: Easy cleaning with water; SurfaceQuality: Without surface defects; ThermalShockResistance: Conforms to ISO 10545–12; UpecC: n/a; UpecE: n/a; UpecP: n/a; UpecU: n/a; WaterAbsorption: E<=0.5%
COBie - AssetIdentifier: n/a; BarCode: n/a; InstallationDate: 1900-12-31T23:59:59; TagNumber: n/a; WarrantyStartDate: 1900-12-31T23:59:59

# IfcWallStandardCase: Basic Wall:PGR_Porcelanosa_CeramicTiles_Bottega_Topo-800x800mm-100214622, Basic Wall:PGR_Porcelanosa_CeramicTiles_Bottega_Topo-800x800mm-100214622:213442
In: Level 1
Type - PredefinedType: STANDARD; Material: PGR_Porcelanosa_CeramicTiles_Bottega_Topo-800x800mm-100214622 11.2 mm
Type - NBS_General - Author: Porcelanosa Group; BIMObjectName: PGR_Porcelanosa_CeramicTiles_Bottega_Topo-800x800mm-100214622; ManufacturerURL: www.porcelanosa.com; NBSDescription: Ceramic Tiles; NBSReference: 45-80-95/310; ProductInformation: http://calidad.info-grupo.com:8081/GeneraFicha3/PDF?articulo=100214622&lang=EN&un=0; Revision: n/a; Uniclass2015Code: Pr_35_93_96_19; Uniclass2015Title: Ceramic Tiles; Uniclass2015Version: Products v1.5; Version: 1
Type - COBie - AccessibilityPerformance: See ProductInformation (Technical PDF); AssetType: Fixed; Category: Pr_35_93_96_19:Ceramic Tiles; CodePerformance: ISO-13006:2012; UNE-EN 14411:2012; Color: MarrÓn; Constituents: Clays, feldespat and glaze; Description: Rectified Porcelain tiles, BOTEGA series from PORCELANOSA, MARRÓN color and MATTE finish, 80x80 cm (11.2 mm thickness), group BIa, according to UNE-EN 14411, water absortion capacity E<=0.5%, flexural strength >40 N/mm², breaking strength with an average value of 3310 N (Min. 1300 N) and slip resistance R-10; DurationUnit: year; ExpectedLife: 50; Features: See ProductInformation (Technical PDF); Grade: First quality; Manufacturer: bim.gp@porcelanosagrupo.com; ModelNumber: 100214622; ModelReference: Bottega Topo 80x80 cm; Name: CeramicTiles_Bottega_Topo-800x800mm-100214622; NominalHeight: 11.2 mm; NominalLength: 800 mm; NominalWidth: 800 mm; ReplacementCost: n/a; Shape: Squared; Size: 800x800x11.2 mm; Sustainability Performance: See ProductInformation (Technical PDF); WarrantyDescription: Manufacturer warranty, applicable worldwide, with the pertinent national legislation prevailing in all cases and covering at least a 3-year period; all products must have been manufactured and fitted in accordance with the Fabricator's Manual, and have been used and cared for in accordance with the Guide to Use, Cleaning and Care available on the web page www.porcelanosa.com; WarrantyDurationLabor: n/a; WarrantyDurationParts: 3; WarrantyDurationUnit: year; WarrantyGuarantorLabor: n/a; WarrantyGuarantorParts: bim.gp@porcelanosagrupo.com
Type - Pset_CoveringCommon - IsExternal: yes; Reference: n/a; AcousticRating: n/a; Finish: Concrete, Tone Variations, Matte, Rectified; FireRating: A1; FlammabilityRating: Class 0; FragilityRating: n/a; Material: Ceramic; SurfaceSpreadOfFlame: Class 0; ThermalTransmittance: 205.357 kg/K/s3; TotalThickness: 11.2 mm
Type - IFC - IfcExportType: FLOORING; IfcExportAS: IfcCovering
Type - NBS_Data - HasSurfaceRoughness: no; AbrasionResistance: 6: Intense-External Access; BreakingStrength: Average Value: 3310 N (Min. 1300 N); ChemicalResistance: Class 'A' for swimming pools and cleaning products (resists attack); minimum Class 'B' for acids and bases; Collection: STON-KER; CreationDate: 2018/07; Dcof: n/a; FlexuralStrength: >40 N/mm²; FrostResistance: Conforms to ISO 10545-9; Group: BIa; MoistureExpansion: <0.1 mm/m; RampTest: R-10; RecycledContent: >6.5%; Series: Botega; SlipResistanceValuePendulumTestValue: CL1; StainResistance: Class 5: Easy cleaning with water; SurfaceQuality: Without surface defects; ThermalShockResistance: Conforms to ISO 10545–12; UpecC: n/a; UpecE: n/a; UpecP: n/a; UpecU: n/a; WaterAbsorption: E<=0.5%
COBie - AssetIdentifier: n/a; BarCode: n/a; InstallationDate: 1900-12-31T23:59:59; TagNumber: n/a; WarrantyStartDate: 1900-12-31T23:59:59

# IfcWallStandardCase: Basic Wall:PGR_Porcelanosa_CeramicTiles_Bottega_Topo_Ant.-596x596mm-100221449, Basic Wall:PGR_Porcelanosa_CeramicTiles_Bottega_Topo_Ant.-596x596mm-100221449:213452
In: Level 1
Type - PredefinedType: STANDARD; Material: PGR_Porcelanosa_CeramicTiles_Bottega_Topo_Ant.-596x596mm-100221449 10.3 mm
Type - NBS_General - Author: Porcelanosa Group; BIMObjectName: PGR_Porcelanosa_CeramicTiles_Bottega_Topo_Ant.-596x596mm-100221449; ManufacturerURL: www.porcelanosa.com; NBSDescription: Ceramic Tiles; NBSReference: 45-80-95/310; ProductInformation: http://calidad.info-grupo.com:8081/GeneraFicha3/PDF?articulo=100221449&lang=EN&un=0; Revision: n/a; Uniclass2015Code: Pr_35_93_96_19; Uniclass2015Title: Ceramic Tiles; Uniclass2015Version: Products v1.5; Version: 1
Type - COBie - AccessibilityPerformance: See ProductInformation (Technical PDF); AssetType: Fixed; Category: Walls; CodePerformance: ISO-13006:2012; UNE-EN 14411:2012; Color: MarrÓn; Constituents: Clays, feldespat and glaze; Description: Rectified Porcelain tiles, BOTEGA series from PORCELANOSA, MARRÓN color and MATTE finish, 59.6x59.6 cm (10.3 mm thickness), group BIa, according to UNE-EN 14411, water absortion capacity E<=0.5%, flexural strength >40 N/mm², breaking strength with an average value of 3310 N (Min. 1300 N) and slip resistance R-13; DurationUnit: year; ExpectedLife: 50; Features: See ProductInformation (Technical PDF); Grade: First quality; Manufacturer: bim.gp@porcelanosagrupo.com; ModelNumber: 100221449; ModelReference: Bottega Topo Ant. 59.6x59.6 cm; Name: CeramicTiles_Bottega_Topo_Ant.-596x596mm-100221449; NominalHeight: 10.3 mm; NominalLength: 596 mm; NominalWidth: 596 mm; ReplacementCost: n/a; Shape: Squared; Size: 596x596x10.3 mm; Sustainability Performance: See ProductInformation (Technical PDF); WarrantyDescription: Manufacturer warranty, applicable worldwide, with the pertinent national legislation prevailing in all cases and covering at least a 3-year period; all products must have been manufactured and fitted in accordance with the Fabricator's Manual, and have been used and cared for in accordance with the Guide to Use, Cleaning and Care available on the web page www.porcelanosa.com; WarrantyDurationLabor: n/a; WarrantyDurationParts: 3; WarrantyDurationUnit: year; WarrantyGuarantorLabor: n/a; WarrantyGuarantorParts: bim.gp@porcelanosagrupo.com
Type - Pset_CoveringCommon - IsExternal: yes; Reference: n/a; AcousticRating: n/a; Finish: Concrete, Tone Variations, Matte, Non-Slip, Rectified; FireRating: A1; FlammabilityRating: Class 0; FragilityRating: n/a; Material: Ceramic; SurfaceSpreadOfFlame: Class 0; ThermalTransmittance: 223.301 kg/K/s3; TotalThickness: 10.3 mm
Type - IFC - IfcExportType: FLOORING; IfcExportAS: IfcCovering
Type - NBS_Data - HasSurfaceRoughness: no; AbrasionResistance: 6: Intense-External Access; BreakingStrength: Average Value: 3310 N (Min. 1300 N); ChemicalResistance: Class 'A' for swimming pools and cleaning products (resists attack); minimum Class 'B' for acids and bases; Collection: STON-KER; CreationDate: 2018/07; Dcof: >0.42; FlexuralStrength: >40 N/mm²; FrostResistance: Conforms to ISO 10545-9; Group: BIa; MoistureExpansion: <0.1 mm/m; RampTest: R-13; RecycledContent: >6.5%; Series: Botega; SlipResistanceValuePendulumTestValue: CL3; StainResistance: Class 5: Easy cleaning with water; SurfaceQuality: Without surface defects; ThermalShockResistance: Conforms to ISO 10545–12; UpecC: n/a; UpecE: n/a; UpecP: n/a; UpecU: n/a; WaterAbsorption: E<=0.5%
COBie - AssetIdentifier: n/a; BarCode: n/a; InstallationDate: 1900-12-31T23:59:59; TagNumber: n/a; WarrantyStartDate: 1900-12-31T23:59:59

# IfcWallStandardCase: Basic Wall:PGR_Porcelanosa_CeramicTiles_Bottega_Topo_Ant.-800x800mm-100221465, Basic Wall:PGR_Porcelanosa_CeramicTiles_Bottega_Topo_Ant.-800x800mm-100221465:213462
In: Level 1
Type - PredefinedType: STANDARD; Material: PGR_Porcelanosa_CeramicTiles_Bottega_Topo_Ant.-800x800mm-100221465 11.2 mm
Type - NBS_General - Author: Porcelanosa Group; BIMObjectName: PGR_Porcelanosa_CeramicTiles_Bottega_Topo_Ant.-800x800mm-100221465; ManufacturerURL: www.porcelanosa.com; NBSDescription: Ceramic Tiles; NBSReference: 45-80-95/310; ProductInformation: http://calidad.info-grupo.com:8081/GeneraFicha3/PDF?articulo=100221465&lang=EN&un=0; Revision: n/a; Uniclass2015Code: Pr_35_93_96_19; Uniclass2015Title: Ceramic Tiles; Uniclass2015Version: Products v1.5; Version: 1
Type - COBie - AccessibilityPerformance: See ProductInformation (Technical PDF); AssetType: Fixed; Category: Walls; CodePerformance: ISO-13006:2012; UNE-EN 14411:2012; Color: MarrÓn; Constituents: Clays, feldespat and glaze; Description: Rectified Porcelain tiles, BOTEGA series from PORCELANOSA, MARRÓN color and MATTE finish, 80x80 cm (11.2 mm thickness), group BIa, according to UNE-EN 14411, water absortion capacity E<=0.5%, flexural strength >40 N/mm², breaking strength with an average value of 3310 N (Min. 1300 N) and slip resistance R-13; DurationUnit: year; ExpectedLife: 50; Features: See ProductInformation (Technical PDF); Grade: First quality; Manufacturer: bim.gp@porcelanosagrupo.com; ModelNumber: 100221465; ModelReference: Bottega Topo Ant. 80x80 cm; Name: CeramicTiles_Bottega_Topo_Ant.-800x800mm-100221465; NominalHeight: 11.2 mm; NominalLength: 800 mm; NominalWidth: 800 mm; ReplacementCost: n/a; Shape: Squared; Size: 800x800x11.2 mm; Sustainability Performance: See ProductInformation (Technical PDF); WarrantyDescription: Manufacturer warranty, applicable worldwide, with the pertinent national legislation prevailing in all cases and covering at least a 3-year period; all products must have been manufactured and fitted in accordance with the Fabricator's Manual, and have been used and cared for in accordance with the Guide to Use, Cleaning and Care available on the web page www.porcelanosa.com; WarrantyDurationLabor: n/a; WarrantyDurationParts: 3; WarrantyDurationUnit: year; WarrantyGuarantorLabor: n/a; WarrantyGuarantorParts: bim.gp@porcelanosagrupo.com
Type - Pset_CoveringCommon - IsExternal: yes; Reference: n/a; AcousticRating: n/a; Finish: Concrete, Tone Variations, Matte, Non-Slip, Rectified; FireRating: A1; FlammabilityRating: Class 0; FragilityRating: n/a; Material: Ceramic; SurfaceSpreadOfFlame: Class 0; ThermalTransmittance: 205.357 kg/K/s3; TotalThickness: 11.2 mm
Type - IFC - IfcExportType: FLOORING; IfcExportAS: IfcCovering
Type - NBS_Data - HasSurfaceRoughness: no; AbrasionResistance: 6: Intense-External Access; BreakingStrength: Average Value: 3310 N (Min. 1300 N); ChemicalResistance: Class 'A' for swimming pools and cleaning products (resists attack); minimum Class 'B' for acids and bases; Collection: STON-KER; CreationDate: 2018/07; Dcof: >0.42; FlexuralStrength: >40 N/mm²; FrostResistance: Conforms to ISO 10545-9; Group: BIa; MoistureExpansion: <0.1 mm/m; RampTest: R-13; RecycledContent: >6.5%; Series: Botega; SlipResistanceValuePendulumTestValue: CL3; StainResistance: Class 5: Easy cleaning with water; SurfaceQuality: Without surface defects; ThermalShockResistance: Conforms to ISO 10545–12; UpecC: n/a; UpecE: n/a; UpecP: n/a; UpecU: n/a; WaterAbsorption: E<=0.5%
COBie - AssetIdentifier: n/a; BarCode: n/a; InstallationDate: 1900-12-31T23:59:59; TagNumber: n/a; WarrantyStartDate: 1900-12-31T23:59:59

# IfcWallStandardCase: Basic Wall:PGR_Porcelanosa_CeramicTiles_Line_Pekin_Bottega_Acero-450x1200mm-100226494, Basic Wall:PGR_Porcelanosa_CeramicTiles_Line_Pekin_Bottega_Acero-450x1200mm-100226494:213469
In: Level 1
Type - PredefinedType: STANDARD; Material: PGR_Porcelanosa_CeramicTiles_Line_Pekin_Bottega_Acero-450x1200mm-100226494 10.4 mm
Type - NBS_General - Author: Porcelanosa Group; BIMObjectName: PGR_Porcelanosa_CeramicTiles_Line_Pekin_Bottega_Acero-450x1200mm-100226494; ManufacturerURL: www.porcelanosa.com; NBSDescription: Ceramic Tiles; NBSReference: 45-80-95/310; ProductInformation: http://calidad.info-grupo.com:8081/GeneraFicha3/PDF?articulo=100226494&lang=EN&un=0; Revision: n/a; Uniclass2015Code: Pr_35_93_96_19; Uniclass2015Title: Ceramic Tiles; Uniclass2015Version: Products v1.5; Version: 1
Type - COBie - AccessibilityPerformance: See ProductInformation (Technical PDF); AssetType: Fixed; Category: Walls; CodePerformance: ISO-13006:2012; UNE-EN 14411:2012; Color: Gris; Constituents: Clays, feldespat and glaze; Description: Rectified Monoporous, BOTEGA series from PORCELANOSA, GRIS color and MATTE finish, 45x120 cm (10 mm thickness), group BIII, according to UNE-EN 14411, water absortion capacity 10%<=E<=20%, flexural strength >23 N/mm² and breaking strength with an average value of 1337 N (Min. 600 N); DurationUnit: year; ExpectedLife: 50; Features: See ProductInformation (Technical PDF); Grade: First quality; Manufacturer: bim.gp@porcelanosagrupo.com; ModelNumber: 100226494; ModelReference: Line Pekin Bottega Acero 45x120 cm; Name: CeramicTiles_Line_Pekin_Bottega_Acero-450x1200mm-100226494; NominalHeight: 10 mm; NominalLength: 1200 mm; NominalWidth: 450 mm; ReplacementCost: n/a; Shape: Rectangular; Size: 450x1200x10 mm; Sustainability Performance: See ProductInformation (Technical PDF); WarrantyDescription: Manufacturer warranty, applicable worldwide, with the pertinent national legislation prevailing in all cases and covering at least a 3-year period; all products must have been manufactured and fitted in accordance with the Fabricator's Manual, and have been used and cared for in accordance with the Guide to Use, Cleaning and Care available on the web page www.porcelanosa.com; WarrantyDurationLabor: n/a; WarrantyDurationParts: 3; WarrantyDurationUnit: year; WarrantyGuarantorLabor: n/a; WarrantyGuarantorParts: bim.gp@porcelanosagrupo.com
Type - Pset_CoveringCommon - Reference: n/a; IsExternal: no; AcousticRating: n/a; Finish: Tone Variations, Matte, Rectified, Stone; FireRating: A1; FlammabilityRating: Class 0; FragilityRating: n/a; Material: Ceramic; SurfaceSpreadOfFlame: Class 0; ThermalTransmittance: 230 kg/K/s3; TotalThickness: 10 mm
Type - IFC - IfcExportType: CLADDING; IfcExportAS: IfcCovering
Type - NBS_Data - HasSurfaceRoughness: no; AbrasionResistance: 1: Wall Tiles; BreakingStrength: Average Value: 1337 N (Min. 600 N); ChemicalResistance: Class 'A' for swimming pools and cleaning products (resists attack); minimum Class 'B' for acids and bases; Collection: Revestimiento Ceramico Rectificado; CreationDate: 2018/07; Dcof: n/a; FlexuralStrength: >23 N/mm²; FrostResistance: n/a; Group: BIII; MoistureExpansion: <0.1 mm/m; RampTest: n/a; RecycledContent: >18%; Series: Botega; SlipResistanceValuePendulumTestValue: n/a; StainResistance: Class 5: Easy cleaning with water; SurfaceQuality: Without surface defects; ThermalShockResistance: Conforms to ISO 10545–12; UpecC: n/a; UpecE: n/a; UpecP: n/a; UpecU: n/a; WaterAbsorption: 10%<=E<=20%
COBie - AssetIdentifier: n/a; BarCode: n/a; InstallationDate: 1900-12-31T23:59:59; TagNumber: n/a; WarrantyStartDate: 1900-12-31T23:59:59

# IfcWallStandardCase: Basic Wall:PGR_Porcelanosa_CeramicTiles_Line_Pekin_Bottega_Caliza-450x1200mm-100226503, Basic Wall:PGR_Porcelanosa_CeramicTiles_Line_Pekin_Bottega_Caliza-450x1200mm-100226503:213470
In: Level 1
Type - PredefinedType: STANDARD; Material: PGR_Porcelanosa_CeramicTiles_Line_Pekin_Bottega_Caliza-450X1200mm-100226503 10.4 mm
Type - NBS_General - Author: Porcelanosa Group; BIMObjectName: PGR_Porcelanosa_CeramicTiles_Line_Pekin_Bottega_Caliza-450x1200mm-100226503; ManufacturerURL: www.porcelanosa.com; NBSDescription: Ceramic Tiles; NBSReference: 45-80-95/310; ProductInformation: http://calidad.info-grupo.com:8081/GeneraFicha3/PDF?articulo=100226503&lang=EN&un=0; Revision: n/a; Uniclass2015Code: Pr_35_93_96_19; Uniclass2015Title: Ceramic Tiles; Uniclass2015Version: Products v1.5; Version: 1
Type - COBie - AccessibilityPerformance: See ProductInformation (Technical PDF); AssetType: Fixed; Category: Pr_35_93_96_19:Ceramic Tiles; CodePerformance: ISO-13006:2012; UNE-EN 14411:2012; Color: Beige; Constituents: Clays, feldespat and glaze; Description: Rectified Monoporous, BOTEGA series from PORCELANOSA, BEIGE color and MATTE finish, 45x120 cm (10 mm thickness), group BIII, according to UNE-EN 14411, water absortion capacity 10%<=E<=20%, flexural strength >23 N/mm² and breaking strength with an average value of 1337 N (Min. 600 N); DurationUnit: year; ExpectedLife: 50; Features: See ProductInformation (Technical PDF); Grade: First quality; Manufacturer: bim.gp@porcelanosagrupo.com; ModelNumber: 100226503; ModelReference: Line Pekin Bottega Caliza 45x120 cm; Name: CeramicTiles_Line_Pekin_Bottega_Caliza-450x1200mm-100226503; NominalHeight: 10 mm; NominalLength: 1200 mm; NominalWidth: 450 mm; ReplacementCost: n/a; Shape: Rectangular; Size: 450x1200x10 mm; Sustainability Performance: See ProductInformation (Technical PDF); WarrantyDescription: Manufacturer warranty, applicable worldwide, with the pertinent national legislation prevailing in all cases and covering at least a 3-year period; all products must have been manufactured and fitted in accordance with the Fabricator's Manual, and have been used and cared for in accordance with the Guide to Use, Cleaning and Care available on the web page www.porcelanosa.com; WarrantyDurationLabor: n/a; WarrantyDurationParts: 3; WarrantyDurationUnit: year; WarrantyGuarantorLabor: n/a; WarrantyGuarantorParts: bim.gp@porcelanosagrupo.com
Type - Pset_CoveringCommon - Reference: n/a; IsExternal: no; AcousticRating: n/a; Finish: Tone Variations, Matte, Rectified, Stone; FireRating: A1; FlammabilityRating: Class 0; FragilityRating: n/a; Material: Ceramic; SurfaceSpreadOfFlame: Class 0; ThermalTransmittance: 230 kg/K/s3; TotalThickness: 10 mm
Type - IFC - IfcExportType: CLADDING; IfcExportAS: IfcCovering
Type - NBS_Data - HasSurfaceRoughness: no; AbrasionResistance: 1: Wall Tiles; BreakingStrength: Average Value: 1337 N (Min. 600 N); ChemicalResistance: Class 'A' for swimming pools and cleaning products (resists attack); minimum Class 'B' for acids and bases; Collection: Revestimiento Ceramico Rectificado; CreationDate: 2018/07; Dcof: n/a; FlexuralStrength: >23 N/mm²; FrostResistance: n/a; Group: BIII; MoistureExpansion: <0.1 mm/m; RampTest: n/a; RecycledContent: >18%; Series: Botega; SlipResistanceValuePendulumTestValue: n/a; StainResistance: Class 5: Easy cleaning with water; SurfaceQuality: Without surface defects; ThermalShockResistance: Conforms to ISO 10545–12; UpecC: n/a; UpecE: n/a; UpecP: n/a; UpecU: n/a; WaterAbsorption: 10%<=E<=20%
COBie - AssetIdentifier: n/a; BarCode: n/a; InstallationDate: 1900-12-31T23:59:59; TagNumber: n/a; WarrantyStartDate: 1900-12-31T23:59:59

# IfcWallStandardCase: Basic Wall:PGR_Porcelanosa_CeramicTiles_Spiga_Bottega_Acero-316x592mm-100225056, Basic Wall:PGR_Porcelanosa_CeramicTiles_Spiga_Bottega_Acero-316x592mm-100225056:218951
In: Level 1
Type - PredefinedType: STANDARD; Material: PGR_Porcelanosa_CeramicTiles_Spiga_Bottega_Acero-316x592mm-100225056 11.3 mm
Type - NBS_General - Author: Porcelanosa Group; BIMObjectName: PGR_Porcelanosa_CeramicTiles_Spiga_Bottega_Acero-316x592mm-100225056; ManufacturerURL: www.porcelanosa.com; NBSDescription: Ceramic Tiles; NBSReference: 45-80-95/310; ProductInformation: http://calidad.info-grupo.com:8081/GeneraFicha3/PDF?articulo=100225056&lang=EN&un=0; Revision: n/a; Uniclass2015Code: Pr_35_93_96_19; Uniclass2015Title: Ceramic Tiles; Uniclass2015Version: Products v1.5; Version: 1
Type - COBie - AccessibilityPerformance: See ProductInformation (Technical PDF); AssetType: Fixed; Category: Pr_35_93_96_19:Ceramic Tiles; CodePerformance: ISO-13006:2012; UNE-EN 14411:2012; Color: Gris; Constituents: Clays, feldespat and glaze; Description: Monoporous, BOTEGA series from PORCELANOSA, GRIS color and MATTE finish, 31.6x59.2 cm (8.7 mm thickness), group BIII, according to UNE-EN 14411, water absortion capacity 10%<=E<=20%, flexural strength >23 N/mm² and breaking strength with an average value of 1337 N (Min. 600 N); DurationUnit: year; ExpectedLife: 50; Features: See ProductInformation (Technical PDF); Grade: First quality; Manufacturer: bim.gp@porcelanosagrupo.com; ModelNumber: 100225056; ModelReference: Spiga Bottega Acero 31.6x59.2 cm; Name: CeramicTiles_Spiga_Bottega_Acero-316x592mm-100225056; NominalHeight: 8.7 mm; NominalLength: 592 mm; NominalWidth: 316 mm; ReplacementCost: n/a; Shape: Rectangular; Size: 316x592x8.7 mm; Sustainability Performance: See ProductInformation (Technical PDF); WarrantyDescription: Manufacturer warranty, applicable worldwide, with the pertinent national legislation prevailing in all cases and covering at least a 3-year period; all products must have been manufactured and fitted in accordance with the Fabricator's Manual, and have been used and cared for in accordance with the Guide to Use, Cleaning and Care available on the web page www.porcelanosa.com; WarrantyDurationLabor: n/a; WarrantyDurationParts: 3; WarrantyDurationUnit: year; WarrantyGuarantorLabor: n/a; WarrantyGuarantorParts: bim.gp@porcelanosagrupo.com
Type - Pset_CoveringCommon - Reference: n/a; IsExternal: no; AcousticRating: n/a; Finish: Tone Variations, Matte, Stone; FireRating: A1; FlammabilityRating: Class 0; FragilityRating: n/a; Material: Ceramic; SurfaceSpreadOfFlame: Class 0; ThermalTransmittance: 264.368 kg/K/s3; TotalThickness: 8.7 mm
Type - IFC - IfcExportType: CLADDING; IfcExportAS: IfcCovering
Type - NBS_Data - HasSurfaceRoughness: no; AbrasionResistance: 1: Wall Tiles; BreakingStrength: Average Value: 1337 N (Min. 600 N); ChemicalResistance: Class 'A' for swimming pools and cleaning products (resists attack); minimum Class 'B' for acids and bases; Collection: Revestimiento Ceramico; CreationDate: 2018/07; Dcof: n/a; FlexuralStrength: >23 N/mm²; FrostResistance: n/a; Group: BIII; MoistureExpansion: <0.1 mm/m; RampTest: n/a; RecycledContent: >18%; Series: Botega; SlipResistanceValuePendulumTestValue: n/a; StainResistance: Class 5: Easy cleaning with water; SurfaceQuality: Without surface defects; ThermalShockResistance: Conforms to ISO 10545–12; UpecC: n/a; UpecE: n/a; UpecP: n/a; UpecU: n/a; WaterAbsorption: 10%<=E<=20%
COBie - AssetIdentifier: n/a; BarCode: n/a; InstallationDate: 1900-12-31T23:59:59; TagNumber: n/a; WarrantyStartDate: 1900-12-31T23:59:59

# IfcWallStandardCase: Basic Wall:PGR_Porcelanosa_CeramicTiles_Spiga_Bottega_Acero-450x1200mm-100214812, Basic Wall:PGR_Porcelanosa_CeramicTiles_Spiga_Bottega_Acero-450x1200mm-100214812:213471
In: Level 1
Type - PredefinedType: STANDARD; Material: PGR_Porcelanosa_CeramicTiles_Spiga_Bottega_Acero-450x1200mm-100214812 10.1 mm
Type - NBS_General - Author: Porcelanosa Group; BIMObjectName: PGR_Porcelanosa_CeramicTiles_Spiga_Bottega_Acero-450x1200mm-100214812; ManufacturerURL: www.porcelanosa.com; NBSDescription: Ceramic Tiles; NBSReference: 45-80-95/310; ProductInformation: http://calidad.info-grupo.com:8081/GeneraFicha3/PDF?articulo=100214812&lang=EN&un=0; Revision: n/a; Uniclass2015Code: Pr_35_93_96_19; Uniclass2015Title: Ceramic Tiles; Uniclass2015Version: Products v1.5; Version: 1
Type - COBie - AccessibilityPerformance: See ProductInformation (Technical PDF); AssetType: Fixed; Category: Pr_35_93_96_19:Ceramic Tiles; CodePerformance: ISO-13006:2012; UNE-EN 14411:2012; Color: n/a; Constituents: Clays, feldespat and glaze; Description: Monoporous, BOTEGA series from PORCELANOSA, 45x120 cm (10 mm thickness), group BIII, according to UNE-EN 14411, water absortion capacity 10%<=E<=20%, flexural strength >23 N/mm² and breaking strength with an average value of 1337 N (Min. 600 N); DurationUnit: year; ExpectedLife: 50; Features: See ProductInformation (Technical PDF); Grade: First quality; Manufacturer: bim.gp@porcelanosagrupo.com; ModelNumber: 100214812; ModelReference: Spiga Bottega Acero 45x120 cm; Name: CeramicTiles_Spiga_Bottega_Acero-450x1200mm-100214812; NominalHeight: 10 mm; NominalLength: 1200 mm; NominalWidth: 450 mm; ReplacementCost: n/a; Shape: Rectangular; Size: 450x1200x10 mm; Sustainability Performance: See ProductInformation (Technical PDF); WarrantyDescription: Manufacturer warranty, applicable worldwide, with the pertinent national legislation prevailing in all cases and covering at least a 3-year period; all products must have been manufactured and fitted in accordance with the Fabricator's Manual, and have been used and cared for in accordance with the Guide to Use, Cleaning and Care available on the web page www.porcelanosa.com; WarrantyDurationLabor: n/a; WarrantyDurationParts: 3; WarrantyDurationUnit: year; WarrantyGuarantorLabor: n/a; WarrantyGuarantorParts: bim.gp@porcelanosagrupo.com
Type - Pset_CoveringCommon - Reference: n/a; IsExternal: no; AcousticRating: n/a; Finish: Relief; FireRating: A1; FlammabilityRating: Class 0; FragilityRating: n/a; Material: Ceramic; SurfaceSpreadOfFlame: Class 0; ThermalTransmittance: 230 kg/K/s3; TotalThickness: 10 mm
Type - IFC - IfcExportType: CLADDING; IfcExportAS: IfcCovering
Type - NBS_Data - AbrasionResistance: n/a; BreakingStrength: Average Value: 1337 N (Min. 600 N); ChemicalResistance: Class 'A' for swimming pools and cleaning products (resists attack); minimum Class 'B' for acids and bases; Collection: Revestimiento Ceramico Rectificado; CreationDate: 2018/07; Dcof: n/a; FlexuralStrength: >23 N/mm²; FrostResistance: n/a; Group: BIII; HasSurfaceRoughness: yes; MoistureExpansion: <0.1 mm/m; RampTest: n/a; RecycledContent: >18%; Series: Botega; SlipResistanceValuePendulumTestValue: n/a; StainResistance: Class 5: Easy cleaning with water; SurfaceQuality: Without surface defects; ThermalShockResistance: Conforms to ISO 10545–12; UpecC: n/a; UpecE: n/a; UpecP: n/a; UpecU: n/a; WaterAbsorption: 10%<=E<=20%
COBie - AssetIdentifier: n/a; BarCode: n/a; InstallationDate: 1900-12-31T23:59:59; TagNumber: n/a; WarrantyStartDate: 1900-12-31T23:59:59

# IfcWallStandardCase: Basic Wall:PGR_Porcelanosa_CeramicTiles_Spiga_Bottega_Caliza-316x592mm-100225104, Basic Wall:PGR_Porcelanosa_CeramicTiles_Spiga_Bottega_Caliza-316x592mm-100225104:218954
In: Level 1
Type - PredefinedType: STANDARD; Material: PGR_Porcelanosa_CeramicTiles_Spiga_Bottega_Caliza-316x592mm-100225104 11.3 mm
Type - NBS_General - Author: Porcelanosa Group; BIMObjectName: PGR_Porcelanosa_CeramicTiles_Spiga_Bottega_Caliza-316x592mm-100225104; ManufacturerURL: www.porcelanosa.com; NBSDescription: Ceramic Tiles; NBSReference: 45-80-95/310; ProductInformation: http://calidad.info-grupo.com:8081/GeneraFicha3/PDF?articulo=100225104&lang=EN&un=0; Revision: n/a; Uniclass2015Code: Pr_35_93_96_19; Uniclass2015Title: Ceramic Tiles; Uniclass2015Version: Products v1.5; Version: 1
Type - COBie - AccessibilityPerformance: See ProductInformation (Technical PDF); AssetType: Fixed; Category: Pr_35_93_96_19:Ceramic Tiles; CodePerformance: ISO-13006:2012; UNE-EN 14411:2012; Color: Beige; Constituents: Clays, feldespat and glaze; Description: Monoporous, BOTEGA series from PORCELANOSA, BEIGE color and MATTE finish, 31.6x59.2 cm (8.7 mm thickness), group BIII, according to UNE-EN 14411, water absortion capacity 10%<=E<=20%, flexural strength >23 N/mm² and breaking strength with an average value of 1337 N (Min. 600 N); DurationUnit: year; ExpectedLife: 50; Features: See ProductInformation (Technical PDF); Grade: First quality; Manufacturer: bim.gp@porcelanosagrupo.com; ModelNumber: 100225104; ModelReference: Spiga Bottega Caliza 31.6x59.2 cm; Name: CeramicTiles_Spiga_Bottega_Caliza-316x592mm-100225104; NominalHeight: 8.7 mm; NominalLength: 592 mm; NominalWidth: 316 mm; ReplacementCost: n/a; Shape: Rectangular; Size: 316x592x8.7 mm; Sustainability Performance: See ProductInformation (Technical PDF); WarrantyDescription: Manufacturer warranty, applicable worldwide, with the pertinent national legislation prevailing in all cases and covering at least a 3-year period; all products must have been manufactured and fitted in accordance with the Fabricator's Manual, and have been used and cared for in accordance with the Guide to Use, Cleaning and Care available on the web page www.porcelanosa.com; WarrantyDurationLabor: n/a; WarrantyDurationParts: 3; WarrantyDurationUnit: year; WarrantyGuarantorLabor: n/a; WarrantyGuarantorParts: bim.gp@porcelanosagrupo.com
Type - Pset_CoveringCommon - Reference: n/a; IsExternal: no; AcousticRating: n/a; Finish: Tone Variations, Matte, Stone; FireRating: A1; FlammabilityRating: Class 0; FragilityRating: n/a; Material: Ceramic; SurfaceSpreadOfFlame: Class 0; ThermalTransmittance: 264.368 kg/K/s3; TotalThickness: 8.7 mm
Type - IFC - IfcExportType: CLADDING; IfcExportAS: IfcCovering
Type - NBS_Data - HasSurfaceRoughness: no; AbrasionResistance: 1: Wall Tiles; BreakingStrength: Average Value: 1337 N (Min. 600 N); ChemicalResistance: Class 'A' for swimming pools and cleaning products (resists attack); minimum Class 'B' for acids and bases; Collection: Revestimiento Ceramico; CreationDate: 2018/07; Dcof: n/a; FlexuralStrength: >23 N/mm²; FrostResistance: n/a; Group: BIII; MoistureExpansion: <0.1 mm/m; RampTest: n/a; RecycledContent: >18%; Series: Botega; SlipResistanceValuePendulumTestValue: n/a; StainResistance: Class 5: Easy cleaning with water; SurfaceQuality: Without surface defects; ThermalShockResistance: Conforms to ISO 10545–12; UpecC: n/a; UpecE: n/a; UpecP: n/a; UpecU: n/a; WaterAbsorption: 10%<=E<=20%
COBie - AssetIdentifier: n/a; BarCode: n/a; InstallationDate: 1900-12-31T23:59:59; TagNumber: n/a; WarrantyStartDate: 1900-12-31T23:59:59

# IfcWallStandardCase: Basic Wall:PGR_Porcelanosa_CeramicTiles_Spiga_Bottega_Caliza-450x1200mm-100214820, Basic Wall:PGR_Porcelanosa_CeramicTiles_Spiga_Bottega_Caliza-450x1200mm-100214820:213472
In: Level 1
Type - PredefinedType: STANDARD; Material: PGR_Porcelanosa_CeramicTiles_Spiga_Bottega_Caliza-450x1200mm-100214820 10.1 mm
Type - NBS_General - Author: Porcelanosa Group; BIMObjectName: PGR_Porcelanosa_CeramicTiles_Spiga_Bottega_Caliza-450x1200mm-100214820; ManufacturerURL: www.porcelanosa.com; NBSDescription: Ceramic Tiles; NBSReference: 45-80-95/310; ProductInformation: http://calidad.info-grupo.com:8081/GeneraFicha3/PDF?articulo=100214820&lang=EN&un=0; Revision: n/a; Uniclass2015Code: Pr_35_93_96_19; Uniclass2015Title: Ceramic Tiles; Uniclass2015Version: Products v1.5; Version: 1
Type - COBie - AccessibilityPerformance: See ProductInformation (Technical PDF); AssetType: Fixed; Category: Walls; CodePerformance: ISO-13006:2012; UNE-EN 14411:2012; Color: n/a; Constituents: Clays, feldespat and glaze; Description: Monoporous, BOTEGA series from PORCELANOSA, 45x120 cm (10 mm thickness), group BIII, according to UNE-EN 14411, water absortion capacity 10%<=E<=20%, flexural strength >23 N/mm² and breaking strength with an average value of 1337 N (Min. 600 N); DurationUnit: year; ExpectedLife: 50; Features: See ProductInformation (Technical PDF); Grade: First quality; Manufacturer: bim.gp@porcelanosagrupo.com; ModelNumber: 100214820; ModelReference: Spiga Bottega Caliza 45x120 cm; Name: CeramicTiles_Spiga_Bottega_Caliza-450x1200mm-100214820; NominalHeight: 10 mm; NominalLength: 1200 mm; NominalWidth: 450 mm; ReplacementCost: n/a; Shape: Rectangular; Size: 450x1200x10 mm; Sustainability Performance: See ProductInformation (Technical PDF); WarrantyDescription: Manufacturer warranty, applicable worldwide, with the pertinent national legislation prevailing in all cases and covering at least a 3-year period; all products must have been manufactured and fitted in accordance with the Fabricator's Manual, and have been used and cared for in accordance with the Guide to Use, Cleaning and Care available on the web page www.porcelanosa.com; WarrantyDurationLabor: n/a; WarrantyDurationParts: 3; WarrantyDurationUnit: year; WarrantyGuarantorLabor: n/a; WarrantyGuarantorParts: bim.gp@porcelanosagrupo.com
Type - Pset_CoveringCommon - Reference: n/a; IsExternal: no; AcousticRating: n/a; Finish: Relief; FireRating: A1; FlammabilityRating: Class 0; FragilityRating: n/a; Material: Ceramic; SurfaceSpreadOfFlame: Class 0; ThermalTransmittance: 230 kg/K/s3; TotalThickness: 10 mm
Type - IFC - IfcExportType: CLADDING; IfcExportAS: IfcCovering
Type - NBS_Data - HasSurfaceRoughness: yes; AbrasionResistance: n/a; BreakingStrength: Average Value: 1337 N (Min. 600 N); ChemicalResistance: Class 'A' for swimming pools and cleaning products (resists attack); minimum Class 'B' for acids and bases; Collection: Revestimiento Ceramico Rectificado; CreationDate: 2018/07; Dcof: n/a; FlexuralStrength: >23 N/mm²; FrostResistance: n/a; Group: BIII; MoistureExpansion: <0.1 mm/m; RampTest: n/a; RecycledContent: >18%; Series: Botega; SlipResistanceValuePendulumTestValue: n/a; StainResistance: Class 5: Easy cleaning with water; SurfaceQuality: Without surface defects; ThermalShockResistance: Conforms to ISO 10545–12; UpecC: n/a; UpecE: n/a; UpecP: n/a; UpecU: n/a; WaterAbsorption: 10%<=E<=20%
COBie - AssetIdentifier: n/a; BarCode: n/a; InstallationDate: 1900-12-31T23:59:59; TagNumber: n/a; WarrantyStartDate: 1900-12-31T23:59:59

# IfcWallStandardCase: Basic Wall:PGR_Porcelanosa_CeramicTiles_Twin_Bottega_Acero-450x1200mm-100214786, Basic Wall:PGR_Porcelanosa_CeramicTiles_Twin_Bottega_Acero-450x1200mm-100214786:213473
In: Level 1
Type - PredefinedType: STANDARD; Material: PGR_Porcelanosa_CeramicTiles_Twin_Bottega_Acero-450x1200mm-100214786 10.4 mm
Type - NBS_General - Author: Porcelanosa Group; BIMObjectName: PGR_Porcelanosa_CeramicTiles_Twin_Bottega_Acero-450x1200mm-100214786; ManufacturerURL: www.porcelanosa.com; NBSDescription: Ceramic Tiles; NBSReference: 45-80-95/310; ProductInformation: http://calidad.info-grupo.com:8081/GeneraFicha3/PDF?articulo=100214786&lang=EN&un=0; Revision: n/a; Uniclass2015Code: Pr_35_93_96_19; Uniclass2015Title: Ceramic Tiles; Uniclass2015Version: Products v1.5; Version: 1
Type - COBie - AccessibilityPerformance: See ProductInformation (Technical PDF); AssetType: Fixed; Category: Walls; CodePerformance: ISO-13006:2012; UNE-EN 14411:2012; Color: n/a; Constituents: Clays, feldespat and glaze; Description: Rectified Monoporous, BOTEGA series from PORCELANOSA, 45x120 cm (10.3 mm thickness), group BIII, according to UNE-EN 14411, water absortion capacity 10%<=E<=20%, flexural strength >23 N/mm² and breaking strength with an average value of 1337 N (Min. 600 N); DurationUnit: year; ExpectedLife: 50; Features: See ProductInformation (Technical PDF); Grade: First quality; Manufacturer: bim.gp@porcelanosagrupo.com; ModelNumber: 100214786; ModelReference: Twin Bottega Acero 45x120 cm; Name: CeramicTiles_Twin_Bottega_Acero-450x1200mm-100214786; NominalHeight: 10.3 mm; NominalLength: 1200 mm; NominalWidth: 450 mm; ReplacementCost: n/a; Shape: Rectangular; Size: 450x1200x10.3 mm; Sustainability Performance: See ProductInformation (Technical PDF); WarrantyDescription: Manufacturer warranty, applicable worldwide, with the pertinent national legislation prevailing in all cases and covering at least a 3-year period; all products must have been manufactured and fitted in accordance with the Fabricator's Manual, and have been used and cared for in accordance with the Guide to Use, Cleaning and Care available on the web page www.porcelanosa.com; WarrantyDurationLabor: n/a; WarrantyDurationParts: 3; WarrantyDurationUnit: year; WarrantyGuarantorLabor: n/a; WarrantyGuarantorParts: bim.gp@porcelanosagrupo.com
Type - Pset_CoveringCommon - Reference: n/a; IsExternal: no; AcousticRating: n/a; Finish: Rectified, Relief; FireRating: A1; FlammabilityRating: Class 0; FragilityRating: n/a; Material: Ceramic; SurfaceSpreadOfFlame: Class 0; ThermalTransmittance: 223.301 kg/K/s3; TotalThickness: 10.3 mm
Type - IFC - IfcExportType: CLADDING; IfcExportAS: IfcCovering
Type - NBS_Data - HasSurfaceRoughness: yes; AbrasionResistance: n/a; BreakingStrength: Average Value: 1337 N (Min. 600 N); ChemicalResistance: Class 'A' for swimming pools and cleaning products (resists attack); minimum Class 'B' for acids and bases; Collection: Revestimiento Ceramico Rectificado; CreationDate: 2018/07; Dcof: n/a; FlexuralStrength: >23 N/mm²; FrostResistance: n/a; Group: BIII; MoistureExpansion: <0.1 mm/m; RampTest: n/a; RecycledContent: >18%; Series: Botega; SlipResistanceValuePendulumTestValue: n/a; StainResistance: Class 5: Easy cleaning with water; SurfaceQuality: Without surface defects; ThermalShockResistance: Conforms to ISO 10545–12; UpecC: n/a; UpecE: n/a; UpecP: n/a; UpecU: n/a; WaterAbsorption: 10%<=E<=20%
COBie - AssetIdentifier: n/a; BarCode: n/a; InstallationDate: 1900-12-31T23:59:59; TagNumber: n/a; WarrantyStartDate: 1900-12-31T23:59:59

# IfcWallStandardCase: Basic Wall:PGR_Porcelanosa_CeramicTiles_Twin_Bottega_Caliza-450x1200mm-100214794, Basic Wall:PGR_Porcelanosa_CeramicTiles_Twin_Bottega_Caliza-450x1200mm-100214794:213474
In: Level 1
Type - PredefinedType: STANDARD; Material: PGR_Porcelanosa_CeramicTiles_Twin_Bottega_Caliza-450x1200mm-100214794 10.4 mm
Type - NBS_General - Author: Porcelanosa Group; BIMObjectName: PGR_Porcelanosa_CeramicTiles_Twin_Bottega_Caliza-450x1200mm-100214794; ManufacturerURL: www.porcelanosa.com; NBSDescription: Ceramic Tiles; NBSReference: 45-80-95/310; ProductInformation: http://calidad.info-grupo.com:8081/GeneraFicha3/PDF?articulo=100214794&lang=EN&un=0; Revision: n/a; Uniclass2015Code: Pr_35_93_96_19; Uniclass2015Title: Ceramic Tiles; Uniclass2015Version: Products v1.5; Version: 1
Type - COBie - AccessibilityPerformance: See ProductInformation (Technical PDF); AssetType: Fixed; Category: Walls; CodePerformance: ISO-13006:2012; UNE-EN 14411:2012; Color: n/a; Constituents: Clays, feldespat and glaze; Description: Monoporous, BOTEGA series from PORCELANOSA, 45x120 cm (10 mm thickness), group BIII, according to UNE-EN 14411, water absortion capacity 10%<=E<=20%, flexural strength >23 N/mm² and breaking strength with an average value of 1337 N (Min. 600 N); DurationUnit: year; ExpectedLife: 50; Features: See ProductInformation (Technical PDF); Grade: First quality; Manufacturer: bim.gp@porcelanosagrupo.com; ModelNumber: 100214794; ModelReference: Twin Bottega Caliza 45x120 cm; Name: CeramicTiles_Twin_Bottega_Caliza-450x1200mm-100214794; NominalHeight: 10 mm; NominalLength: 1200 mm; NominalWidth: 450 mm; ReplacementCost: n/a; Shape: Rectangular; Size: 450x1200x10 mm; Sustainability Performance: See ProductInformation (Technical PDF); WarrantyDescription: Manufacturer warranty, applicable worldwide, with the pertinent national legislation prevailing in all cases and covering at least a 3-year period; all products must have been manufactured and fitted in accordance with the Fabricator's Manual, and have been used and cared for in accordance with the Guide to Use, Cleaning and Care available on the web page www.porcelanosa.com; WarrantyDurationLabor: n/a; WarrantyDurationParts: 3; WarrantyDurationUnit: year; WarrantyGuarantorLabor: n/a; WarrantyGuarantorParts: bim.gp@porcelanosagrupo.com
Type - Pset_CoveringCommon - Reference: n/a; IsExternal: no; AcousticRating: n/a; Finish: Relief; FireRating: A1; FlammabilityRating: Class 0; FragilityRating: n/a; Material: Ceramic; SurfaceSpreadOfFlame: Class 0; ThermalTransmittance: 230 kg/K/s3; TotalThickness: 10 mm
Type - IFC - IfcExportType: CLADDING; IfcExportAS: IfcCovering
Type - NBS_Data - HasSurfaceRoughness: yes; AbrasionResistance: n/a; BreakingStrength: Average Value: 1337 N (Min. 600 N); ChemicalResistance: Class 'A' for swimming pools and cleaning products (resists attack); minimum Class 'B' for acids and bases; Collection: Revestimiento Ceramico Rectificado; CreationDate: 2018/07; Dcof: n/a; FlexuralStrength: >23 N/mm²; FrostResistance: n/a; Group: BIII; MoistureExpansion: <0.1 mm/m; RampTest: n/a; RecycledContent: >18%; Series: Botega; SlipResistanceValuePendulumTestValue: n/a; StainResistance: Class 5: Easy cleaning with water; SurfaceQuality: Without surface defects; ThermalShockResistance: Conforms to ISO 10545–12; UpecC: n/a; UpecE: n/a; UpecP: n/a; UpecU: n/a; WaterAbsorption: 10%<=E<=20%
COBie - AssetIdentifier: n/a; BarCode: n/a; InstallationDate: 1900-12-31T23:59:59; TagNumber: n/a; WarrantyStartDate: 1900-12-31T23:59:59
